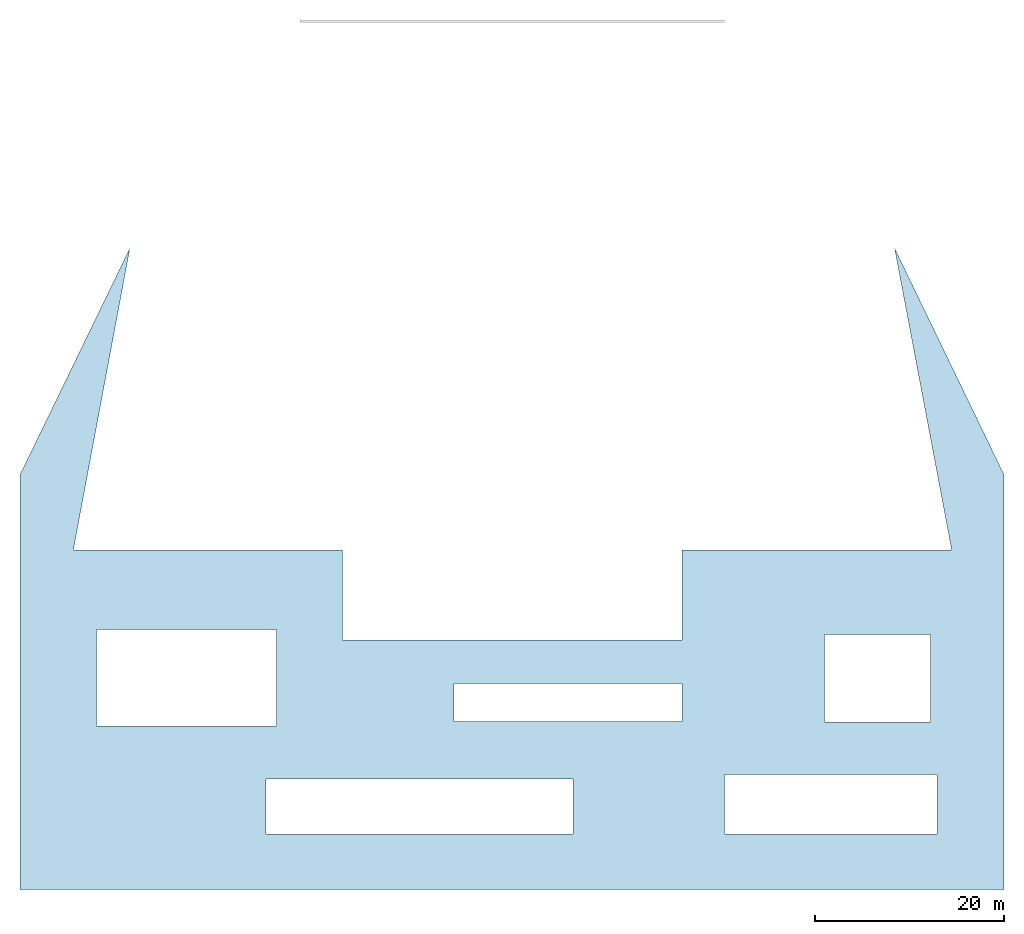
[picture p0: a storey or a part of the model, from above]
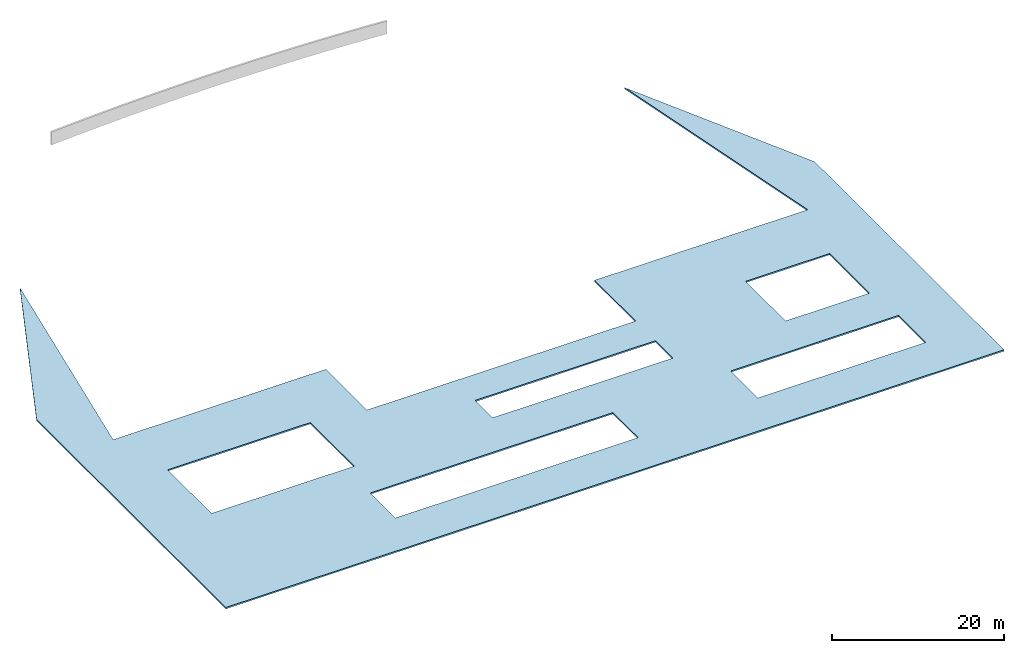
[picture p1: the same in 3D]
Properties of the parts of a building model (IFC2X3), part 1 of 4

# File
Description: ViewDefinition [CoordinationView_V2.0, QuantityTakeOffAddOnView]
File name: Project Number
Time: 2019-07-19T18:44:57
Written by: The EXPRESS Data Manager Version 5.02.0100.07 : 28 Aug 2013
Made in: 20170223_1515(x64) - Exporter 18.4.0.0 - Alternate UI 18.4.0.0
Comment: STEP Physical File produced by: The EXPRESS Data Manager Version 5.02.0100.07 : 28 Aug 2013 * Module: EDMstepFileFactory/EDMstandAlone * Creation date: Fri Jul 19 18:44:57 2019 * Host: ICIVEML714002 * Database: C:\Users\JL9E96~1.PON\AppData\Local\Temp\{DA7AC324-765A-4AAA-A41D-38224F9B8CCA}\ifc * Database version: 5507 * Database creation date: Fri Jul 19 18:44:33 2019 * Schema: IFC2X3 * Model: DataRepository.ifc * Model creation date: Fri Jul 19 18:44:33 2019 * Header model: DataRepository.ifc_HeaderModel * Header model creation date: Fri Jul 19 18:44:33 2019 * EDMuser: sdai-user * EDMgroup: sdai-group * License ID and type: 5605 : Permanent license. Expiry date: * EDMstepFileFactory options: 020000

# IfcProject, Project Number
LongName: Project Name; Phase: Project Status

# IfcSite, Default
RefLatitude: 47, 33, 34, 948799; RefLongitude: 19, 3, 17, 204399; RefElevation: 0 mm
Other - Category: Project Information; Client Name: Owner; Project Address: ## Street City, State Zip; Project Issue Date: Issue Date; Project Name: Project Name; Project Number: Project Number; Project Status: Project Status

# IfcBuilding
Pset_BuildingCommon - NumberOfStoreys: 6
Pset_ProductRequirements - Category: Project Information
Other - Category: Project Information; Client Name: Owner; Project Address: ## Street City, State Zip; Project Issue Date: Issue Date; Project Name: Project Name; Project Number: Project Number; Project Status: Project Status

# IfcBuildingStorey: Level:8mm Head (6)
Other(Type) - Category: Levels; Family Name: Level
Identity Data(Type) - Type Name: 8mm Head
Graphics(Type) - Color: 0; Line Pattern: Center; Line Weight: 1; Symbol: M_Level Head - Circle: M_Level Head - Circle; Symbol at End 1 Default: no; Symbol at End 2 Default: yes
Constraints(Type) - Elevation Base: Project Base Point
Pset_ProductRequirements - Category: Levels
Dimensions - Computation Height: 0 mm
Identity Data - Building Story: yes; Structural: no
Other - Category: Levels; Family: Level: 8mm Head; Family and Type: Level: 8mm Head; Type: Level: 8mm Head; Type Id: Level: 8mm Head
Name | LongName = Pset_AirSideSystemInformation, Name = Pset_ProductRequirements, Name = Identity Data, Name | Elevation (mm) = Constraints, Elevation (mm)
-4. Story | -4. Story | -5500
-2. Story | -2. Story | -3000
-1. Story | -1. Story | -1000
Ground Floor | Ground Floor | 0
1. Story | 1. Story | 3600
2. Story | 2. Story | 6600

# IfcBuildingElementProxy: BMR - 026, BMR - 026:BMR - 026:220502
In: 2. Story
Type - Classification: B1020245 Beams - Wood (Laminated) (Uniformat); Material: Paint - Yellow Ochre
Type - Identity Data - Assembly Code: B1020245; Assembly Description: Beams - Wood (Laminated); Type Name: BMR - 026
Type - Other - Category: Structural Framing; Family Name: BMR - 026
Type - Structural - Section Shape: 0
Type - Pset_BuildingElementProxyCommon - Reference: 07_Glued_laminated_timber 250 x 1810
Type - Pset_ProductRequirements - Category: Structural Framing
Type - Pset_QuantityTakeOff - Reference: 07_Glued_laminated_timber 250 x 1810
Pset_BuildingElementProxyCommon - sets with these values: 2
Constraints - Moves With Nearby Elements: no
Dimensions - Area: 95.7812 m2; Volume: 20.9311 m3
Materials and Finishes - Structural Material: Plywood, Sheathing
Other - Family: BMR - 026: BMR - 026; Family and Type: BMR - 026: BMR - 026; Type: BMR - 026: BMR - 026; Type Id: BMR - 026: BMR - 026
Phasing - Phase Created: New Construction
Structural - Rebar Cover: Rebar Cover Settings: Rebar Cover 1

# IfcBuildingElementProxy: BMR - 027, BMR - 027:BMR - 027:220488
In: 1. Story
Type - Classification: B1020245 Beams - Wood (Laminated) (Uniformat); Material: Paint - Yellow Ochre
Type - Identity Data - Assembly Code: B1020245; Assembly Description: Beams - Wood (Laminated); Type Name: BMR - 027
Type - Other - Category: Structural Framing; Family Name: BMR - 027
Type - Structural - Section Shape: 0
Type - Pset_BuildingElementProxyCommon - Reference: 07_Glued_laminated_timber 250 x 1810
Type - Pset_ProductRequirements - Category: Structural Framing
Type - Pset_QuantityTakeOff - Reference: 07_Glued_laminated_timber 250 x 1810
Pset_BuildingElementProxyCommon - sets with these values: 2
Constraints - Moves With Nearby Elements: no
Dimensions - Area: 95.1594 m2; Volume: 20.7967 m3
Materials and Finishes - Structural Material: Plywood, Sheathing
Other - Family: BMR - 027: BMR - 027; Family and Type: BMR - 027: BMR - 027; Type: BMR - 027: BMR - 027; Type Id: BMR - 027: BMR - 027
Phasing - Phase Created: New Construction
Structural - Rebar Cover: Rebar Cover Settings: Rebar Cover 1

# IfcBuildingElementProxy: BMR - 028, BMR - 028:BMR - 028:220460
In: 1. Story
Type - Classification: B1020245 Beams - Wood (Laminated) (Uniformat); Material: Paint - Yellow Ochre
Type - Identity Data - Assembly Code: B1020245; Assembly Description: Beams - Wood (Laminated); Type Name: BMR - 028
Type - Other - Category: Structural Framing; Family Name: BMR - 028
Type - Structural - Section Shape: 0
Type - Pset_BuildingElementProxyCommon - Reference: 07_Glued_laminated_timber 250 x 1810
Type - Pset_ProductRequirements - Category: Structural Framing
Type - Pset_QuantityTakeOff - Reference: 07_Glued_laminated_timber 250 x 1810
Pset_BuildingElementProxyCommon - sets with these values: 2
Constraints - Moves With Nearby Elements: no
Dimensions - Area: 94.1748 m2; Volume: 20.5838 m3
Materials and Finishes - Structural Material: Plywood, Sheathing
Other - Family: BMR - 028: BMR - 028; Family and Type: BMR - 028: BMR - 028; Type: BMR - 028: BMR - 028; Type Id: BMR - 028: BMR - 028
Phasing - Phase Created: New Construction
Structural - Rebar Cover: Rebar Cover Settings: Rebar Cover 1

# IfcBuildingElementProxy: BMR - 028, BMR - 028 2187528:BMR - 028 2187528:220481
In: 1. Story
Type - Classification: B1020245 Beams - Wood (Laminated) (Uniformat); Material: Paint - Yellow Ochre
Type - Identity Data - Assembly Code: B1020245; Assembly Description: Beams - Wood (Laminated); Type Name: BMR - 028 2187528
Type - Other - Category: Structural Framing; Family Name: BMR - 028 2187528
Type - Structural - Section Shape: 0
Type - Pset_BuildingElementProxyCommon - Reference: 07_Glued_laminated_timber 250 x 1810
Type - Pset_ProductRequirements - Category: Structural Framing
Type - Pset_QuantityTakeOff - Reference: 07_Glued_laminated_timber 250 x 1810
Pset_BuildingElementProxyCommon - sets with these values: 2
Constraints - Moves With Nearby Elements: no
Dimensions - Area: 94.6252 m2; Volume: 20.6812 m3
Materials and Finishes - Structural Material: Plywood, Sheathing
Other - Family: BMR - 028 2187528: BMR - 028 2187528; Family and Type: BMR - 028 2187528: BMR - 028 2187528; Type: BMR - 028 2187528: BMR - 028 2187528; Type Id: BMR - 028 2187528: BMR - 028 2187528
Phasing - Phase Created: New Construction
Structural - Rebar Cover: Rebar Cover Settings: Rebar Cover 1

# IfcBuildingElementProxy: BMR - 029, BMR - 029:BMR - 029:220467
In: Ground Floor
Type - Classification: B1020245 Beams - Wood (Laminated) (Uniformat); Material: Paint - Yellow Ochre
Type - Identity Data - Assembly Code: B1020245; Assembly Description: Beams - Wood (Laminated); Type Name: BMR - 029
Type - Other - Category: Structural Framing; Family Name: BMR - 029
Type - Structural - Section Shape: 0
Type - Pset_BuildingElementProxyCommon - Reference: 07_Glued_laminated_timber 250 x 1810
Type - Pset_ProductRequirements - Category: Structural Framing
Type - Pset_QuantityTakeOff - Reference: 07_Glued_laminated_timber 250 x 1810
Pset_BuildingElementProxyCommon - sets with these values: 2
Constraints - Moves With Nearby Elements: no
Dimensions - Area: 93.8023 m2; Volume: 20.5032 m3
Materials and Finishes - Structural Material: Plywood, Sheathing
Other - Family: BMR - 029: BMR - 029; Family and Type: BMR - 029: BMR - 029; Type: BMR - 029: BMR - 029; Type Id: BMR - 029: BMR - 029
Phasing - Phase Created: New Construction
Structural - Rebar Cover: Rebar Cover Settings: Rebar Cover 1

# IfcBuildingElementProxy: BMR - 030, BMR - 030:BMR - 030:220416
In: Ground Floor
Type - Classification: B1020245 Beams - Wood (Laminated) (Uniformat); Material: Paint - Yellow Ochre
Type - Identity Data - Assembly Code: B1020245; Assembly Description: Beams - Wood (Laminated); Type Name: BMR - 030
Type - Other - Category: Structural Framing; Family Name: BMR - 030
Type - Structural - Section Shape: 0
Type - Pset_BuildingElementProxyCommon - Reference: 07_Glued_laminated_timber 250 x 1810
Type - Pset_ProductRequirements - Category: Structural Framing
Type - Pset_QuantityTakeOff - Reference: 07_Glued_laminated_timber 250 x 1810
Pset_BuildingElementProxyCommon - sets with these values: 2
Constraints - Moves With Nearby Elements: no
Dimensions - Area: 93.522 m2; Volume: 20.4425 m3
Materials and Finishes - Structural Material: Plywood, Sheathing
Other - Family: BMR - 030: BMR - 030; Family and Type: BMR - 030: BMR - 030; Type: BMR - 030: BMR - 030; Type Id: BMR - 030: BMR - 030
Phasing - Phase Created: New Construction
Structural - Rebar Cover: Rebar Cover Settings: Rebar Cover 1

# IfcBuildingElementProxy: BMR - 031, BMR - 031:BMR - 031:217719
In: Ground Floor
Type - Classification: B1020245 Beams - Wood (Laminated) (Uniformat); Material: Paint - Yellow Ochre
Type - Identity Data - Assembly Code: B1020245; Assembly Description: Beams - Wood (Laminated); Type Name: BMR - 031
Type - Other - Category: Structural Framing; Family Name: BMR - 031
Type - Structural - Section Shape: 0
Type - Pset_BuildingElementProxyCommon - Reference: 07_Glued_laminated_timber 250 x 1810
Type - Pset_ProductRequirements - Category: Structural Framing
Type - Pset_QuantityTakeOff - Reference: 07_Glued_laminated_timber 250 x 1810
Pset_BuildingElementProxyCommon - sets with these values: 2
Constraints - Moves With Nearby Elements: no
Dimensions - Area: 93.3194 m2; Volume: 20.3987 m3
Materials and Finishes - Structural Material: Plywood, Sheathing
Other - Family: BMR - 031: BMR - 031; Family and Type: BMR - 031: BMR - 031; Type: BMR - 031: BMR - 031; Type Id: BMR - 031: BMR - 031
Phasing - Phase Created: New Construction
Structural - Rebar Cover: Rebar Cover Settings: Rebar Cover 1

# IfcBuildingElementProxy: BMR - 032, BMR - 032:BMR - 032:217654
In: -1. Story
Type - Classification: B1020245 Beams - Wood (Laminated) (Uniformat); Material: Plywood, Sheathing
Type - Identity Data - Assembly Code: B1020245; Assembly Description: Beams - Wood (Laminated); Type Name: BMR - 032
Type - Other - Category: Structural Framing; Family Name: BMR - 032
Type - Structural - Section Shape: 0
Type - Pset_BuildingElementProxyCommon - Reference: 07_Glued_laminated_timber 250 x 1810
Type - Pset_ProductRequirements - Category: Structural Framing
Type - Pset_QuantityTakeOff - Reference: 07_Glued_laminated_timber 250 x 1810
Pset_BuildingElementProxyCommon - sets with these values: 2
Constraints - Moves With Nearby Elements: no
Materials and Finishes - Structural Material: Plywood, Sheathing
Other - Family: BMR - 032: BMR - 032; Family and Type: BMR - 032: BMR - 032; Type: BMR - 032: BMR - 032; Type Id: BMR - 032: BMR - 032
Phasing - Phase Created: New Construction
Structural - Rebar Cover: Rebar Cover Settings: Rebar Cover 1

# IfcBuildingElementProxy: FU - 004, FU - 004:FU - 004:213398
In: Ground Floor
Type - Classification: G2010500 Painted Lines & Markings (Uniformat); Material: Paint - Titanium White
Type - Identity Data - Assembly Code: G2010500; Assembly Description: Painted Lines & Markings; Type Name: FU - 004
Type - Other - Category: Generic Models; Family Name: FU - 004
Type - Pset_BuildingElementProxyCommon - Reference: FU - 004
Type - Pset_ProductRequirements - Category: Generic Models
Type - Pset_QuantityTakeOff - Reference: FU - 004
Pset_BuildingElementProxyCommon - sets with these values: 2
Constraints - Moves With Nearby Elements: no
Dimensions - Area: 57.5186 m2; Volume: 1.4172 m3
Other - Family: FU - 004: FU - 004; Family and Type: FU - 004: FU - 004; Type: FU - 004: FU - 004; Type Id: FU - 004: FU - 004
Phasing - Phase Created: New Construction

# IfcBuildingElementProxy: FU - 004, FU - 004 1750820:FU - 004 1750820:214772
In: Ground Floor
Type - Classification: G2010500 Painted Lines & Markings (Uniformat); Material: Paint - Titanium White, Metal - Stainless Steel
Type - Identity Data - Assembly Code: G2010500; Assembly Description: Painted Lines & Markings; Type Name: FU - 004 1750820
Type - Other - Category: Generic Models; Family Name: FU - 004 1750820
Type - Pset_BuildingElementProxyCommon - Reference: FU - 004 1750820
Type - Pset_ProductRequirements - Category: Generic Models
Type - Pset_QuantityTakeOff - Reference: FU - 004 1750820
Pset_BuildingElementProxyCommon - sets with these values: 2
Constraints - Moves With Nearby Elements: no
Dimensions - Area: 12.684 m2; Volume: 0.286123 m3
Other - Family: FU - 004 1750820: FU - 004 1750820; Family and Type: FU - 004 1750820: FU - 004 1750820; Type: FU - 004 1750820: FU - 004 1750820; Type Id: FU - 004 1750820: FU - 004 1750820
Phasing - Phase Created: New Construction

# IfcBuildingElementProxy: FU - 004, FU - 004 1769644:FU - 004 1769644:215817
In: Ground Floor
Type - Classification: G2010500 Painted Lines & Markings (Uniformat); Material: Paint - Titanium White, Metal - Stainless Steel
Type - Identity Data - Assembly Code: G2010500; Assembly Description: Painted Lines & Markings; Type Name: FU - 004 1769644
Type - Other - Category: Generic Models; Family Name: FU - 004 1769644
Type - Pset_BuildingElementProxyCommon - Reference: FU - 004 1769644
Type - Pset_ProductRequirements - Category: Generic Models
Type - Pset_QuantityTakeOff - Reference: FU - 004 1769644
Pset_BuildingElementProxyCommon - sets with these values: 2
Constraints - Moves With Nearby Elements: no
Dimensions - Area: 12.684 m2; Volume: 0.286123 m3
Other - Family: FU - 004 1769644: FU - 004 1769644; Family and Type: FU - 004 1769644: FU - 004 1769644; Type: FU - 004 1769644: FU - 004 1769644; Type Id: FU - 004 1769644: FU - 004 1769644
Phasing - Phase Created: New Construction

# IfcBuildingElementProxy: FU - 004, FU - 004 1777966:FU - 004 1777966:216424
In: Ground Floor
Type - Classification: G2010500 Painted Lines & Markings (Uniformat); Material: Paint - Titanium White, Metal - Stainless Steel
Type - Identity Data - Assembly Code: G2010500; Assembly Description: Painted Lines & Markings; Type Name: FU - 004 1777966
Type - Other - Category: Generic Models; Family Name: FU - 004 1777966
Type - Pset_BuildingElementProxyCommon - Reference: FU - 004 1777966
Type - Pset_ProductRequirements - Category: Generic Models
Type - Pset_QuantityTakeOff - Reference: FU - 004 1777966
Pset_BuildingElementProxyCommon - sets with these values: 2
Constraints - Moves With Nearby Elements: no
Dimensions - Area: 12.684 m2; Volume: 0.286123 m3
Other - Family: FU - 004 1777966: FU - 004 1777966; Family and Type: FU - 004 1777966: FU - 004 1777966; Type: FU - 004 1777966: FU - 004 1777966; Type Id: FU - 004 1777966: FU - 004 1777966
Phasing - Phase Created: New Construction

# IfcBuildingElementProxy: FU - 004, FU - 004 2050029:FU - 004 2050029:217726
In: Ground Floor
Type - Classification: G2010500 Painted Lines & Markings (Uniformat); Material: Paint - Titanium White, Metal - Stainless Steel
Type - Identity Data - Assembly Code: G2010500; Assembly Description: Painted Lines & Markings; Type Name: FU - 004 2050029
Type - Other - Category: Generic Models; Family Name: FU - 004 2050029
Type - Pset_BuildingElementProxyCommon - Reference: FU - 004 2050029
Type - Pset_ProductRequirements - Category: Generic Models
Type - Pset_QuantityTakeOff - Reference: FU - 004 2050029
Pset_BuildingElementProxyCommon - sets with these values: 2
Constraints - Moves With Nearby Elements: no
Dimensions - Area: 12.684 m2; Volume: 0.286123 m3
Other - Family: FU - 004 2050029: FU - 004 2050029; Family and Type: FU - 004 2050029: FU - 004 2050029; Type: FU - 004 2050029: FU - 004 2050029; Type Id: FU - 004 2050029: FU - 004 2050029
Phasing - Phase Created: New Construction

# IfcBuildingElementProxy: FU - 007, FU - 007:FU - 007:201155
In: -4. Story
Type - Classification: F1040100 Aquatic Facilities (Uniformat); Material: Paint - Gray, Water - Pond, Paint - Titanium White, Metal - Stainless Steel, Paint - Royal Blue, Paint - Vermilion
Type - Identity Data - Assembly Code: F1040100; Assembly Description: Aquatic Facilities; Type Name: FU - 007
Type - Other - Category: Generic Models; Family Name: FU - 007
Type - Pset_BuildingElementProxyCommon - Reference: FU - 007
Type - Pset_ProductRequirements - Category: Generic Models
Type - Pset_QuantityTakeOff - Reference: FU - 007
Pset_BuildingElementProxyCommon - sets with these values: 2
Constraints - Moves With Nearby Elements: no
Dimensions - Area: 2268.79 m2; Volume: 1597.47 m3
Other - Family: FU - 007: FU - 007; Family and Type: FU - 007: FU - 007; Type: FU - 007: FU - 007; Type Id: FU - 007: FU - 007
Phasing - Phase Created: New Construction

# IfcBuildingElementProxy: FU - 007, FU - 007 1380037:FU - 007 1380037:201343
In: -4. Story
Type - Classification: F1040100 Aquatic Facilities (Uniformat); Material: Paint - Gray, Water - Pond, Paint - Titanium White, Metal - Stainless Steel, Paint - Royal Blue, Paint - Vermilion
Type - Identity Data - Assembly Code: F1040100; Assembly Description: Aquatic Facilities; Type Name: FU - 007 1380037
Type - Other - Category: Generic Models; Family Name: FU - 007 1380037
Type - Pset_BuildingElementProxyCommon - Reference: FU - 007 1380037
Type - Pset_ProductRequirements - Category: Generic Models
Type - Pset_QuantityTakeOff - Reference: FU - 007 1380037
Pset_BuildingElementProxyCommon - sets with these values: 2
Constraints - Moves With Nearby Elements: no
Dimensions - Area: 1217.01 m2; Volume: 806.765 m3
Other - Family: FU - 007 1380037: FU - 007 1380037; Family and Type: FU - 007 1380037: FU - 007 1380037; Type: FU - 007 1380037: FU - 007 1380037; Type Id: FU - 007 1380037: FU - 007 1380037
Phasing - Phase Created: New Construction

# IfcBuildingElementProxy: FU - 008, FU - 008 1515161:FU - 008 1515161:205280
In: -2. Story
Type - Classification: E2020200 Furniture & Accessories (Uniformat); Material: Glass - Mirror, Metal - Stainless Steel
Type - Identity Data - Assembly Code: E2020200; Assembly Description: Furniture & Accessories; Type Name: FU - 008 1515161
Type - Other - Category: Generic Models; Family Name: FU - 008 1515161
Type - Pset_BuildingElementProxyCommon - Reference: FU - 008 1515161
Type - Pset_ProductRequirements - Category: Generic Models
Type - Pset_QuantityTakeOff - Reference: FU - 008 1515161
Pset_BuildingElementProxyCommon - sets with these values: 2
Constraints - Moves With Nearby Elements: no
Dimensions - Area: 1.91536 m2; Volume: 0.0251271 m3
Other - Family: FU - 008 1515161: FU - 008 1515161; Family and Type: FU - 008 1515161: FU - 008 1515161; Type: FU - 008 1515161: FU - 008 1515161; Type Id: FU - 008 1515161: FU - 008 1515161
Phasing - Phase Created: New Construction

# IfcBuildingElementProxy: FU - 008, FU - 008 1515332:FU - 008 1515332:205342
In: -2. Story
Type - Classification: E2020200 Furniture & Accessories (Uniformat); Material: Glass - Mirror, Metal - Stainless Steel
Type - Identity Data - Assembly Code: E2020200; Assembly Description: Furniture & Accessories; Type Name: FU - 008 1515332
Type - Other - Category: Generic Models; Family Name: FU - 008 1515332
Type - Pset_BuildingElementProxyCommon - Reference: FU - 008 1515332
Type - Pset_ProductRequirements - Category: Generic Models
Type - Pset_QuantityTakeOff - Reference: FU - 008 1515332
Pset_BuildingElementProxyCommon - sets with these values: 2
Constraints - Moves With Nearby Elements: no
Dimensions - Area: 1.91536 m2; Volume: 0.0251271 m3
Other - Family: FU - 008 1515332: FU - 008 1515332; Family and Type: FU - 008 1515332: FU - 008 1515332; Type: FU - 008 1515332: FU - 008 1515332; Type Id: FU - 008 1515332: FU - 008 1515332
Phasing - Phase Created: New Construction

# IfcBuildingElementProxy: FU - 008, FU - 008 1568106:FU - 008 1568106:208407
In: -2. Story
Type - Classification: E2020200 Furniture & Accessories (Uniformat); Material: Glass - Mirror, Metal - Stainless Steel
Type - Identity Data - Assembly Code: E2020200; Assembly Description: Furniture & Accessories; Type Name: FU - 008 1568106
Type - Other - Category: Generic Models; Family Name: FU - 008 1568106
Type - Pset_BuildingElementProxyCommon - Reference: FU - 008 1568106
Type - Pset_ProductRequirements - Category: Generic Models
Type - Pset_QuantityTakeOff - Reference: FU - 008 1568106
Pset_BuildingElementProxyCommon - sets with these values: 2
Constraints - Moves With Nearby Elements: no
Dimensions - Area: 2.07269 m2; Volume: 0.0271752 m3
Other - Family: FU - 008 1568106: FU - 008 1568106; Family and Type: FU - 008 1568106: FU - 008 1568106; Type: FU - 008 1568106: FU - 008 1568106; Type Id: FU - 008 1568106: FU - 008 1568106
Phasing - Phase Created: New Construction

# IfcBuildingElementProxy: FU - 008, FU - 008 1568273:FU - 008 1568273:208449
In: -2. Story
Type - Classification: E2020200 Furniture & Accessories (Uniformat); Material: Glass - Mirror, Metal - Stainless Steel
Type - Identity Data - Assembly Code: E2020200; Assembly Description: Furniture & Accessories; Type Name: FU - 008 1568273
Type - Other - Category: Generic Models; Family Name: FU - 008 1568273
Type - Pset_BuildingElementProxyCommon - Reference: FU - 008 1568273
Type - Pset_ProductRequirements - Category: Generic Models
Type - Pset_QuantityTakeOff - Reference: FU - 008 1568273
Pset_BuildingElementProxyCommon - sets with these values: 2
Constraints - Moves With Nearby Elements: no
Dimensions - Area: 1.91536 m2; Volume: 0.0251271 m3
Other - Family: FU - 008 1568273: FU - 008 1568273; Family and Type: FU - 008 1568273: FU - 008 1568273; Type: FU - 008 1568273: FU - 008 1568273; Type Id: FU - 008 1568273: FU - 008 1568273
Phasing - Phase Created: New Construction

# IfcBuildingElementProxy: FU - 008, FU - 008 1568431:FU - 008 1568431:208491
In: -2. Story
Type - Classification: E2020200 Furniture & Accessories (Uniformat); Material: Glass - Mirror, Metal - Stainless Steel
Type - Identity Data - Assembly Code: E2020200; Assembly Description: Furniture & Accessories; Type Name: FU - 008 1568431
Type - Other - Category: Generic Models; Family Name: FU - 008 1568431
Type - Pset_BuildingElementProxyCommon - Reference: FU - 008 1568431
Type - Pset_ProductRequirements - Category: Generic Models
Type - Pset_QuantityTakeOff - Reference: FU - 008 1568431
Pset_BuildingElementProxyCommon - sets with these values: 2
Constraints - Moves With Nearby Elements: no
Dimensions - Area: 1.91536 m2; Volume: 0.0251271 m3
Other - Family: FU - 008 1568431: FU - 008 1568431; Family and Type: FU - 008 1568431: FU - 008 1568431; Type: FU - 008 1568431: FU - 008 1568431; Type Id: FU - 008 1568431: FU - 008 1568431
Phasing - Phase Created: New Construction

# IfcBuildingElementProxy: FU - 008, FU - 008 1590037:FU - 008 1590037:209053
In: -2. Story
Type - Classification: E2020200 Furniture & Accessories (Uniformat); Material: Glass - Mirror, Metal - Stainless Steel
Type - Identity Data - Assembly Code: E2020200; Assembly Description: Furniture & Accessories; Type Name: FU - 008 1590037
Type - Other - Category: Generic Models; Family Name: FU - 008 1590037
Type - Pset_BuildingElementProxyCommon - Reference: FU - 008 1590037
Type - Pset_ProductRequirements - Category: Generic Models
Type - Pset_QuantityTakeOff - Reference: FU - 008 1590037
Pset_BuildingElementProxyCommon - sets with these values: 2
Constraints - Moves With Nearby Elements: no
Dimensions - Area: 1.91536 m2; Volume: 0.0251271 m3
Other - Family: FU - 008 1590037: FU - 008 1590037; Family and Type: FU - 008 1590037: FU - 008 1590037; Type: FU - 008 1590037: FU - 008 1590037; Type Id: FU - 008 1590037: FU - 008 1590037
Phasing - Phase Created: New Construction

# IfcBuildingElementProxy: FU - 008, FU - 008 1590204:FU - 008 1590204:209095
In: -2. Story
Type - Classification: E2020200 Furniture & Accessories (Uniformat); Material: Glass - Mirror, Metal - Stainless Steel
Type - Identity Data - Assembly Code: E2020200; Assembly Description: Furniture & Accessories; Type Name: FU - 008 1590204
Type - Other - Category: Generic Models; Family Name: FU - 008 1590204
Type - Pset_BuildingElementProxyCommon - Reference: FU - 008 1590204
Type - Pset_ProductRequirements - Category: Generic Models
Type - Pset_QuantityTakeOff - Reference: FU - 008 1590204
Pset_BuildingElementProxyCommon - sets with these values: 2
Constraints - Moves With Nearby Elements: no
Dimensions - Area: 1.91536 m2; Volume: 0.0251271 m3
Other - Family: FU - 008 1590204: FU - 008 1590204; Family and Type: FU - 008 1590204: FU - 008 1590204; Type: FU - 008 1590204: FU - 008 1590204; Type Id: FU - 008 1590204: FU - 008 1590204
Phasing - Phase Created: New Construction

# IfcBuildingElementProxy: FU - 008, FU - 008 1618691:FU - 008 1618691:212044
In: -2. Story
Type - Classification: E2020200 Furniture & Accessories (Uniformat); Material: Glass - Mirror, Metal - Stainless Steel
Type - Identity Data - Assembly Code: E2020200; Assembly Description: Furniture & Accessories; Type Name: FU - 008 1618691
Type - Other - Category: Generic Models; Family Name: FU - 008 1618691
Type - Pset_BuildingElementProxyCommon - Reference: FU - 008 1618691
Type - Pset_ProductRequirements - Category: Generic Models
Type - Pset_QuantityTakeOff - Reference: FU - 008 1618691
Pset_BuildingElementProxyCommon - sets with these values: 2
Constraints - Moves With Nearby Elements: no
Dimensions - Area: 2.07269 m2; Volume: 0.0271752 m3
Other - Family: FU - 008 1618691: FU - 008 1618691; Family and Type: FU - 008 1618691: FU - 008 1618691; Type: FU - 008 1618691: FU - 008 1618691; Type Id: FU - 008 1618691: FU - 008 1618691
Phasing - Phase Created: New Construction

# IfcBuildingElementProxy: FU - 008, FU - 008 1618858:FU - 008 1618858:212086
In: -2. Story
Type - Classification: E2020200 Furniture & Accessories (Uniformat); Material: Glass - Mirror, Metal - Stainless Steel
Type - Identity Data - Assembly Code: E2020200; Assembly Description: Furniture & Accessories; Type Name: FU - 008 1618858
Type - Other - Category: Generic Models; Family Name: FU - 008 1618858
Type - Pset_BuildingElementProxyCommon - Reference: FU - 008 1618858
Type - Pset_ProductRequirements - Category: Generic Models
Type - Pset_QuantityTakeOff - Reference: FU - 008 1618858
Pset_BuildingElementProxyCommon - sets with these values: 2
Constraints - Moves With Nearby Elements: no
Dimensions - Area: 1.91536 m2; Volume: 0.0251271 m3
Other - Family: FU - 008 1618858: FU - 008 1618858; Family and Type: FU - 008 1618858: FU - 008 1618858; Type: FU - 008 1618858: FU - 008 1618858; Type Id: FU - 008 1618858: FU - 008 1618858
Phasing - Phase Created: New Construction

# IfcBuildingElementProxy: FU - 008, FU - 008 1619016:FU - 008 1619016:212128
In: -2. Story
Type - Classification: E2020200 Furniture & Accessories (Uniformat); Material: Glass - Mirror, Metal - Stainless Steel
Type - Identity Data - Assembly Code: E2020200; Assembly Description: Furniture & Accessories; Type Name: FU - 008 1619016
Type - Other - Category: Generic Models; Family Name: FU - 008 1619016
Type - Pset_BuildingElementProxyCommon - Reference: FU - 008 1619016
Type - Pset_ProductRequirements - Category: Generic Models
Type - Pset_QuantityTakeOff - Reference: FU - 008 1619016
Pset_BuildingElementProxyCommon - sets with these values: 2
Constraints - Moves With Nearby Elements: no
Dimensions - Area: 1.91536 m2; Volume: 0.0251271 m3
Other - Family: FU - 008 1619016: FU - 008 1619016; Family and Type: FU - 008 1619016: FU - 008 1619016; Type: FU - 008 1619016: FU - 008 1619016; Type Id: FU - 008 1619016: FU - 008 1619016
Phasing - Phase Created: New Construction

# IfcBuildingElementProxy: FU - 008, FU - 008:FU - 008:202605
In: -4. Story
Type - Classification: F1040100 Aquatic Facilities (Uniformat); Material: Paint - Gray, Water - Pond, Paint - Titanium White, Metal - Stainless Steel
Type - Identity Data - Assembly Code: F1040100; Assembly Description: Aquatic Facilities; Type Name: FU - 008
Type - Other - Category: Generic Models; Family Name: FU - 008
Type - Pset_BuildingElementProxyCommon - Reference: FU - 008
Type - Pset_ProductRequirements - Category: Generic Models
Type - Pset_QuantityTakeOff - Reference: FU - 008
Pset_BuildingElementProxyCommon - sets with these values: 2
Constraints - Moves With Nearby Elements: no
Dimensions - Area: 376.904 m2; Volume: 195.702 m3
Other - Family: FU - 008: FU - 008; Family and Type: FU - 008: FU - 008; Type: FU - 008: FU - 008; Type Id: FU - 008: FU - 008
Phasing - Phase Created: New Construction

# IfcBuildingElementProxy: FU - 012, FU - 012:FU - 012:208655
In: -2. Story
Type - Classification: E2020200 Furniture & Accessories (Uniformat); Material: Paint - Glossy White, Paint - Light Gray
Type - Identity Data - Assembly Code: E2020200; Assembly Description: Furniture & Accessories; Type Name: FU - 012
Type - Other - Category: Generic Models; Family Name: FU - 012
Type - Pset_BuildingElementProxyCommon - Reference: FU - 012
Type - Pset_ProductRequirements - Category: Generic Models
Type - Pset_QuantityTakeOff - Reference: FU - 012
Pset_BuildingElementProxyCommon - sets with these values: 2
Constraints - Moves With Nearby Elements: no
Dimensions - Area: 0.770176 m2; Volume: 0.0289079 m3
Other - Family: FU - 012: FU - 012; Family and Type: FU - 012: FU - 012; Type: FU - 012: FU - 012; Type Id: FU - 012: FU - 012
Phasing - Phase Created: New Construction

# IfcBuildingElementProxy: FU - 012, FU - 012 1574144:FU - 012 1574144:208670
In: -2. Story
Type - Classification: E2020200 Furniture & Accessories (Uniformat); Material: Paint - Glossy White, Paint - Light Gray
Type - Identity Data - Assembly Code: E2020200; Assembly Description: Furniture & Accessories; Type Name: FU - 012 1574144
Type - Other - Category: Generic Models; Family Name: FU - 012 1574144
Type - Pset_BuildingElementProxyCommon - Reference: FU - 012 1574144
Type - Pset_ProductRequirements - Category: Generic Models
Type - Pset_QuantityTakeOff - Reference: FU - 012 1574144
Pset_BuildingElementProxyCommon - sets with these values: 2
Constraints - Moves With Nearby Elements: no
Dimensions - Area: 0.770176 m2; Volume: 0.0289079 m3
Other - Family: FU - 012 1574144: FU - 012 1574144; Family and Type: FU - 012 1574144: FU - 012 1574144; Type: FU - 012 1574144: FU - 012 1574144; Type Id: FU - 012 1574144: FU - 012 1574144
Phasing - Phase Created: New Construction

# IfcBuildingElementProxy: FU - 012, FU - 012 1574295:FU - 012 1574295:208677
In: -2. Story
Type - Classification: E2020200 Furniture & Accessories (Uniformat); Material: Paint - Glossy White, Paint - Light Gray
Type - Identity Data - Assembly Code: E2020200; Assembly Description: Furniture & Accessories; Type Name: FU - 012 1574295
Type - Other - Category: Generic Models; Family Name: FU - 012 1574295
Type - Pset_BuildingElementProxyCommon - Reference: FU - 012 1574295
Type - Pset_ProductRequirements - Category: Generic Models
Type - Pset_QuantityTakeOff - Reference: FU - 012 1574295
Pset_BuildingElementProxyCommon - sets with these values: 2
Constraints - Moves With Nearby Elements: no
Dimensions - Area: 0.770176 m2; Volume: 0.0289079 m3
Other - Family: FU - 012 1574295: FU - 012 1574295; Family and Type: FU - 012 1574295: FU - 012 1574295; Type: FU - 012 1574295: FU - 012 1574295; Type Id: FU - 012 1574295: FU - 012 1574295
Phasing - Phase Created: New Construction

# IfcBuildingElementProxy: FU - 012, FU - 012 1585229:FU - 012 1585229:208816
In: -2. Story
Type - Classification: E2020200 Furniture & Accessories (Uniformat); Material: Paint - Glossy White, Paint - Light Gray
Type - Identity Data - Assembly Code: E2020200; Assembly Description: Furniture & Accessories; Type Name: FU - 012 1585229
Type - Other - Category: Generic Models; Family Name: FU - 012 1585229
Type - Pset_BuildingElementProxyCommon - Reference: FU - 012 1585229
Type - Pset_ProductRequirements - Category: Generic Models
Type - Pset_QuantityTakeOff - Reference: FU - 012 1585229
Pset_BuildingElementProxyCommon - sets with these values: 2
Constraints - Moves With Nearby Elements: no
Dimensions - Area: 0.770176 m2; Volume: 0.0289079 m3
Other - Family: FU - 012 1585229: FU - 012 1585229; Family and Type: FU - 012 1585229: FU - 012 1585229; Type: FU - 012 1585229: FU - 012 1585229; Type Id: FU - 012 1585229: FU - 012 1585229
Phasing - Phase Created: New Construction

# IfcBuildingElementProxy: FU - 012, FU - 012 1585389:FU - 012 1585389:208823
In: -2. Story
Type - Classification: E2020200 Furniture & Accessories (Uniformat); Material: Paint - Glossy White, Paint - Light Gray
Type - Identity Data - Assembly Code: E2020200; Assembly Description: Furniture & Accessories; Type Name: FU - 012 1585389
Type - Other - Category: Generic Models; Family Name: FU - 012 1585389
Type - Pset_BuildingElementProxyCommon - Reference: FU - 012 1585389
Type - Pset_ProductRequirements - Category: Generic Models
Type - Pset_QuantityTakeOff - Reference: FU - 012 1585389
Pset_BuildingElementProxyCommon - sets with these values: 2
Constraints - Moves With Nearby Elements: no
Dimensions - Area: 0.770176 m2; Volume: 0.0289079 m3
Other - Family: FU - 012 1585389: FU - 012 1585389; Family and Type: FU - 012 1585389: FU - 012 1585389; Type: FU - 012 1585389: FU - 012 1585389; Type Id: FU - 012 1585389: FU - 012 1585389
Phasing - Phase Created: New Construction

# IfcBuildingElementProxy: FU - 012, FU - 012 1585540:FU - 012 1585540:208830
In: -2. Story
Type - Classification: E2020200 Furniture & Accessories (Uniformat); Material: Paint - Glossy White, Paint - Light Gray
Type - Identity Data - Assembly Code: E2020200; Assembly Description: Furniture & Accessories; Type Name: FU - 012 1585540
Type - Other - Category: Generic Models; Family Name: FU - 012 1585540
Type - Pset_BuildingElementProxyCommon - Reference: FU - 012 1585540
Type - Pset_ProductRequirements - Category: Generic Models
Type - Pset_QuantityTakeOff - Reference: FU - 012 1585540
Pset_BuildingElementProxyCommon - sets with these values: 2
Constraints - Moves With Nearby Elements: no
Dimensions - Area: 0.770176 m2; Volume: 0.0289079 m3
Other - Family: FU - 012 1585540: FU - 012 1585540; Family and Type: FU - 012 1585540: FU - 012 1585540; Type: FU - 012 1585540: FU - 012 1585540; Type Id: FU - 012 1585540: FU - 012 1585540
Phasing - Phase Created: New Construction

# IfcBuildingElementProxy: FU - 013, FU - 013 1635584:FU - 013 1635584:212352
In: -2. Story
Type - Classification: E2020200 Furniture & Accessories (Uniformat); Material: Ceramic - Porcelain, Metal - Stainless Steel, builtInMatSemitransBlackPlastic
Type - Identity Data - Assembly Code: E2020200; Assembly Description: Furniture & Accessories; Type Name: FU - 013 1635584
Type - Other - Category: Generic Models; Family Name: FU - 013 1635584
Type - Pset_BuildingElementProxyCommon - Reference: FU - 013 1635584
Type - Pset_ProductRequirements - Category: Generic Models
Type - Pset_QuantityTakeOff - Reference: FU - 013 1635584
Pset_BuildingElementProxyCommon - sets with these values: 2
Constraints - Moves With Nearby Elements: no
Dimensions - Area: 0.429487 m2; Volume: 0.0165126 m3
Other - Family: FU - 013 1635584: FU - 013 1635584; Family and Type: FU - 013 1635584: FU - 013 1635584; Type: FU - 013 1635584: FU - 013 1635584; Type Id: FU - 013 1635584: FU - 013 1635584
Phasing - Phase Created: New Construction

# IfcBuildingElementProxy: FU - 013, FU - 013:FU - 013:212262
In: -2. Story
Type - Classification: E2020200 Furniture & Accessories (Uniformat); Material: Metal - Stainless Steel, builtInMatSemitransBlackPlastic
Type - Identity Data - Assembly Code: E2020200; Assembly Description: Furniture & Accessories; Type Name: FU - 013
Type - Other - Category: Generic Models; Family Name: FU - 013
Type - Pset_BuildingElementProxyCommon - Reference: FU - 013
Type - Pset_ProductRequirements - Category: Generic Models
Type - Pset_QuantityTakeOff - Reference: FU - 013
Pset_BuildingElementProxyCommon - sets with these values: 2
Constraints - Moves With Nearby Elements: no
Dimensions - Area: 1.49111 m2; Volume: 0.0333652 m3
Other - Family: FU - 013: FU - 013; Family and Type: FU - 013: FU - 013; Type: FU - 013: FU - 013; Type Id: FU - 013: FU - 013
Phasing - Phase Created: New Construction

# IfcBuildingElementProxy: FU - 013, FU - 013 1628369:FU - 013 1628369:212324
In: -2. Story
Type - Classification: E2020200 Furniture & Accessories (Uniformat); Material: Metal - Stainless Steel, builtInMatSemitransBlackPlastic
Type - Identity Data - Assembly Code: E2020200; Assembly Description: Furniture & Accessories; Type Name: FU - 013 1628369
Type - Other - Category: Generic Models; Family Name: FU - 013 1628369
Type - Pset_BuildingElementProxyCommon - Reference: FU - 013 1628369
Type - Pset_ProductRequirements - Category: Generic Models
Type - Pset_QuantityTakeOff - Reference: FU - 013 1628369
Pset_BuildingElementProxyCommon - sets with these values: 2
Constraints - Moves With Nearby Elements: no
Dimensions - Area: 1.49111 m2; Volume: 0.0333652 m3
Other - Family: FU - 013 1628369: FU - 013 1628369; Family and Type: FU - 013 1628369: FU - 013 1628369; Type: FU - 013 1628369: FU - 013 1628369; Type Id: FU - 013 1628369: FU - 013 1628369
Phasing - Phase Created: New Construction

# IfcBuildingElementProxy: FU - 013, FU - 013 1628608:FU - 013 1628608:212331
In: -2. Story
Type - Classification: E2020200 Furniture & Accessories (Uniformat); Material: Metal - Stainless Steel, builtInMatSemitransBlackPlastic
Type - Identity Data - Assembly Code: E2020200; Assembly Description: Furniture & Accessories; Type Name: FU - 013 1628608
Type - Other - Category: Generic Models; Family Name: FU - 013 1628608
Type - Pset_BuildingElementProxyCommon - Reference: FU - 013 1628608
Type - Pset_ProductRequirements - Category: Generic Models
Type - Pset_QuantityTakeOff - Reference: FU - 013 1628608
Pset_BuildingElementProxyCommon - sets with these values: 2
Constraints - Moves With Nearby Elements: no
Dimensions - Area: 1.49111 m2; Volume: 0.0333652 m3
Other - Family: FU - 013 1628608: FU - 013 1628608; Family and Type: FU - 013 1628608: FU - 013 1628608; Type: FU - 013 1628608: FU - 013 1628608; Type Id: FU - 013 1628608: FU - 013 1628608
Phasing - Phase Created: New Construction

# IfcBuildingElementProxy: FU - 013, FU - 013 1628847:FU - 013 1628847:212338
In: -2. Story
Type - Classification: E2020200 Furniture & Accessories (Uniformat); Material: Metal - Stainless Steel, builtInMatSemitransBlackPlastic
Type - Identity Data - Assembly Code: E2020200; Assembly Description: Furniture & Accessories; Type Name: FU - 013 1628847
Type - Other - Category: Generic Models; Family Name: FU - 013 1628847
Type - Pset_BuildingElementProxyCommon - Reference: FU - 013 1628847
Type - Pset_ProductRequirements - Category: Generic Models
Type - Pset_QuantityTakeOff - Reference: FU - 013 1628847
Pset_BuildingElementProxyCommon - sets with these values: 2
Constraints - Moves With Nearby Elements: no
Dimensions - Area: 1.49111 m2; Volume: 0.0333652 m3
Other - Family: FU - 013 1628847: FU - 013 1628847; Family and Type: FU - 013 1628847: FU - 013 1628847; Type: FU - 013 1628847: FU - 013 1628847; Type Id: FU - 013 1628847: FU - 013 1628847
Phasing - Phase Created: New Construction

# IfcBuildingElementProxy: FU - 013, FU - 013 1629086:FU - 013 1629086:212345
In: -2. Story
Type - Classification: E2020200 Furniture & Accessories (Uniformat); Material: Metal - Stainless Steel, builtInMatSemitransBlackPlastic
Type - Identity Data - Assembly Code: E2020200; Assembly Description: Furniture & Accessories; Type Name: FU - 013 1629086
Type - Other - Category: Generic Models; Family Name: FU - 013 1629086
Type - Pset_BuildingElementProxyCommon - Reference: FU - 013 1629086
Type - Pset_ProductRequirements - Category: Generic Models
Type - Pset_QuantityTakeOff - Reference: FU - 013 1629086
Pset_BuildingElementProxyCommon - sets with these values: 2
Constraints - Moves With Nearby Elements: no
Dimensions - Area: 1.49111 m2; Volume: 0.0333652 m3
Other - Family: FU - 013 1629086: FU - 013 1629086; Family and Type: FU - 013 1629086: FU - 013 1629086; Type: FU - 013 1629086: FU - 013 1629086; Type Id: FU - 013 1629086: FU - 013 1629086
Phasing - Phase Created: New Construction

# IfcBuildingElementProxy: WE - 001, WE - 001:WE - 001:204753
In: -2. Story
Type - Classification: C1010110 Partitions - Brick, Solid (Uniformat); Material: Stucco - White Fine
Type - Identity Data - Assembly Code: C1010110; Assembly Description: Partitions - Brick, Solid; Type Name: WE - 001
Type - Other - Category: Generic Models; Family Name: WE - 001
Type - Pset_BuildingElementProxyCommon - Reference: WE - 001
Type - Pset_ProductRequirements - Category: Generic Models
Type - Pset_QuantityTakeOff - Reference: WE - 001
Pset_BuildingElementProxyCommon - sets with these values: 2
Constraints - Moves With Nearby Elements: no
Dimensions - Area: 0.02 m2; Volume: 0.056 m3
Other - Family: WE - 001: WE - 001; Family and Type: WE - 001: WE - 001; Type: WE - 001: WE - 001; Type Id: WE - 001: WE - 001
Phasing - Phase Created: New Construction

# IfcBuildingElementProxy: WE - 001, WE - 001 1508935:WE - 001 1508935:204895
In: -2. Story
Type - Classification: C1010110 Partitions - Brick, Solid (Uniformat); Material: Stucco - White Fine
Type - Identity Data - Assembly Code: C1010110; Assembly Description: Partitions - Brick, Solid; Type Name: WE - 001 1508935
Type - Other - Category: Generic Models; Family Name: WE - 001 1508935
Type - Pset_BuildingElementProxyCommon - Reference: WE - 001 1508935
Type - Pset_ProductRequirements - Category: Generic Models
Type - Pset_QuantityTakeOff - Reference: WE - 001 1508935
Pset_BuildingElementProxyCommon - sets with these values: 2
Constraints - Moves With Nearby Elements: no
Dimensions - Area: 0.02 m2; Volume: 0.0542 m3
Other - Family: WE - 001 1508935: WE - 001 1508935; Family and Type: WE - 001 1508935: WE - 001 1508935; Type: WE - 001 1508935: WE - 001 1508935; Type Id: WE - 001 1508935: WE - 001 1508935
Phasing - Phase Created: New Construction

# IfcBuildingElementProxy: WE - 001, WE - 001 1586341:WE - 001 1586341:208853
In: -2. Story
Type - Classification: C1010110 Partitions - Brick, Solid (Uniformat); Material: Stucco - White Fine
Type - Identity Data - Assembly Code: C1010110; Assembly Description: Partitions - Brick, Solid; Type Name: WE - 001 1586341
Type - Other - Category: Generic Models; Family Name: WE - 001 1586341
Type - Pset_BuildingElementProxyCommon - Reference: WE - 001 1586341
Type - Pset_ProductRequirements - Category: Generic Models
Type - Pset_QuantityTakeOff - Reference: WE - 001 1586341
Pset_BuildingElementProxyCommon - sets with these values: 2
Constraints - Moves With Nearby Elements: no
Dimensions - Area: 0.02 m2; Volume: 0.056 m3
Other - Family: WE - 001 1586341: WE - 001 1586341; Family and Type: WE - 001 1586341: WE - 001 1586341; Type: WE - 001 1586341: WE - 001 1586341; Type Id: WE - 001 1586341: WE - 001 1586341
Phasing - Phase Created: New Construction

# IfcBuildingElementProxy: WE - 001, WE - 001 1588468:WE - 001 1588468:208997
In: -2. Story
Type - Classification: C1010110 Partitions - Brick, Solid (Uniformat); Material: Stucco - White Fine
Type - Identity Data - Assembly Code: C1010110; Assembly Description: Partitions - Brick, Solid; Type Name: WE - 001 1588468
Type - Other - Category: Generic Models; Family Name: WE - 001 1588468
Type - Pset_BuildingElementProxyCommon - Reference: WE - 001 1588468
Type - Pset_ProductRequirements - Category: Generic Models
Type - Pset_QuantityTakeOff - Reference: WE - 001 1588468
Pset_BuildingElementProxyCommon - sets with these values: 2
Constraints - Moves With Nearby Elements: no
Dimensions - Area: 0.02 m2; Volume: 0.0542 m3
Other - Family: WE - 001 1588468: WE - 001 1588468; Family and Type: WE - 001 1588468: WE - 001 1588468; Type: WE - 001 1588468: WE - 001 1588468; Type Id: WE - 001 1588468: WE - 001 1588468
Phasing - Phase Created: New Construction

# IfcDoor: DOO - 002, DOO - 002 1459265 1459265:DOO - 002 1459265 1459265:236032
In: -2. Story
Type - OperationType: DOUBLE_DOOR_SINGLE_SWING; ParameterTakesPrecedence: no; Sizeable: no; Classification: C1020110 Interior Doors - Metal (Uniformat); Material: Paint - Titanium White, Glass - Clear Fast
Type - DOO - 002 1459265 1459265:DOO - 002 1459265 1459265:236032 - PanelOperation: SWINGING
Type - Analytical Properties - Analytic Construction: <None>
Type - Identity Data - Assembly Code: C1020110; Assembly Description: Interior Doors - Metal; Type Mark: 25; Type Name: DOO - 002 1459265 1459265
Type - Other - Category: Doors; Family Name: DOO - 002 1459265 1459265
OverallHeight: 0 mm; OverallWidth: 1800 mm
Pset_DoorCommon - IsExternal: no; ThermalTransmittance: 0 kg/K/s3; Reference: DOO - 002 1459265 1459265; GlazingAreaFraction: 2.38157
Pset_ProductRequirements - Category: Doors
Pset_QuantityTakeOff - Reference: DOO - 002 1459265 1459265
BaseQuantities - Area: 5.00753 m2
Constraints - Moves With Nearby Elements: no; Level: Level: -2. Story
Dimensions - Area: 5.00753 m2; Volume: 0.0832236 m3
Identity Data - Mark: 6
Other - Family: DOO - 002 1459265 1459265: DOO - 002 1459265 1459265; Family and Type: DOO - 002 1459265 1459265: DOO - 002 1459265 1459265; Type: DOO - 002 1459265 1459265: DOO - 002 1459265 1459265; Type Id: DOO - 002 1459265 1459265: DOO - 002 1459265 1459265
Phasing - Phase Created: New Construction

# IfcDoor: DOO - 002, DOO - 002 1459265 2:DOO - 002 1459265 2:236065
In: -2. Story
Type - OperationType: DOUBLE_DOOR_SINGLE_SWING; ParameterTakesPrecedence: no; Sizeable: no; Classification: C1020110 Interior Doors - Metal (Uniformat); Material: Paint - Titanium White, Glass - Clear Fast
Type - DOO - 002 1459265 2:DOO - 002 1459265 2:236065 - PanelOperation: SWINGING
Type - Analytical Properties - Analytic Construction: <None>
Type - Identity Data - Assembly Code: C1020110; Assembly Description: Interior Doors - Metal; Type Mark: 26; Type Name: DOO - 002 1459265 2
Type - Other - Category: Doors; Family Name: DOO - 002 1459265 2
OverallHeight: 0 mm; OverallWidth: 1800 mm
Pset_DoorCommon - IsExternal: no; ThermalTransmittance: 0 kg/K/s3; Reference: DOO - 002 1459265 2; GlazingAreaFraction: 2.38157
Pset_ProductRequirements - Category: Doors
Pset_QuantityTakeOff - Reference: DOO - 002 1459265 2
BaseQuantities - Area: 5.00753 m2
Constraints - Moves With Nearby Elements: no; Level: Level: -2. Story
Dimensions - Area: 5.00753 m2; Volume: 0.0832236 m3
Identity Data - Mark: 7
Other - Family: DOO - 002 1459265 2: DOO - 002 1459265 2; Family and Type: DOO - 002 1459265 2: DOO - 002 1459265 2; Type: DOO - 002 1459265 2: DOO - 002 1459265 2; Type Id: DOO - 002 1459265 2: DOO - 002 1459265 2
Phasing - Phase Created: New Construction

# IfcDoor: DOO - 002, DOO - 002 1459265 3:DOO - 002 1459265 3:236083
In: -2. Story
Type - OperationType: DOUBLE_DOOR_SINGLE_SWING; ParameterTakesPrecedence: no; Sizeable: no; Classification: C1020110 Interior Doors - Metal (Uniformat); Material: Paint - Titanium White, Glass - Clear Fast
Type - DOO - 002 1459265 3:DOO - 002 1459265 3:236083 - PanelOperation: SWINGING
Type - Analytical Properties - Analytic Construction: <None>
Type - Identity Data - Assembly Code: C1020110; Assembly Description: Interior Doors - Metal; Type Mark: 27; Type Name: DOO - 002 1459265 3
Type - Other - Category: Doors; Family Name: DOO - 002 1459265 3
OverallHeight: 0 mm; OverallWidth: 1800 mm
Pset_DoorCommon - IsExternal: no; ThermalTransmittance: 0 kg/K/s3; Reference: DOO - 002 1459265 3; GlazingAreaFraction: 2.38157
Pset_ProductRequirements - Category: Doors
Pset_QuantityTakeOff - Reference: DOO - 002 1459265 3
BaseQuantities - Area: 5.00753 m2
Constraints - Moves With Nearby Elements: no; Level: Level: -2. Story
Dimensions - Area: 5.00753 m2; Volume: 0.0832236 m3
Identity Data - Mark: 8
Other - Family: DOO - 002 1459265 3: DOO - 002 1459265 3; Family and Type: DOO - 002 1459265 3: DOO - 002 1459265 3; Type: DOO - 002 1459265 3: DOO - 002 1459265 3; Type Id: DOO - 002 1459265 3: DOO - 002 1459265 3
Phasing - Phase Created: New Construction

# IfcDoor: DOO - 002, DOO - 002 1459265 4:DOO - 002 1459265 4:236101
In: -2. Story
Type - OperationType: DOUBLE_DOOR_SINGLE_SWING; ParameterTakesPrecedence: no; Sizeable: no; Classification: C1020110 Interior Doors - Metal (Uniformat); Material: Paint - Titanium White, Glass - Clear Fast
Type - DOO - 002 1459265 4:DOO - 002 1459265 4:236101 - PanelOperation: SWINGING
Type - Analytical Properties - Analytic Construction: <None>
Type - Identity Data - Assembly Code: C1020110; Assembly Description: Interior Doors - Metal; Type Mark: 28; Type Name: DOO - 002 1459265 4
Type - Other - Category: Doors; Family Name: DOO - 002 1459265 4
OverallHeight: 0 mm; OverallWidth: 1800 mm
Pset_DoorCommon - IsExternal: no; ThermalTransmittance: 0 kg/K/s3; Reference: DOO - 002 1459265 4; GlazingAreaFraction: 2.38157
Pset_ProductRequirements - Category: Doors
Pset_QuantityTakeOff - Reference: DOO - 002 1459265 4
BaseQuantities - Area: 5.00753 m2
Constraints - Moves With Nearby Elements: no; Level: Level: -2. Story
Dimensions - Area: 5.00753 m2; Volume: 0.0832236 m3
Identity Data - Mark: 9
Other - Family: DOO - 002 1459265 4: DOO - 002 1459265 4; Family and Type: DOO - 002 1459265 4: DOO - 002 1459265 4; Type: DOO - 002 1459265 4: DOO - 002 1459265 4; Type Id: DOO - 002 1459265 4: DOO - 002 1459265 4
Phasing - Phase Created: New Construction

# IfcDoor: DOO - 003, DOO - 003 1463877:DOO - 003 1463877:202880
In: -2. Story
Type - ParameterTakesPrecedence: no; Sizeable: no; Classification: C1020110 Interior Doors - Metal (Uniformat); Material: Metal - Stainless Steel
Type - Analytical Properties - Analytic Construction: <None>
Type - Identity Data - Assembly Code: C1020110; Assembly Description: Interior Doors - Metal; Type Mark: 22; Type Name: DOO - 003 1463877
Type - Other - Category: Doors; Family Name: DOO - 003 1463877
OverallHeight: 2137 mm; OverallWidth: 1574 mm
Pset_DoorCommon - IsExternal: no; Reference: DOO - 003 1463877; ThermalTransmittance: 0 kg/K/s3; GlazingAreaFraction: 0
Pset_ProductRequirements - Category: Doors
Pset_QuantityTakeOff - Reference: DOO - 003 1463877
BaseQuantities - Area: 4.90041 m2
Constraints - Moves With Nearby Elements: no
Dimensions - Area: 4.90041 m2; Volume: 0.153781 m3
Identity Data - Mark: 3
Other - Family: DOO - 003 1463877: DOO - 003 1463877; Family and Type: DOO - 003 1463877: DOO - 003 1463877; Type: DOO - 003 1463877: DOO - 003 1463877; Type Id: DOO - 003 1463877: DOO - 003 1463877
Phasing - Phase Created: New Construction

# IfcDoor: DOO - 003, DOO - 003 1465537:DOO - 003 1465537:204000
In: -2. Story
Type - ParameterTakesPrecedence: no; Sizeable: no; Classification: C1020110 Interior Doors - Metal (Uniformat); Material: Metal - Stainless Steel
Type - Analytical Properties - Analytic Construction: <None>
Type - Identity Data - Assembly Code: C1020110; Assembly Description: Interior Doors - Metal; Type Mark: 23; Type Name: DOO - 003 1465537
Type - Other - Category: Doors; Family Name: DOO - 003 1465537
OverallHeight: 2137 mm; OverallWidth: 1574 mm
Pset_DoorCommon - IsExternal: no; ThermalTransmittance: 0 kg/K/s3; Reference: DOO - 003 1465537; GlazingAreaFraction: 0
Pset_ProductRequirements - Category: Doors
Pset_QuantityTakeOff - Reference: DOO - 003 1465537
BaseQuantities - Area: 4.90041 m2
Constraints - Moves With Nearby Elements: no
Dimensions - Area: 4.90041 m2; Volume: 0.153781 m3
Identity Data - Mark: 5
Other - Family: DOO - 003 1465537: DOO - 003 1465537; Family and Type: DOO - 003 1465537: DOO - 003 1465537; Type: DOO - 003 1465537: DOO - 003 1465537; Type Id: DOO - 003 1465537: DOO - 003 1465537
Phasing - Phase Created: New Construction

# IfcFlowTerminal: FU - 006 1500655:FU - 006 1500655, FU - 006 1500655:FU - 006 1500655:204688
In: -2. Story
Classification: E2020200 Furniture & Accessories (Uniformat); Material: Metal - Stainless Steel, Metal - Zinc, Green1, Ceramic - Porcelain, Plastic - Laminate, Paint - Titanium White
Pset_DistributionFlowElementCommon - Reference: FU - 006 1500655; sets with these values: 2
Pset_ProductRequirements - Category: Plumbing Fixtures
Constraints - Moves With Nearby Elements: no
Dimensions - Area: 6.02424 m2; Volume: 0.242798 m3
Identity Data - Mark: 4
Other - Category: Plumbing Fixtures; Family: FU - 006 1500655: FU - 006 1500655; Family and Type: FU - 006 1500655: FU - 006 1500655; Type: FU - 006 1500655: FU - 006 1500655; Type Id: FU - 006 1500655: FU - 006 1500655
Phasing - Phase Created: New Construction
Other(Type) - Category: Plumbing Fixtures; Family Name: FU - 006 1500655
Identity Data(Type) - Assembly Code: E2020200; Assembly Description: Furniture & Accessories; Type Name: FU - 006 1500655

# IfcFlowTerminal: FU - 006 1500904:FU - 006 1500904, FU - 006 1500904:FU - 006 1500904:204695
In: -2. Story
Classification: E2020200 Furniture & Accessories (Uniformat); Material: Metal - Stainless Steel, Metal - Zinc, Green1, Ceramic - Porcelain, Plastic - Laminate, Paint - Titanium White
Pset_DistributionFlowElementCommon - Reference: FU - 006 1500904; sets with these values: 2
Pset_ProductRequirements - Category: Plumbing Fixtures
Constraints - Moves With Nearby Elements: no
Dimensions - Area: 6.02424 m2; Volume: 0.242798 m3
Identity Data - Mark: 6
Other - Category: Plumbing Fixtures; Family: FU - 006 1500904: FU - 006 1500904; Family and Type: FU - 006 1500904: FU - 006 1500904; Type: FU - 006 1500904: FU - 006 1500904; Type Id: FU - 006 1500904: FU - 006 1500904
Phasing - Phase Created: New Construction
Other(Type) - Category: Plumbing Fixtures; Family Name: FU - 006 1500904
Identity Data(Type) - Assembly Code: E2020200; Assembly Description: Furniture & Accessories; Type Name: FU - 006 1500904

# IfcFlowTerminal: FU - 006 1501144:FU - 006 1501144, FU - 006 1501144:FU - 006 1501144:204702
In: -2. Story
Classification: E2020200 Furniture & Accessories (Uniformat); Material: Metal - Stainless Steel, Metal - Zinc, Green1, Ceramic - Porcelain, Plastic - Laminate, Paint - Titanium White
Pset_DistributionFlowElementCommon - Reference: FU - 006 1501144; sets with these values: 2
Pset_ProductRequirements - Category: Plumbing Fixtures
Constraints - Moves With Nearby Elements: no
Dimensions - Area: 6.02424 m2; Volume: 0.242798 m3
Identity Data - Mark: 8
Other - Category: Plumbing Fixtures; Family: FU - 006 1501144: FU - 006 1501144; Family and Type: FU - 006 1501144: FU - 006 1501144; Type: FU - 006 1501144: FU - 006 1501144; Type Id: FU - 006 1501144: FU - 006 1501144
Phasing - Phase Created: New Construction
Other(Type) - Category: Plumbing Fixtures; Family Name: FU - 006 1501144
Identity Data(Type) - Assembly Code: E2020200; Assembly Description: Furniture & Accessories; Type Name: FU - 006 1501144

# IfcFlowTerminal: FU - 006 1507802:FU - 006 1507802, FU - 006 1507802:FU - 006 1507802:204846
In: -2. Story
Classification: E2020200 Furniture & Accessories (Uniformat); Material: Metal - Stainless Steel, Metal - Zinc, Green1, Ceramic - Porcelain, Plastic - Laminate, Paint - Titanium White
Pset_DistributionFlowElementCommon - Reference: FU - 006 1507802; sets with these values: 2
Pset_ProductRequirements - Category: Plumbing Fixtures
Constraints - Moves With Nearby Elements: no
Dimensions - Area: 5.04237 m2; Volume: 0.228026 m3
Identity Data - Mark: 10
Other - Category: Plumbing Fixtures; Family: FU - 006 1507802: FU - 006 1507802; Family and Type: FU - 006 1507802: FU - 006 1507802; Type: FU - 006 1507802: FU - 006 1507802; Type Id: FU - 006 1507802: FU - 006 1507802
Phasing - Phase Created: New Construction
Other(Type) - Category: Plumbing Fixtures; Family Name: FU - 006 1507802
Identity Data(Type) - Assembly Code: E2020200; Assembly Description: Furniture & Accessories; Type Name: FU - 006 1507802

# IfcFlowTerminal: FU - 006 1520115:FU - 006 1520115, FU - 006 1520115:FU - 006 1520115:205850
In: -2. Story
Classification: E2020200 Furniture & Accessories (Uniformat); Material: Metal - Stainless Steel, Metal - Zinc, Green1
Pset_DistributionFlowElementCommon - Reference: FU - 006 1520115; sets with these values: 2
Pset_ProductRequirements - Category: Plumbing Fixtures
Constraints - Moves With Nearby Elements: no
Dimensions - Area: 5.66176 m2; Volume: 0.139003 m3
Identity Data - Mark: 16
Other - Category: Plumbing Fixtures; Family: FU - 006 1520115: FU - 006 1520115; Family and Type: FU - 006 1520115: FU - 006 1520115; Type: FU - 006 1520115: FU - 006 1520115; Type Id: FU - 006 1520115: FU - 006 1520115
Phasing - Phase Created: New Construction
Other(Type) - Category: Plumbing Fixtures; Family Name: FU - 006 1520115
Identity Data(Type) - Assembly Code: E2020200; Assembly Description: Furniture & Accessories; Type Name: FU - 006 1520115

# IfcFlowTerminal: FU - 006 1522037:FU - 006 1522037, FU - 006 1522037:FU - 006 1522037:206112
In: -2. Story
Classification: E2020200 Furniture & Accessories (Uniformat); Material: Metal - Stainless Steel, Metal - Zinc, Green1
Pset_DistributionFlowElementCommon - Reference: FU - 006 1522037; sets with these values: 2
Pset_ProductRequirements - Category: Plumbing Fixtures
Constraints - Moves With Nearby Elements: no
Dimensions - Area: 5.66176 m2; Volume: 0.139003 m3
Identity Data - Mark: 18
Other - Category: Plumbing Fixtures; Family: FU - 006 1522037: FU - 006 1522037; Family and Type: FU - 006 1522037: FU - 006 1522037; Type: FU - 006 1522037: FU - 006 1522037; Type Id: FU - 006 1522037: FU - 006 1522037
Phasing - Phase Created: New Construction
Other(Type) - Category: Plumbing Fixtures; Family Name: FU - 006 1522037
Identity Data(Type) - Assembly Code: E2020200; Assembly Description: Furniture & Accessories; Type Name: FU - 006 1522037

# IfcFlowTerminal: FU - 006 1523931:FU - 006 1523931, FU - 006 1523931:FU - 006 1523931:206119
In: -2. Story
Classification: E2020200 Furniture & Accessories (Uniformat); Material: Metal - Stainless Steel, Metal - Zinc, Green1
Pset_DistributionFlowElementCommon - Reference: FU - 006 1523931; sets with these values: 2
Pset_ProductRequirements - Category: Plumbing Fixtures
Constraints - Moves With Nearby Elements: no
Dimensions - Area: 8.44144 m2; Volume: 0.206402 m3
Identity Data - Mark: 20
Other - Category: Plumbing Fixtures; Family: FU - 006 1523931: FU - 006 1523931; Family and Type: FU - 006 1523931: FU - 006 1523931; Type: FU - 006 1523931: FU - 006 1523931; Type Id: FU - 006 1523931: FU - 006 1523931
Phasing - Phase Created: New Construction
Other(Type) - Category: Plumbing Fixtures; Family Name: FU - 006 1523931
Identity Data(Type) - Assembly Code: E2020200; Assembly Description: Furniture & Accessories; Type Name: FU - 006 1523931

# IfcFlowTerminal: FU - 006 1532721:FU - 006 1532721, FU - 006 1532721:FU - 006 1532721:207036
In: -2. Story
Classification: E2020200 Furniture & Accessories (Uniformat); Material: Metal - Stainless Steel, Metal - Zinc, Green1, Ceramic - Porcelain, Plastic - Laminate, Paint - Titanium White
Pset_DistributionFlowElementCommon - Reference: FU - 006 1532721; sets with these values: 2
Pset_ProductRequirements - Category: Plumbing Fixtures
Constraints - Moves With Nearby Elements: no
Dimensions - Area: 6.02424 m2; Volume: 0.239022 m3
Identity Data - Mark: 22
Other - Category: Plumbing Fixtures; Family: FU - 006 1532721: FU - 006 1532721; Family and Type: FU - 006 1532721: FU - 006 1532721; Type: FU - 006 1532721: FU - 006 1532721; Type Id: FU - 006 1532721: FU - 006 1532721
Phasing - Phase Created: New Construction
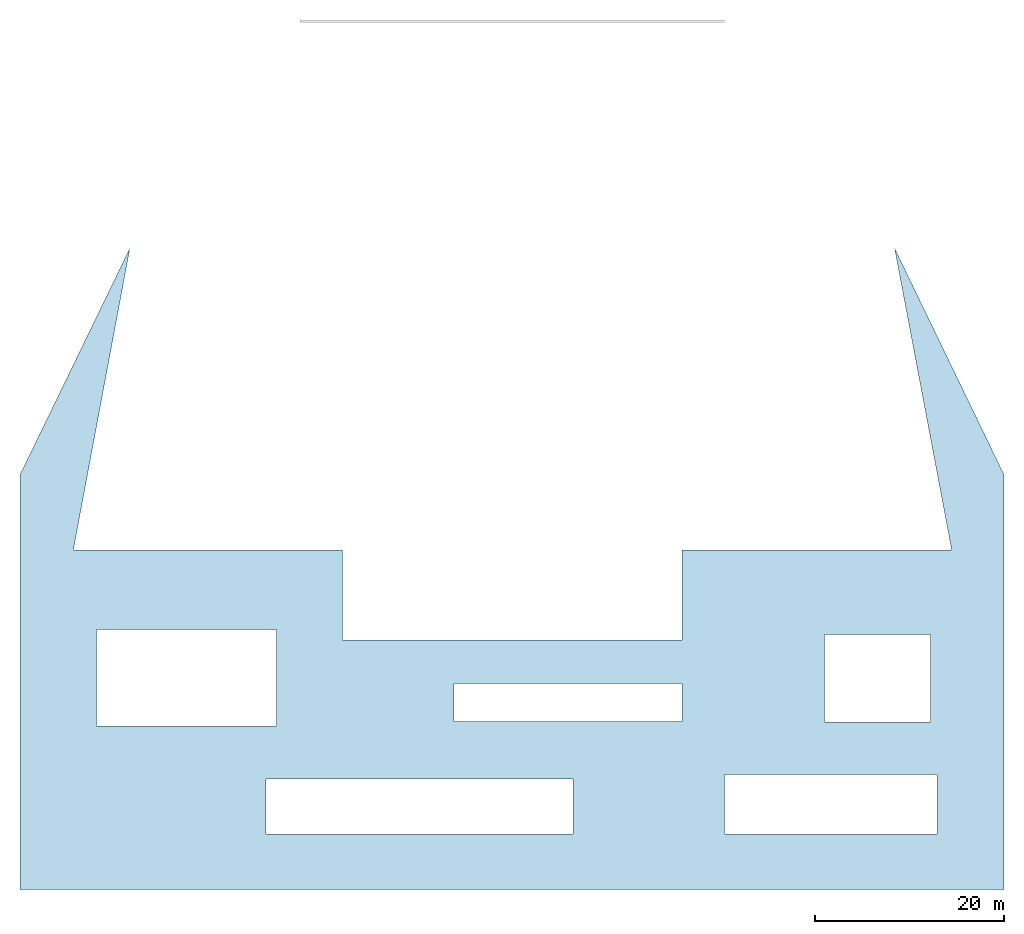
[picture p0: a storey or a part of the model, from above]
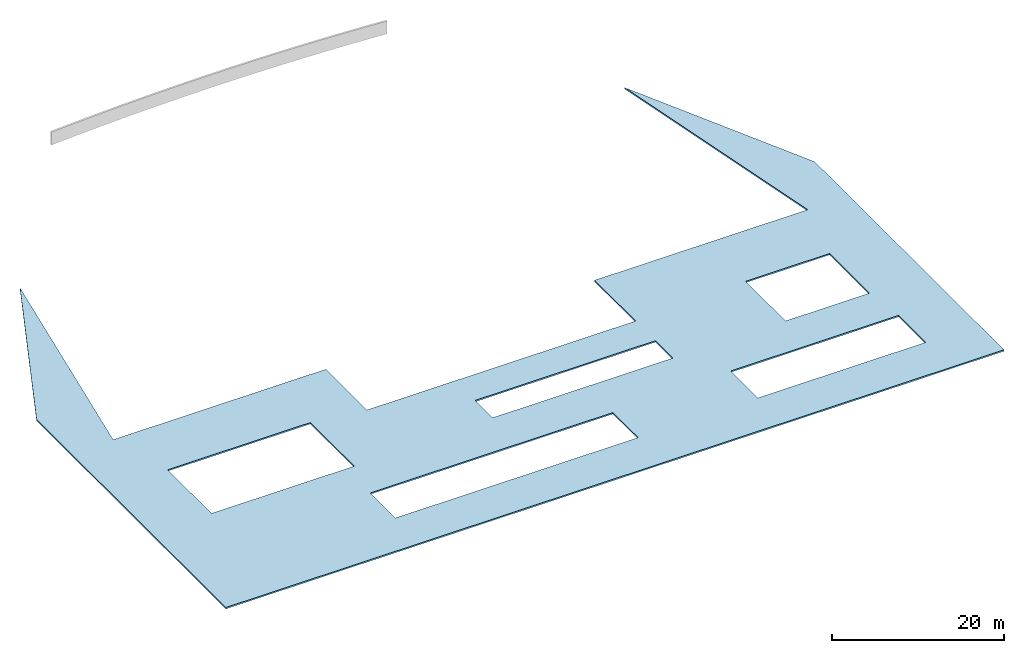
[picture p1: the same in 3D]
Properties of the parts of a building model (IFC2X3), part 2 of 4

# IfcFlowTerminal: FU - 006 1532721:FU - 006 1532721, FU - 006 1532721:FU - 006 1532721:207036
Other(Type) - Category: Plumbing Fixtures; Family Name: FU - 006 1532721
Identity Data(Type) - Assembly Code: E2020200; Assembly Description: Furniture & Accessories; Type Name: FU - 006 1532721

# IfcFlowTerminal: FU - 006 1532970:FU - 006 1532970, FU - 006 1532970:FU - 006 1532970:207043
In: -2. Story
Classification: E2020200 Furniture & Accessories (Uniformat); Material: Metal - Stainless Steel, Metal - Zinc, Green1, Ceramic - Porcelain, Plastic - Laminate, Paint - Titanium White
Pset_DistributionFlowElementCommon - Reference: FU - 006 1532970; sets with these values: 2
Pset_ProductRequirements - Category: Plumbing Fixtures
Constraints - Moves With Nearby Elements: no
Dimensions - Area: 6.02424 m2; Volume: 0.239022 m3
Identity Data - Mark: 24
Other - Category: Plumbing Fixtures; Family: FU - 006 1532970: FU - 006 1532970; Family and Type: FU - 006 1532970: FU - 006 1532970; Type: FU - 006 1532970: FU - 006 1532970; Type Id: FU - 006 1532970: FU - 006 1532970
Phasing - Phase Created: New Construction
Other(Type) - Category: Plumbing Fixtures; Family Name: FU - 006 1532970
Identity Data(Type) - Assembly Code: E2020200; Assembly Description: Furniture & Accessories; Type Name: FU - 006 1532970

# IfcFlowTerminal: FU - 006 1533210:FU - 006 1533210, FU - 006 1533210:FU - 006 1533210:207050
In: -2. Story
Classification: E2020200 Furniture & Accessories (Uniformat); Material: Metal - Stainless Steel, Metal - Zinc, Green1, Ceramic - Porcelain, Plastic - Laminate, Paint - Titanium White
Pset_DistributionFlowElementCommon - Reference: FU - 006 1533210; sets with these values: 2
Pset_ProductRequirements - Category: Plumbing Fixtures
Constraints - Moves With Nearby Elements: no
Dimensions - Area: 6.02424 m2; Volume: 0.239022 m3
Identity Data - Mark: 26
Other - Category: Plumbing Fixtures; Family: FU - 006 1533210: FU - 006 1533210; Family and Type: FU - 006 1533210: FU - 006 1533210; Type: FU - 006 1533210: FU - 006 1533210; Type Id: FU - 006 1533210: FU - 006 1533210
Phasing - Phase Created: New Construction
Other(Type) - Category: Plumbing Fixtures; Family Name: FU - 006 1533210
Identity Data(Type) - Assembly Code: E2020200; Assembly Description: Furniture & Accessories; Type Name: FU - 006 1533210

# IfcFlowTerminal: FU - 006 1533450:FU - 006 1533450, FU - 006 1533450:FU - 006 1533450:207057
In: -2. Story
Classification: E2020200 Furniture & Accessories (Uniformat); Material: Metal - Stainless Steel, Metal - Zinc, Green1, Ceramic - Porcelain, Plastic - Laminate, Paint - Titanium White
Pset_DistributionFlowElementCommon - Reference: FU - 006 1533450; sets with these values: 2
Pset_ProductRequirements - Category: Plumbing Fixtures
Constraints - Moves With Nearby Elements: no
Dimensions - Area: 6.02424 m2; Volume: 0.239022 m3
Identity Data - Mark: 28
Other - Category: Plumbing Fixtures; Family: FU - 006 1533450: FU - 006 1533450; Family and Type: FU - 006 1533450: FU - 006 1533450; Type: FU - 006 1533450: FU - 006 1533450; Type Id: FU - 006 1533450: FU - 006 1533450
Phasing - Phase Created: New Construction
Other(Type) - Category: Plumbing Fixtures; Family Name: FU - 006 1533450
Identity Data(Type) - Assembly Code: E2020200; Assembly Description: Furniture & Accessories; Type Name: FU - 006 1533450

# IfcFlowTerminal: FU - 006 1538923:FU - 006 1538923, FU - 006 1538923:FU - 006 1538923:207064
In: -2. Story
Classification: E2020200 Furniture & Accessories (Uniformat); Material: Metal - Stainless Steel, Metal - Zinc, Green1, Ceramic - Porcelain, Plastic - Laminate, Paint - Titanium White
Pset_DistributionFlowElementCommon - Reference: FU - 006 1538923; sets with these values: 2
Pset_ProductRequirements - Category: Plumbing Fixtures
Constraints - Moves With Nearby Elements: no
Dimensions - Area: 3.59487 m2; Volume: 0.180272 m3
Identity Data - Mark: 30
Other - Category: Plumbing Fixtures; Family: FU - 006 1538923: FU - 006 1538923; Family and Type: FU - 006 1538923: FU - 006 1538923; Type: FU - 006 1538923: FU - 006 1538923; Type Id: FU - 006 1538923: FU - 006 1538923
Phasing - Phase Created: New Construction
Other(Type) - Category: Plumbing Fixtures; Family Name: FU - 006 1538923
Identity Data(Type) - Assembly Code: E2020200; Assembly Description: Furniture & Accessories; Type Name: FU - 006 1538923

# IfcFlowTerminal: FU - 006 1549778:FU - 006 1549778, FU - 006 1549778:FU - 006 1549778:207417
In: -2. Story
Classification: E2020200 Furniture & Accessories (Uniformat); Material: Metal - Stainless Steel, Metal - Zinc, Green1
Pset_DistributionFlowElementCommon - Reference: FU - 006 1549778; sets with these values: 2
Pset_ProductRequirements - Category: Plumbing Fixtures
Constraints - Moves With Nearby Elements: no
Dimensions - Area: 5.66176 m2; Volume: 0.138329 m3
Identity Data - Mark: 36
Other - Category: Plumbing Fixtures; Family: FU - 006 1549778: FU - 006 1549778; Family and Type: FU - 006 1549778: FU - 006 1549778; Type: FU - 006 1549778: FU - 006 1549778; Type Id: FU - 006 1549778: FU - 006 1549778
Phasing - Phase Created: New Construction
Other(Type) - Category: Plumbing Fixtures; Family Name: FU - 006 1549778
Identity Data(Type) - Assembly Code: E2020200; Assembly Description: Furniture & Accessories; Type Name: FU - 006 1549778

# IfcFlowTerminal: FU - 006 1552313:FU - 006 1552313, FU - 006 1552313:FU - 006 1552313:207679
In: -2. Story
Classification: E2020200 Furniture & Accessories (Uniformat); Material: Metal - Stainless Steel, Metal - Zinc, Green1
Pset_DistributionFlowElementCommon - Reference: FU - 006 1552313; sets with these values: 2
Pset_ProductRequirements - Category: Plumbing Fixtures
Constraints - Moves With Nearby Elements: no
Dimensions - Area: 5.66176 m2; Volume: 0.138329 m3
Identity Data - Mark: 38
Other - Category: Plumbing Fixtures; Family: FU - 006 1552313: FU - 006 1552313; Family and Type: FU - 006 1552313: FU - 006 1552313; Type: FU - 006 1552313: FU - 006 1552313; Type Id: FU - 006 1552313: FU - 006 1552313
Phasing - Phase Created: New Construction
Other(Type) - Category: Plumbing Fixtures; Family Name: FU - 006 1552313
Identity Data(Type) - Assembly Code: E2020200; Assembly Description: Furniture & Accessories; Type Name: FU - 006 1552313

# IfcFlowTerminal: FU - 006 1554356:FU - 006 1554356, FU - 006 1554356:FU - 006 1554356:207771
In: -2. Story
Classification: E2020200 Furniture & Accessories (Uniformat); Material: Metal - Stainless Steel, Metal - Zinc, Green1
Pset_DistributionFlowElementCommon - Reference: FU - 006 1554356; sets with these values: 2
Pset_ProductRequirements - Category: Plumbing Fixtures
Constraints - Moves With Nearby Elements: no
Dimensions - Area: 8.44144 m2; Volume: 0.205729 m3
Identity Data - Mark: 40
Other - Category: Plumbing Fixtures; Family: FU - 006 1554356: FU - 006 1554356; Family and Type: FU - 006 1554356: FU - 006 1554356; Type: FU - 006 1554356: FU - 006 1554356; Type Id: FU - 006 1554356: FU - 006 1554356
Phasing - Phase Created: New Construction
Other(Type) - Category: Plumbing Fixtures; Family Name: FU - 006 1554356
Identity Data(Type) - Assembly Code: E2020200; Assembly Description: Furniture & Accessories; Type Name: FU - 006 1554356

# IfcFlowTerminal: FU - 006 1562444:FU - 006 1562444, FU - 006 1562444:FU - 006 1562444:208393
In: -2. Story
Classification: E2020200 Furniture & Accessories (Uniformat); Material: Metal - Stainless Steel, Metal - Zinc, Green1, Ceramic - Porcelain, Plastic - Laminate, Paint - Titanium White
Pset_DistributionFlowElementCommon - Reference: FU - 006 1562444; sets with these values: 2
Pset_ProductRequirements - Category: Plumbing Fixtures
Constraints - Moves With Nearby Elements: no
Dimensions - Area: 6.45674 m2; Volume: 0.25144 m3
Identity Data - Mark: 42
Other - Category: Plumbing Fixtures; Family: FU - 006 1562444: FU - 006 1562444; Family and Type: FU - 006 1562444: FU - 006 1562444; Type: FU - 006 1562444: FU - 006 1562444; Type Id: FU - 006 1562444: FU - 006 1562444
Phasing - Phase Created: New Construction
Other(Type) - Category: Plumbing Fixtures; Family Name: FU - 006 1562444
Identity Data(Type) - Assembly Code: E2020200; Assembly Description: Furniture & Accessories; Type Name: FU - 006 1562444

# IfcFlowTerminal: FU - 006 1570129:FU - 006 1570129, FU - 006 1570129:FU - 006 1570129:208533
In: -2. Story
Classification: E2020200 Furniture & Accessories (Uniformat); Material: Metal - Stainless Steel, Metal - Zinc, Green1
Other(Type) - Category: Plumbing Fixtures; Family Name: FU - 006 1570129
Identity Data(Type) - Assembly Code: E2020200; Assembly Description: Furniture & Accessories; Type Name: FU - 006 1570129
Pset_DistributionFlowElementCommon - Reference: FU - 006 1570129; sets with these values: 2
Pset_ProductRequirements - Category: Plumbing Fixtures
Constraints - Moves With Nearby Elements: no
Dimensions - Area: 2.53132 m2; Volume: 0.0610977 m3
Identity Data - Mark: 46
Other - Category: Plumbing Fixtures; Family: FU - 006 1570129: FU - 006 1570129; Family and Type: FU - 006 1570129: FU - 006 1570129; Type: FU - 006 1570129: FU - 006 1570129; Type Id: FU - 006 1570129: FU - 006 1570129
Phasing - Phase Created: New Construction

# IfcFlowTerminal: FU - 006 1582642:FU - 006 1582642, FU - 006 1582642:FU - 006 1582642:208809
In: -2. Story
Classification: E2020200 Furniture & Accessories (Uniformat); Material: Metal - Stainless Steel, Metal - Zinc, Green1, Ceramic - Porcelain, Plastic - Laminate, Paint - Titanium White
Other(Type) - Category: Plumbing Fixtures; Family Name: FU - 006 1582642
Identity Data(Type) - Assembly Code: E2020200; Assembly Description: Furniture & Accessories; Type Name: FU - 006 1582642
Pset_DistributionFlowElementCommon - Reference: FU - 006 1582642; sets with these values: 2
Pset_ProductRequirements - Category: Plumbing Fixtures
Constraints - Moves With Nearby Elements: no
Dimensions - Area: 8.45362 m2; Volume: 0.297772 m3
Identity Data - Mark: 48
Other - Category: Plumbing Fixtures; Family: FU - 006 1582642: FU - 006 1582642; Family and Type: FU - 006 1582642: FU - 006 1582642; Type: FU - 006 1582642: FU - 006 1582642; Type Id: FU - 006 1582642: FU - 006 1582642
Phasing - Phase Created: New Construction

# IfcFlowTerminal: FU - 006 1590549:FU - 006 1590549, FU - 006 1590549:FU - 006 1590549:209402
In: -2. Story
Classification: E2020200 Furniture & Accessories (Uniformat); Material: Metal - Stainless Steel, Metal - Zinc, Green1
Other(Type) - Category: Plumbing Fixtures; Family Name: FU - 006 1590549
Identity Data(Type) - Assembly Code: E2020200; Assembly Description: Furniture & Accessories; Type Name: FU - 006 1590549
Pset_DistributionFlowElementCommon - Reference: FU - 006 1590549; sets with these values: 2
Pset_ProductRequirements - Category: Plumbing Fixtures
Constraints - Moves With Nearby Elements: no
Dimensions - Area: 5.66176 m2; Volume: 0.138329 m3
Identity Data - Mark: 54
Other - Category: Plumbing Fixtures; Family: FU - 006 1590549: FU - 006 1590549; Family and Type: FU - 006 1590549: FU - 006 1590549; Type: FU - 006 1590549: FU - 006 1590549; Type Id: FU - 006 1590549: FU - 006 1590549
Phasing - Phase Created: New Construction

# IfcFlowTerminal: FU - 006 1591236:FU - 006 1591236, FU - 006 1591236:FU - 006 1591236:209664
In: -2. Story
Classification: E2020200 Furniture & Accessories (Uniformat); Material: Metal - Stainless Steel, Metal - Zinc, Green1
Other(Type) - Category: Plumbing Fixtures; Family Name: FU - 006 1591236
Identity Data(Type) - Assembly Code: E2020200; Assembly Description: Furniture & Accessories; Type Name: FU - 006 1591236
Pset_DistributionFlowElementCommon - Reference: FU - 006 1591236; sets with these values: 2
Pset_ProductRequirements - Category: Plumbing Fixtures
Constraints - Moves With Nearby Elements: no
Dimensions - Area: 5.66176 m2; Volume: 0.138329 m3
Identity Data - Mark: 56
Other - Category: Plumbing Fixtures; Family: FU - 006 1591236: FU - 006 1591236; Family and Type: FU - 006 1591236: FU - 006 1591236; Type: FU - 006 1591236: FU - 006 1591236; Type Id: FU - 006 1591236: FU - 006 1591236
Phasing - Phase Created: New Construction

# IfcFlowTerminal: FU - 006 1591625:FU - 006 1591625, FU - 006 1591625:FU - 006 1591625:209756
In: -2. Story
Classification: E2020200 Furniture & Accessories (Uniformat); Material: Metal - Stainless Steel, Metal - Zinc, Green1
Other(Type) - Category: Plumbing Fixtures; Family Name: FU - 006 1591625
Identity Data(Type) - Assembly Code: E2020200; Assembly Description: Furniture & Accessories; Type Name: FU - 006 1591625
Pset_DistributionFlowElementCommon - Reference: FU - 006 1591625; sets with these values: 2
Pset_ProductRequirements - Category: Plumbing Fixtures
Constraints - Moves With Nearby Elements: no
Dimensions - Area: 8.44144 m2; Volume: 0.205729 m3
Identity Data - Mark: 58
Other - Category: Plumbing Fixtures; Family: FU - 006 1591625: FU - 006 1591625; Family and Type: FU - 006 1591625: FU - 006 1591625; Type: FU - 006 1591625: FU - 006 1591625; Type Id: FU - 006 1591625: FU - 006 1591625
Phasing - Phase Created: New Construction

# IfcFlowTerminal: FU - 006 1595111:FU - 006 1595111, FU - 006 1595111:FU - 006 1595111:210673
In: -2. Story
Classification: E2020200 Furniture & Accessories (Uniformat); Material: Metal - Stainless Steel, Metal - Zinc, Green1, Ceramic - Porcelain, Plastic - Laminate, Paint - Titanium White
Other(Type) - Category: Plumbing Fixtures; Family Name: FU - 006 1595111
Identity Data(Type) - Assembly Code: E2020200; Assembly Description: Furniture & Accessories; Type Name: FU - 006 1595111
Pset_DistributionFlowElementCommon - Reference: FU - 006 1595111; sets with these values: 2
Pset_ProductRequirements - Category: Plumbing Fixtures
Constraints - Moves With Nearby Elements: no
Dimensions - Area: 6.02424 m2; Volume: 0.242798 m3
Identity Data - Mark: 60
Other - Category: Plumbing Fixtures; Family: FU - 006 1595111: FU - 006 1595111; Family and Type: FU - 006 1595111: FU - 006 1595111; Type: FU - 006 1595111: FU - 006 1595111; Type Id: FU - 006 1595111: FU - 006 1595111
Phasing - Phase Created: New Construction

# IfcFlowTerminal: FU - 006 1595351:FU - 006 1595351, FU - 006 1595351:FU - 006 1595351:210680
In: -2. Story
Classification: E2020200 Furniture & Accessories (Uniformat); Material: Metal - Stainless Steel, Metal - Zinc, Green1, Ceramic - Porcelain, Plastic - Laminate, Paint - Titanium White
Other(Type) - Category: Plumbing Fixtures; Family Name: FU - 006 1595351
Identity Data(Type) - Assembly Code: E2020200; Assembly Description: Furniture & Accessories; Type Name: FU - 006 1595351
Pset_DistributionFlowElementCommon - Reference: FU - 006 1595351; sets with these values: 2
Pset_ProductRequirements - Category: Plumbing Fixtures
Constraints - Moves With Nearby Elements: no
Dimensions - Area: 6.02424 m2; Volume: 0.242798 m3
Identity Data - Mark: 62
Other - Category: Plumbing Fixtures; Family: FU - 006 1595351: FU - 006 1595351; Family and Type: FU - 006 1595351: FU - 006 1595351; Type: FU - 006 1595351: FU - 006 1595351; Type Id: FU - 006 1595351: FU - 006 1595351
Phasing - Phase Created: New Construction

# IfcFlowTerminal: FU - 006 1595591:FU - 006 1595591, FU - 006 1595591:FU - 006 1595591:210687
In: -2. Story
Classification: E2020200 Furniture & Accessories (Uniformat); Material: Metal - Stainless Steel, Metal - Zinc, Green1, Ceramic - Porcelain, Plastic - Laminate, Paint - Titanium White
Other(Type) - Category: Plumbing Fixtures; Family Name: FU - 006 1595591
Identity Data(Type) - Assembly Code: E2020200; Assembly Description: Furniture & Accessories; Type Name: FU - 006 1595591
Pset_DistributionFlowElementCommon - Reference: FU - 006 1595591; sets with these values: 2
Pset_ProductRequirements - Category: Plumbing Fixtures
Constraints - Moves With Nearby Elements: no
Dimensions - Area: 6.02424 m2; Volume: 0.242798 m3
Identity Data - Mark: 64
Other - Category: Plumbing Fixtures; Family: FU - 006 1595591: FU - 006 1595591; Family and Type: FU - 006 1595591: FU - 006 1595591; Type: FU - 006 1595591: FU - 006 1595591; Type Id: FU - 006 1595591: FU - 006 1595591
Phasing - Phase Created: New Construction

# IfcFlowTerminal: FU - 006 1595831:FU - 006 1595831, FU - 006 1595831:FU - 006 1595831:210694
In: -2. Story
Classification: E2020200 Furniture & Accessories (Uniformat); Material: Metal - Stainless Steel, Metal - Zinc, Green1, Ceramic - Porcelain, Plastic - Laminate, Paint - Titanium White
Other(Type) - Category: Plumbing Fixtures; Family Name: FU - 006 1595831
Identity Data(Type) - Assembly Code: E2020200; Assembly Description: Furniture & Accessories; Type Name: FU - 006 1595831
Pset_DistributionFlowElementCommon - Reference: FU - 006 1595831; sets with these values: 2
Pset_ProductRequirements - Category: Plumbing Fixtures
Constraints - Moves With Nearby Elements: no
Dimensions - Area: 6.02424 m2; Volume: 0.242798 m3
Identity Data - Mark: 66
Other - Category: Plumbing Fixtures; Family: FU - 006 1595831: FU - 006 1595831; Family and Type: FU - 006 1595831: FU - 006 1595831; Type: FU - 006 1595831: FU - 006 1595831; Type Id: FU - 006 1595831: FU - 006 1595831
Phasing - Phase Created: New Construction

# IfcFlowTerminal: FU - 006 1601304:FU - 006 1601304, FU - 006 1601304:FU - 006 1601304:210701
In: -2. Story
Classification: E2020200 Furniture & Accessories (Uniformat); Material: Metal - Stainless Steel, Metal - Zinc, Green1, Ceramic - Porcelain, Plastic - Laminate, Paint - Titanium White
Other(Type) - Category: Plumbing Fixtures; Family Name: FU - 006 1601304
Identity Data(Type) - Assembly Code: E2020200; Assembly Description: Furniture & Accessories; Type Name: FU - 006 1601304
Pset_DistributionFlowElementCommon - Reference: FU - 006 1601304; sets with these values: 2
Pset_ProductRequirements - Category: Plumbing Fixtures
Constraints - Moves With Nearby Elements: no
Dimensions - Area: 3.59487 m2; Volume: 0.184048 m3
Identity Data - Mark: 68
Other - Category: Plumbing Fixtures; Family: FU - 006 1601304: FU - 006 1601304; Family and Type: FU - 006 1601304: FU - 006 1601304; Type: FU - 006 1601304: FU - 006 1601304; Type Id: FU - 006 1601304: FU - 006 1601304
Phasing - Phase Created: New Construction

# IfcFlowTerminal: FU - 006 1603874:FU - 006 1603874, FU - 006 1603874:FU - 006 1603874:211054
In: -2. Story
Classification: E2020200 Furniture & Accessories (Uniformat); Material: Metal - Stainless Steel, Metal - Zinc, Green1
Other(Type) - Category: Plumbing Fixtures; Family Name: FU - 006 1603874
Identity Data(Type) - Assembly Code: E2020200; Assembly Description: Furniture & Accessories; Type Name: FU - 006 1603874
Pset_DistributionFlowElementCommon - Reference: FU - 006 1603874; sets with these values: 2
Pset_ProductRequirements - Category: Plumbing Fixtures
Constraints - Moves With Nearby Elements: no
Dimensions - Area: 5.66176 m2; Volume: 0.139003 m3
Identity Data - Mark: 74
Other - Category: Plumbing Fixtures; Family: FU - 006 1603874: FU - 006 1603874; Family and Type: FU - 006 1603874: FU - 006 1603874; Type: FU - 006 1603874: FU - 006 1603874; Type Id: FU - 006 1603874: FU - 006 1603874
Phasing - Phase Created: New Construction

# IfcFlowTerminal: FU - 006 1604561:FU - 006 1604561, FU - 006 1604561:FU - 006 1604561:211316
In: -2. Story
Classification: E2020200 Furniture & Accessories (Uniformat); Material: Metal - Stainless Steel, Metal - Zinc, Green1
Other(Type) - Category: Plumbing Fixtures; Family Name: FU - 006 1604561
Identity Data(Type) - Assembly Code: E2020200; Assembly Description: Furniture & Accessories; Type Name: FU - 006 1604561
Pset_DistributionFlowElementCommon - Reference: FU - 006 1604561; sets with these values: 2
Pset_ProductRequirements - Category: Plumbing Fixtures
Constraints - Moves With Nearby Elements: no
Dimensions - Area: 5.66176 m2; Volume: 0.139003 m3
Identity Data - Mark: 76
Other - Category: Plumbing Fixtures; Family: FU - 006 1604561: FU - 006 1604561; Family and Type: FU - 006 1604561: FU - 006 1604561; Type: FU - 006 1604561: FU - 006 1604561; Type Id: FU - 006 1604561: FU - 006 1604561
Phasing - Phase Created: New Construction

# IfcFlowTerminal: FU - 006 1604950:FU - 006 1604950, FU - 006 1604950:FU - 006 1604950:211408
In: -2. Story
Classification: E2020200 Furniture & Accessories (Uniformat); Material: Metal - Stainless Steel, Metal - Zinc, Green1
Other(Type) - Category: Plumbing Fixtures; Family Name: FU - 006 1604950
Identity Data(Type) - Assembly Code: E2020200; Assembly Description: Furniture & Accessories; Type Name: FU - 006 1604950
Pset_DistributionFlowElementCommon - Reference: FU - 006 1604950; sets with these values: 2
Pset_ProductRequirements - Category: Plumbing Fixtures
Constraints - Moves With Nearby Elements: no
Dimensions - Area: 8.44144 m2; Volume: 0.206402 m3
Identity Data - Mark: 78
Other - Category: Plumbing Fixtures; Family: FU - 006 1604950: FU - 006 1604950; Family and Type: FU - 006 1604950: FU - 006 1604950; Type: FU - 006 1604950: FU - 006 1604950; Type Id: FU - 006 1604950: FU - 006 1604950
Phasing - Phase Created: New Construction

# IfcFlowTerminal: FU - 006 1613029:FU - 006 1613029, FU - 006 1613029:FU - 006 1613029:212030
In: -2. Story
Classification: E2020200 Furniture & Accessories (Uniformat); Material: Metal - Stainless Steel, Metal - Zinc, Green1, Ceramic - Porcelain, Plastic - Laminate, Paint - Titanium White
Other(Type) - Category: Plumbing Fixtures; Family Name: FU - 006 1613029
Identity Data(Type) - Assembly Code: E2020200; Assembly Description: Furniture & Accessories; Type Name: FU - 006 1613029
Pset_DistributionFlowElementCommon - Reference: FU - 006 1613029; sets with these values: 2
Pset_ProductRequirements - Category: Plumbing Fixtures
Constraints - Moves With Nearby Elements: no
Dimensions - Area: 6.45674 m2; Volume: 0.255938 m3
Identity Data - Mark: 80
Other - Category: Plumbing Fixtures; Family: FU - 006 1613029: FU - 006 1613029; Family and Type: FU - 006 1613029: FU - 006 1613029; Type: FU - 006 1613029: FU - 006 1613029; Type Id: FU - 006 1613029: FU - 006 1613029
Phasing - Phase Created: New Construction

# IfcFlowTerminal: FU - 006 1620714:FU - 006 1620714, FU - 006 1620714:FU - 006 1620714:212170
In: -2. Story
Classification: E2020200 Furniture & Accessories (Uniformat); Material: Metal - Stainless Steel, Metal - Zinc, Green1
Other(Type) - Category: Plumbing Fixtures; Family Name: FU - 006 1620714
Identity Data(Type) - Assembly Code: E2020200; Assembly Description: Furniture & Accessories; Type Name: FU - 006 1620714
Pset_DistributionFlowElementCommon - Reference: FU - 006 1620714; sets with these values: 2
Pset_ProductRequirements - Category: Plumbing Fixtures
Constraints - Moves With Nearby Elements: no
Dimensions - Area: 2.53132 m2; Volume: 0.0617472 m3
Identity Data - Mark: 84
Other - Category: Plumbing Fixtures; Family: FU - 006 1620714: FU - 006 1620714; Family and Type: FU - 006 1620714: FU - 006 1620714; Type: FU - 006 1620714: FU - 006 1620714; Type Id: FU - 006 1620714: FU - 006 1620714
Phasing - Phase Created: New Construction

# IfcFlowTerminal: FU - 006:FU - 006, FU - 006:FU - 006:204512
In: -2. Story
Classification: E2020200 Furniture & Accessories (Uniformat); Material: Metal - Stainless Steel, Metal - Zinc, Green1, Ceramic - Porcelain, Plastic - Laminate, Paint - Titanium White
Pset_DistributionFlowElementCommon - Reference: FU - 006; sets with these values: 2
Pset_ProductRequirements - Category: Plumbing Fixtures
Constraints - Moves With Nearby Elements: no
Dimensions - Area: 8.45362 m2; Volume: 0.301548 m3
Identity Data - Mark: 2
Other - Category: Plumbing Fixtures; Family: FU - 006: FU - 006; Family and Type: FU - 006: FU - 006; Type: FU - 006: FU - 006; Type Id: FU - 006: FU - 006
Phasing - Phase Created: New Construction
Other(Type) - Category: Plumbing Fixtures; Family Name: FU - 006
Identity Data(Type) - Assembly Code: E2020200; Assembly Description: Furniture & Accessories; Type Name: FU - 006

# IfcFlowTerminal: FU - 007 1513821:FU - 007 1513821, FU - 007 1513821:FU - 007 1513821:204937
In: -2. Story
Classification: E2020200 Furniture & Accessories (Uniformat); Material: Stone - Marble Carrara White, Ceramic - Porcelain, Metal - Stainless Steel
Pset_DistributionFlowElementCommon - Reference: FU - 007 1513821; sets with these values: 2
Pset_ProductRequirements - Category: Plumbing Fixtures
Constraints - Moves With Nearby Elements: no
Dimensions - Area: 2.03682 m2; Volume: 0.00570302 m3
Identity Data - Mark: 12
Other - Category: Plumbing Fixtures; Family: FU - 007 1513821: FU - 007 1513821; Family and Type: FU - 007 1513821: FU - 007 1513821; Type: FU - 007 1513821: FU - 007 1513821; Type Id: FU - 007 1513821: FU - 007 1513821
Phasing - Phase Created: New Construction
Other(Type) - Category: Plumbing Fixtures; Family Name: FU - 007 1513821
Identity Data(Type) - Assembly Code: E2020200; Assembly Description: Furniture & Accessories; Type Name: FU - 007 1513821

# IfcFlowTerminal: FU - 007 1514360:FU - 007 1514360, FU - 007 1514360:FU - 007 1514360:205273
In: -2. Story
Classification: E2020200 Furniture & Accessories (Uniformat); Material: Stone - Marble Carrara White, Ceramic - Porcelain, Metal - Stainless Steel
Pset_DistributionFlowElementCommon - Reference: FU - 007 1514360; sets with these values: 2
Pset_ProductRequirements - Category: Plumbing Fixtures
Constraints - Moves With Nearby Elements: no
Dimensions - Area: 2.03682 m2; Volume: 0.00570302 m3
Identity Data - Mark: 14
Other - Category: Plumbing Fixtures; Family: FU - 007 1514360: FU - 007 1514360; Family and Type: FU - 007 1514360: FU - 007 1514360; Type: FU - 007 1514360: FU - 007 1514360; Type Id: FU - 007 1514360: FU - 007 1514360
Phasing - Phase Created: New Construction
Other(Type) - Category: Plumbing Fixtures; Family Name: FU - 007 1514360
Identity Data(Type) - Assembly Code: E2020200; Assembly Description: Furniture & Accessories; Type Name: FU - 007 1514360

# IfcFlowTerminal: FU - 007 1544889:FU - 007 1544889, FU - 007 1544889:FU - 007 1544889:207138
In: -2. Story
Classification: E2020200 Furniture & Accessories (Uniformat); Material: Stone - Marble Carrara White, Ceramic - Porcelain, Metal - Stainless Steel
Pset_DistributionFlowElementCommon - Reference: FU - 007 1544889; sets with these values: 2
Pset_ProductRequirements - Category: Plumbing Fixtures
Constraints - Moves With Nearby Elements: no
Dimensions - Area: 2.03682 m2; Volume: 0.00570302 m3
Identity Data - Mark: 32
Other - Category: Plumbing Fixtures; Family: FU - 007 1544889: FU - 007 1544889; Family and Type: FU - 007 1544889: FU - 007 1544889; Type: FU - 007 1544889: FU - 007 1544889; Type Id: FU - 007 1544889: FU - 007 1544889
Phasing - Phase Created: New Construction
Other(Type) - Category: Plumbing Fixtures; Family Name: FU - 007 1544889
Identity Data(Type) - Assembly Code: E2020200; Assembly Description: Furniture & Accessories; Type Name: FU - 007 1544889

# IfcFlowTerminal: FU - 007 1545421:FU - 007 1545421, FU - 007 1545421:FU - 007 1545421:207145
In: -2. Story
Classification: E2020200 Furniture & Accessories (Uniformat); Material: Stone - Marble Carrara White, Ceramic - Porcelain, Metal - Stainless Steel
Pset_DistributionFlowElementCommon - Reference: FU - 007 1545421; sets with these values: 2
Pset_ProductRequirements - Category: Plumbing Fixtures
Constraints - Moves With Nearby Elements: no
Dimensions - Area: 2.03682 m2; Volume: 0.00570302 m3
Identity Data - Mark: 34
Other - Category: Plumbing Fixtures; Family: FU - 007 1545421: FU - 007 1545421; Family and Type: FU - 007 1545421: FU - 007 1545421; Type: FU - 007 1545421: FU - 007 1545421; Type Id: FU - 007 1545421: FU - 007 1545421
Phasing - Phase Created: New Construction
Other(Type) - Category: Plumbing Fixtures; Family Name: FU - 007 1545421
Identity Data(Type) - Assembly Code: E2020200; Assembly Description: Furniture & Accessories; Type Name: FU - 007 1545421

# IfcFlowTerminal: FU - 007 1567312:FU - 007 1567312, FU - 007 1567312:FU - 007 1567312:208400
In: -2. Story
Classification: E2020200 Furniture & Accessories (Uniformat); Material: Stone - Marble Carrara White, Ceramic - Porcelain, Metal - Stainless Steel
Other(Type) - Category: Plumbing Fixtures; Family Name: FU - 007 1567312
Identity Data(Type) - Assembly Code: E2020200; Assembly Description: Furniture & Accessories; Type Name: FU - 007 1567312
Pset_DistributionFlowElementCommon - Reference: FU - 007 1567312; sets with these values: 2
Pset_ProductRequirements - Category: Plumbing Fixtures
Constraints - Moves With Nearby Elements: no
Dimensions - Area: 2.1959 m2; Volume: 0.00924349 m3
Identity Data - Mark: 44
Other - Category: Plumbing Fixtures; Family: FU - 007 1567312: FU - 007 1567312; Family and Type: FU - 007 1567312: FU - 007 1567312; Type: FU - 007 1567312: FU - 007 1567312; Type Id: FU - 007 1567312: FU - 007 1567312
Phasing - Phase Created: New Construction

# IfcFlowTerminal: FU - 007 1588719:FU - 007 1588719, FU - 007 1588719:FU - 007 1588719:209039
In: -2. Story
Classification: E2020200 Furniture & Accessories (Uniformat); Material: Stone - Marble Carrara White, Ceramic - Porcelain, Metal - Stainless Steel
Other(Type) - Category: Plumbing Fixtures; Family Name: FU - 007 1588719
Identity Data(Type) - Assembly Code: E2020200; Assembly Description: Furniture & Accessories; Type Name: FU - 007 1588719
Pset_DistributionFlowElementCommon - Reference: FU - 007 1588719; sets with these values: 2
Pset_ProductRequirements - Category: Plumbing Fixtures
Constraints - Moves With Nearby Elements: no
Dimensions - Area: 2.03682 m2; Volume: 0.00570302 m3
Identity Data - Mark: 50
Other - Category: Plumbing Fixtures; Family: FU - 007 1588719: FU - 007 1588719; Family and Type: FU - 007 1588719: FU - 007 1588719; Type: FU - 007 1588719: FU - 007 1588719; Type Id: FU - 007 1588719: FU - 007 1588719
Phasing - Phase Created: New Construction

# IfcFlowTerminal: FU - 007 1589242:FU - 007 1589242, FU - 007 1589242:FU - 007 1589242:209046
In: -2. Story
Classification: E2020200 Furniture & Accessories (Uniformat); Material: Stone - Marble Carrara White, Ceramic - Porcelain, Metal - Stainless Steel
Other(Type) - Category: Plumbing Fixtures; Family Name: FU - 007 1589242
Identity Data(Type) - Assembly Code: E2020200; Assembly Description: Furniture & Accessories; Type Name: FU - 007 1589242
Pset_DistributionFlowElementCommon - Reference: FU - 007 1589242; sets with these values: 2
Pset_ProductRequirements - Category: Plumbing Fixtures
Constraints - Moves With Nearby Elements: no
Dimensions - Area: 2.03682 m2; Volume: 0.00570302 m3
Identity Data - Mark: 52
Other - Category: Plumbing Fixtures; Family: FU - 007 1589242: FU - 007 1589242; Family and Type: FU - 007 1589242: FU - 007 1589242; Type: FU - 007 1589242: FU - 007 1589242; Type Id: FU - 007 1589242: FU - 007 1589242
Phasing - Phase Created: New Construction

# IfcFlowTerminal: FU - 007 1602645:FU - 007 1602645, FU - 007 1602645:FU - 007 1602645:210775
In: -2. Story
Classification: E2020200 Furniture & Accessories (Uniformat); Material: Stone - Marble Carrara White, Ceramic - Porcelain, Metal - Stainless Steel
Other(Type) - Category: Plumbing Fixtures; Family Name: FU - 007 1602645
Identity Data(Type) - Assembly Code: E2020200; Assembly Description: Furniture & Accessories; Type Name: FU - 007 1602645
Pset_DistributionFlowElementCommon - Reference: FU - 007 1602645; sets with these values: 2
Pset_ProductRequirements - Category: Plumbing Fixtures
Constraints - Moves With Nearby Elements: no
Dimensions - Area: 2.03682 m2; Volume: 0.00570302 m3
Identity Data - Mark: 70
Other - Category: Plumbing Fixtures; Family: FU - 007 1602645: FU - 007 1602645; Family and Type: FU - 007 1602645: FU - 007 1602645; Type: FU - 007 1602645: FU - 007 1602645; Type Id: FU - 007 1602645: FU - 007 1602645
Phasing - Phase Created: New Construction

# IfcFlowTerminal: FU - 007 1603168:FU - 007 1603168, FU - 007 1603168:FU - 007 1603168:210782
In: -2. Story
Classification: E2020200 Furniture & Accessories (Uniformat); Material: Stone - Marble Carrara White, Ceramic - Porcelain, Metal - Stainless Steel
Other(Type) - Category: Plumbing Fixtures; Family Name: FU - 007 1603168
Identity Data(Type) - Assembly Code: E2020200; Assembly Description: Furniture & Accessories; Type Name: FU - 007 1603168
Pset_DistributionFlowElementCommon - Reference: FU - 007 1603168; sets with these values: 2
Pset_ProductRequirements - Category: Plumbing Fixtures
Constraints - Moves With Nearby Elements: no
Dimensions - Area: 2.03682 m2; Volume: 0.00570302 m3
Identity Data - Mark: 72
Other - Category: Plumbing Fixtures; Family: FU - 007 1603168: FU - 007 1603168; Family and Type: FU - 007 1603168: FU - 007 1603168; Type: FU - 007 1603168: FU - 007 1603168; Type Id: FU - 007 1603168: FU - 007 1603168
Phasing - Phase Created: New Construction

# IfcFlowTerminal: FU - 007 1617897:FU - 007 1617897, FU - 007 1617897:FU - 007 1617897:212037
In: -2. Story
Classification: E2020200 Furniture & Accessories (Uniformat); Material: Stone - Marble Carrara White, Ceramic - Porcelain, Metal - Stainless Steel
Other(Type) - Category: Plumbing Fixtures; Family Name: FU - 007 1617897
Identity Data(Type) - Assembly Code: E2020200; Assembly Description: Furniture & Accessories; Type Name: FU - 007 1617897
Pset_DistributionFlowElementCommon - Reference: FU - 007 1617897; sets with these values: 2
Pset_ProductRequirements - Category: Plumbing Fixtures
Constraints - Moves With Nearby Elements: no
Dimensions - Area: 2.1959 m2; Volume: 0.00924349 m3
Identity Data - Mark: 82
Other - Category: Plumbing Fixtures; Family: FU - 007 1617897: FU - 007 1617897; Family and Type: FU - 007 1617897: FU - 007 1617897; Type: FU - 007 1617897: FU - 007 1617897; Type Id: FU - 007 1617897: FU - 007 1617897
Phasing - Phase Created: New Construction

# IfcFlowTerminal: LI - 001, LI - 001:LI - 001:212553
In: Ground Floor
Type - Classification: D5020280 Light Poles (Uniformat); Material: Metal - Stainless Steel, Glass - Satin
Type - Identity Data - Assembly Code: D5020280; Assembly Description: Light Poles; Type Name: LI - 001
Type - Other - Category: Lighting Fixtures; Family Name: LI - 001
Pset_DistributionFlowElementCommon - Reference: LI - 001; sets with these values: 2
Pset_Draughting - Red: 1; Green: 0; Blue: 0
Pset_ProductRequirements - Category: Lighting Fixtures
Constraints - Moves With Nearby Elements: no
Dimensions - Area: 0.774258 m2; Volume: 0.049611 m3
Electrical - Lighting - Calculate Coefficient of Utilization: no
Identity Data - Mark: 2
Other - Family: LI - 001: LI - 001; Family and Type: LI - 001: LI - 001; Type: LI - 001: LI - 001; Type Id: LI - 001: LI - 001
Phasing - Phase Created: New Construction

# IfcFlowTerminal: LI - 001, LI - 001 1676287:LI - 001 1676287:213009
In: Ground Floor
Type - Classification: D5020280 Light Poles (Uniformat); Material: Metal - Stainless Steel, Glass - Satin
Type - Identity Data - Assembly Code: D5020280; Assembly Description: Light Poles; Type Name: LI - 001 1676287
Type - Other - Category: Lighting Fixtures; Family Name: LI - 001 1676287
Pset_DistributionFlowElementCommon - Reference: LI - 001 1676287; sets with these values: 2
Pset_Draughting - Red: 1; Green: 0; Blue: 0
Pset_ProductRequirements - Category: Lighting Fixtures
Constraints - Moves With Nearby Elements: no
Dimensions - Area: 0.774258 m2; Volume: 0.049611 m3
Electrical - Lighting - Calculate Coefficient of Utilization: no
Identity Data - Mark: 4
Other - Family: LI - 001 1676287: LI - 001 1676287; Family and Type: LI - 001 1676287: LI - 001 1676287; Type: LI - 001 1676287: LI - 001 1676287; Type Id: LI - 001 1676287: LI - 001 1676287
Phasing - Phase Created: New Construction

# IfcFlowTerminal: LI - 001, LI - 001 1725304:LI - 001 1725304:213988
In: Ground Floor
Type - Classification: D5020280 Light Poles (Uniformat); Material: Metal - Stainless Steel, Glass - Satin
Type - Identity Data - Assembly Code: D5020280; Assembly Description: Light Poles; Type Name: LI - 001 1725304
Type - Other - Category: Lighting Fixtures; Family Name: LI - 001 1725304
Pset_DistributionFlowElementCommon - Reference: LI - 001 1725304; sets with these values: 2
Pset_Draughting - Red: 1; Green: 0; Blue: 0
Pset_ProductRequirements - Category: Lighting Fixtures
Constraints - Moves With Nearby Elements: no
Dimensions - Area: 0.774258 m2; Volume: 0.049611 m3
Electrical - Lighting - Calculate Coefficient of Utilization: no
Identity Data - Mark: 6
Other - Family: LI - 001 1725304: LI - 001 1725304; Family and Type: LI - 001 1725304: LI - 001 1725304; Type: LI - 001 1725304: LI - 001 1725304; Type Id: LI - 001 1725304: LI - 001 1725304
Phasing - Phase Created: New Construction

# IfcFlowTerminal: LI - 001, LI - 001 1768426:LI - 001 1768426:215499
In: Ground Floor
Type - Classification: D5020280 Light Poles (Uniformat); Material: Metal - Stainless Steel, Glass - Satin
Type - Identity Data - Assembly Code: D5020280; Assembly Description: Light Poles; Type Name: LI - 001 1768426
Type - Other - Category: Lighting Fixtures; Family Name: LI - 001 1768426
Pset_DistributionFlowElementCommon - Reference: LI - 001 1768426; sets with these values: 2
Pset_Draughting - Red: 1; Green: 0; Blue: 0
Pset_ProductRequirements - Category: Lighting Fixtures
Constraints - Moves With Nearby Elements: no
Dimensions - Area: 0.774258 m2; Volume: 0.049611 m3
Electrical - Lighting - Calculate Coefficient of Utilization: no
Identity Data - Mark: 8
Other - Family: LI - 001 1768426: LI - 001 1768426; Family and Type: LI - 001 1768426: LI - 001 1768426; Type: LI - 001 1768426: LI - 001 1768426; Type Id: LI - 001 1768426: LI - 001 1768426
Phasing - Phase Created: New Construction

# IfcFlowTerminal: LI - 001, LI - 001 1769851:LI - 001 1769851:215824
In: Ground Floor
Type - Classification: D5020280 Light Poles (Uniformat); Material: Metal - Stainless Steel, Glass - Satin
Type - Identity Data - Assembly Code: D5020280; Assembly Description: Light Poles; Type Name: LI - 001 1769851
Type - Other - Category: Lighting Fixtures; Family Name: LI - 001 1769851
Pset_DistributionFlowElementCommon - Reference: LI - 001 1769851; sets with these values: 2
Pset_Draughting - Red: 1; Green: 0; Blue: 0
Pset_ProductRequirements - Category: Lighting Fixtures
Constraints - Moves With Nearby Elements: no
Dimensions - Area: 0.774258 m2; Volume: 0.049611 m3
Electrical - Lighting - Calculate Coefficient of Utilization: no
Identity Data - Mark: 10
Other - Family: LI - 001 1769851: LI - 001 1769851; Family and Type: LI - 001 1769851: LI - 001 1769851; Type: LI - 001 1769851: LI - 001 1769851; Type Id: LI - 001 1769851: LI - 001 1769851
Phasing - Phase Created: New Construction

# IfcFlowTerminal: LI - 001, LI - 001 1770043:LI - 001 1770043:216124
In: Ground Floor
Type - Classification: D5020280 Light Poles (Uniformat); Material: Metal - Stainless Steel, Glass - Satin
Type - Identity Data - Assembly Code: D5020280; Assembly Description: Light Poles; Type Name: LI - 001 1770043
Type - Other - Category: Lighting Fixtures; Family Name: LI - 001 1770043
Pset_DistributionFlowElementCommon - Reference: LI - 001 1770043; sets with these values: 2
Pset_Draughting - Red: 1; Green: 0; Blue: 0
Pset_ProductRequirements - Category: Lighting Fixtures
Constraints - Moves With Nearby Elements: no
Dimensions - Area: 0.774258 m2; Volume: 0.049611 m3
Electrical - Lighting - Calculate Coefficient of Utilization: no
Identity Data - Mark: 12
Other - Family: LI - 001 1770043: LI - 001 1770043; Family and Type: LI - 001 1770043: LI - 001 1770043; Type: LI - 001 1770043: LI - 001 1770043; Type Id: LI - 001 1770043: LI - 001 1770043
Phasing - Phase Created: New Construction

# IfcFlowTerminal: LI - 001, LI - 001 1796179:LI - 001 1796179:216633
In: Ground Floor
Type - Classification: D5020280 Light Poles (Uniformat); Material: Metal - Stainless Steel, Glass - Satin
Type - Identity Data - Assembly Code: D5020280; Assembly Description: Light Poles; Type Name: LI - 001 1796179
Type - Other - Category: Lighting Fixtures; Family Name: LI - 001 1796179
Pset_DistributionFlowElementCommon - Reference: LI - 001 1796179; sets with these values: 2
Pset_Draughting - Red: 1; Green: 0; Blue: 0
Pset_ProductRequirements - Category: Lighting Fixtures
Constraints - Moves With Nearby Elements: no
Dimensions - Area: 0.774258 m2; Volume: 0.049611 m3
Electrical - Lighting - Calculate Coefficient of Utilization: no
Identity Data - Mark: 14
Other - Family: LI - 001 1796179: LI - 001 1796179; Family and Type: LI - 001 1796179: LI - 001 1796179; Type: LI - 001 1796179: LI - 001 1796179; Type Id: LI - 001 1796179: LI - 001 1796179
Phasing - Phase Created: New Construction

# IfcFurnishingElement: FU - 010, FU - 010:FU - 010:205384
In: -2. Story
Type - Classification: E2020200 Furniture & Accessories (Uniformat); Material: Metal - Stainless Steel, Paint - Glossy White, Paint - Cobalt Blue
Type - Identity Data - Assembly Code: E2020200; Assembly Description: Furniture & Accessories; Type Name: FU - 010
Type - Other - Category: Furniture; Family Name: FU - 010
Pset_ProductRequirements - Category: Furniture
Pset_QuantityTakeOff - Reference: FU - 010
Constraints - Moves With Nearby Elements: no
Dimensions - Area: 3.62929 m2; Volume: 0.135828 m3
Other - Family: FU - 010: FU - 010; Family and Type: FU - 010: FU - 010; Type: FU - 010: FU - 010; Type Id: FU - 010: FU - 010
Phasing - Phase Created: New Construction

# IfcFurnishingElement: FU - 010, FU - 010 1524329:FU - 010 1524329:206211
In: -2. Story
Type - Classification: E2020200 Furniture & Accessories (Uniformat); Material: Metal - Stainless Steel, Paint - Glossy White, Paint - Cobalt Blue
Type - Identity Data - Assembly Code: E2020200; Assembly Description: Furniture & Accessories; Type Name: FU - 010 1524329
Type - Other - Category: Furniture; Family Name: FU - 010 1524329
Pset_ProductRequirements - Category: Furniture
Pset_QuantityTakeOff - Reference: FU - 010 1524329
Constraints - Moves With Nearby Elements: no
Dimensions - Area: 3.62929 m2; Volume: 0.135828 m3
Other - Family: FU - 010 1524329: FU - 010 1524329; Family and Type: FU - 010 1524329: FU - 010 1524329; Type: FU - 010 1524329: FU - 010 1524329; Type Id: FU - 010 1524329: FU - 010 1524329
Phasing - Phase Created: New Construction

# IfcFurnishingElement: FU - 010, FU - 010 1524512:FU - 010 1524512:206476
In: -2. Story
Type - Classification: E2020200 Furniture & Accessories (Uniformat); Material: Metal - Stainless Steel, Paint - Glossy White, Paint - Cobalt Blue
Type - Identity Data - Assembly Code: E2020200; Assembly Description: Furniture & Accessories; Type Name: FU - 010 1524512
Type - Other - Category: Furniture; Family Name: FU - 010 1524512
Pset_ProductRequirements - Category: Furniture
Pset_QuantityTakeOff - Reference: FU - 010 1524512
Constraints - Moves With Nearby Elements: no
Dimensions - Area: 3.62929 m2; Volume: 0.135828 m3
Other - Family: FU - 010 1524512: FU - 010 1524512; Family and Type: FU - 010 1524512: FU - 010 1524512; Type: FU - 010 1524512: FU - 010 1524512; Type Id: FU - 010 1524512: FU - 010 1524512
Phasing - Phase Created: New Construction

# IfcFurnishingElement: FU - 010, FU - 010 1526725:FU - 010 1526725:206741
In: -2. Story
Type - Classification: E2020200 Furniture & Accessories (Uniformat); Material: Metal - Stainless Steel, Paint - Glossy White, Paint - Cobalt Blue
Type - Identity Data - Assembly Code: E2020200; Assembly Description: Furniture & Accessories; Type Name: FU - 010 1526725
Type - Other - Category: Furniture; Family Name: FU - 010 1526725
Pset_ProductRequirements - Category: Furniture
Pset_QuantityTakeOff - Reference: FU - 010 1526725
Constraints - Moves With Nearby Elements: no
Dimensions - Area: 4.83245 m2; Volume: 0.160373 m3
Other - Family: FU - 010 1526725: FU - 010 1526725; Family and Type: FU - 010 1526725: FU - 010 1526725; Type: FU - 010 1526725: FU - 010 1526725; Type Id: FU - 010 1526725: FU - 010 1526725
Phasing - Phase Created: New Construction

# IfcFurnishingElement: FU - 010, FU - 010 1547984:FU - 010 1547984:207152
In: -2. Story
Type - Classification: E2020200 Furniture & Accessories (Uniformat); Material: Metal - Stainless Steel, Paint - Glossy White, Paint - Cobalt Blue
Type - Identity Data - Assembly Code: E2020200; Assembly Description: Furniture & Accessories; Type Name: FU - 010 1547984
Type - Other - Category: Furniture; Family Name: FU - 010 1547984
Pset_ProductRequirements - Category: Furniture
Pset_QuantityTakeOff - Reference: FU - 010 1547984
Constraints - Moves With Nearby Elements: no
Dimensions - Area: 3.62929 m2; Volume: 0.135828 m3
Other - Family: FU - 010 1547984: FU - 010 1547984; Family and Type: FU - 010 1547984: FU - 010 1547984; Type: FU - 010 1547984: FU - 010 1547984; Type Id: FU - 010 1547984: FU - 010 1547984
Phasing - Phase Created: New Construction

# IfcFurnishingElement: FU - 010, FU - 010 1554754:FU - 010 1554754:207863
In: -2. Story
Type - Classification: E2020200 Furniture & Accessories (Uniformat); Material: Metal - Stainless Steel, Paint - Glossy White, Paint - Cobalt Blue
Type - Identity Data - Assembly Code: E2020200; Assembly Description: Furniture & Accessories; Type Name: FU - 010 1554754
Type - Other - Category: Furniture; Family Name: FU - 010 1554754
Pset_ProductRequirements - Category: Furniture
Pset_QuantityTakeOff - Reference: FU - 010 1554754
Constraints - Moves With Nearby Elements: no
Dimensions - Area: 3.62929 m2; Volume: 0.135828 m3
Other - Family: FU - 010 1554754: FU - 010 1554754; Family and Type: FU - 010 1554754: FU - 010 1554754; Type: FU - 010 1554754: FU - 010 1554754; Type Id: FU - 010 1554754: FU - 010 1554754
Phasing - Phase Created: New Construction

# IfcFurnishingElement: FU - 010, FU - 010 1556967:FU - 010 1556967:208128
In: -2. Story
Type - Classification: E2020200 Furniture & Accessories (Uniformat); Material: Metal - Stainless Steel, Paint - Glossy White, Paint - Cobalt Blue
Type - Identity Data - Assembly Code: E2020200; Assembly Description: Furniture & Accessories; Type Name: FU - 010 1556967
Type - Other - Category: Furniture; Family Name: FU - 010 1556967
Pset_ProductRequirements - Category: Furniture
Pset_QuantityTakeOff - Reference: FU - 010 1556967
Constraints - Moves With Nearby Elements: no
Dimensions - Area: 6.34638 m2; Volume: 0.191257 m3
Other - Family: FU - 010 1556967: FU - 010 1556967; Family and Type: FU - 010 1556967: FU - 010 1556967; Type: FU - 010 1556967: FU - 010 1556967; Type Id: FU - 010 1556967: FU - 010 1556967
Phasing - Phase Created: New Construction

# IfcFurnishingElement: FU - 010, FU - 010 1590366:FU - 010 1590366:209137
In: -2. Story
Type - Classification: E2020200 Furniture & Accessories (Uniformat); Material: Metal - Stainless Steel, Paint - Glossy White, Paint - Cobalt Blue
Type - Identity Data - Assembly Code: E2020200; Assembly Description: Furniture & Accessories; Type Name: FU - 010 1590366
Type - Other - Category: Furniture; Family Name: FU - 010 1590366
Pset_ProductRequirements - Category: Furniture
Pset_QuantityTakeOff - Reference: FU - 010 1590366
Constraints - Moves With Nearby Elements: no
Dimensions - Area: 3.62929 m2; Volume: 0.135828 m3
Other - Family: FU - 010 1590366: FU - 010 1590366; Family and Type: FU - 010 1590366: FU - 010 1590366; Type: FU - 010 1590366: FU - 010 1590366; Type Id: FU - 010 1590366: FU - 010 1590366
Phasing - Phase Created: New Construction

# IfcFurnishingElement: FU - 010, FU - 010 1592014:FU - 010 1592014:209848
In: -2. Story
Type - Classification: E2020200 Furniture & Accessories (Uniformat); Material: Metal - Stainless Steel, Paint - Glossy White, Paint - Cobalt Blue
Type - Identity Data - Assembly Code: E2020200; Assembly Description: Furniture & Accessories; Type Name: FU - 010 1592014
Type - Other - Category: Furniture; Family Name: FU - 010 1592014
Pset_ProductRequirements - Category: Furniture
Pset_QuantityTakeOff - Reference: FU - 010 1592014
Constraints - Moves With Nearby Elements: no
Dimensions - Area: 3.62929 m2; Volume: 0.135828 m3
Other - Family: FU - 010 1592014: FU - 010 1592014; Family and Type: FU - 010 1592014: FU - 010 1592014; Type: FU - 010 1592014: FU - 010 1592014; Type Id: FU - 010 1592014: FU - 010 1592014
Phasing - Phase Created: New Construction

# IfcFurnishingElement: FU - 010, FU - 010 1592197:FU - 010 1592197:210113
In: -2. Story
Type - Classification: E2020200 Furniture & Accessories (Uniformat); Material: Metal - Stainless Steel, Paint - Glossy White, Paint - Cobalt Blue
Type - Identity Data - Assembly Code: E2020200; Assembly Description: Furniture & Accessories; Type Name: FU - 010 1592197
Type - Other - Category: Furniture; Family Name: FU - 010 1592197
Pset_ProductRequirements - Category: Furniture
Pset_QuantityTakeOff - Reference: FU - 010 1592197
Constraints - Moves With Nearby Elements: no
Dimensions - Area: 3.62929 m2; Volume: 0.135828 m3
Other - Family: FU - 010 1592197: FU - 010 1592197; Family and Type: FU - 010 1592197: FU - 010 1592197; Type: FU - 010 1592197: FU - 010 1592197; Type Id: FU - 010 1592197: FU - 010 1592197
Phasing - Phase Created: New Construction

# IfcFurnishingElement: FU - 010, FU - 010 1594410:FU - 010 1594410:210378
In: -2. Story
Type - Classification: E2020200 Furniture & Accessories (Uniformat); Material: Metal - Stainless Steel, Paint - Glossy White, Paint - Cobalt Blue
Type - Identity Data - Assembly Code: E2020200; Assembly Description: Furniture & Accessories; Type Name: FU - 010 1594410
Type - Other - Category: Furniture; Family Name: FU - 010 1594410
Pset_ProductRequirements - Category: Furniture
Pset_QuantityTakeOff - Reference: FU - 010 1594410
Constraints - Moves With Nearby Elements: no
Dimensions - Area: 4.83245 m2; Volume: 0.160373 m3
Other - Family: FU - 010 1594410: FU - 010 1594410; Family and Type: FU - 010 1594410: FU - 010 1594410; Type: FU - 010 1594410: FU - 010 1594410; Type Id: FU - 010 1594410: FU - 010 1594410
Phasing - Phase Created: New Construction

# IfcFurnishingElement: FU - 010, FU - 010 1603691:FU - 010 1603691:210789
In: -2. Story
Type - Classification: E2020200 Furniture & Accessories (Uniformat); Material: Metal - Stainless Steel, Paint - Glossy White, Paint - Cobalt Blue
Type - Identity Data - Assembly Code: E2020200; Assembly Description: Furniture & Accessories; Type Name: FU - 010 1603691
Type - Other - Category: Furniture; Family Name: FU - 010 1603691
Pset_ProductRequirements - Category: Furniture
Pset_QuantityTakeOff - Reference: FU - 010 1603691
Constraints - Moves With Nearby Elements: no
Dimensions - Area: 3.62929 m2; Volume: 0.135828 m3
Other - Family: FU - 010 1603691: FU - 010 1603691; Family and Type: FU - 010 1603691: FU - 010 1603691; Type: FU - 010 1603691: FU - 010 1603691; Type Id: FU - 010 1603691: FU - 010 1603691
Phasing - Phase Created: New Construction

# IfcFurnishingElement: FU - 010, FU - 010 1605339:FU - 010 1605339:211500
In: -2. Story
Type - Classification: E2020200 Furniture & Accessories (Uniformat); Material: Metal - Stainless Steel, Paint - Glossy White, Paint - Cobalt Blue
Type - Identity Data - Assembly Code: E2020200; Assembly Description: Furniture & Accessories; Type Name: FU - 010 1605339
Type - Other - Category: Furniture; Family Name: FU - 010 1605339
Pset_ProductRequirements - Category: Furniture
Pset_QuantityTakeOff - Reference: FU - 010 1605339
Constraints - Moves With Nearby Elements: no
Dimensions - Area: 3.62929 m2; Volume: 0.135828 m3
Other - Family: FU - 010 1605339: FU - 010 1605339; Family and Type: FU - 010 1605339: FU - 010 1605339; Type: FU - 010 1605339: FU - 010 1605339; Type Id: FU - 010 1605339: FU - 010 1605339
Phasing - Phase Created: New Construction

# IfcFurnishingElement: FU - 010, FU - 010 1607552:FU - 010 1607552:211765
In: -2. Story
Type - Classification: E2020200 Furniture & Accessories (Uniformat); Material: Metal - Stainless Steel, Paint - Glossy White, Paint - Cobalt Blue
Type - Identity Data - Assembly Code: E2020200; Assembly Description: Furniture & Accessories; Type Name: FU - 010 1607552
Type - Other - Category: Furniture; Family Name: FU - 010 1607552
Pset_ProductRequirements - Category: Furniture
Pset_QuantityTakeOff - Reference: FU - 010 1607552
Constraints - Moves With Nearby Elements: no
Dimensions - Area: 6.34638 m2; Volume: 0.191257 m3
Other - Family: FU - 010 1607552: FU - 010 1607552; Family and Type: FU - 010 1607552: FU - 010 1607552; Type: FU - 010 1607552: FU - 010 1607552; Type Id: FU - 010 1607552: FU - 010 1607552
Phasing - Phase Created: New Construction

# IfcFurnishingElement: FU - 011, FU - 011:FU - 011:205756
In: -2. Story
Type - Classification: E2020200 Furniture & Accessories (Uniformat); Material: Wood - Pine Grained Horizontal, Paint - Titanium White
Type - Identity Data - Assembly Code: E2020200; Assembly Description: Furniture & Accessories; Type Name: FU - 011
Type - Other - Category: Furniture; Family Name: FU - 011
Pset_ProductRequirements - Category: Furniture
Pset_QuantityTakeOff - Reference: FU - 011
Constraints - Moves With Nearby Elements: no
Dimensions - Area: 0.646198 m2; Volume: 0.0666749 m3
Other - Family: FU - 011: FU - 011; Family and Type: FU - 011: FU - 011; Type: FU - 011: FU - 011; Type Id: FU - 011: FU - 011
Phasing - Phase Created: New Construction

# IfcFurnishingElement: FU - 011, FU - 011 1520968:FU - 011 1520968:205857
In: -2. Story
Type - Classification: E2020200 Furniture & Accessories (Uniformat); Material: Wood - Pine Grained Horizontal, Paint - Titanium White
Type - Identity Data - Assembly Code: E2020200; Assembly Description: Furniture & Accessories; Type Name: FU - 011 1520968
Type - Other - Category: Furniture; Family Name: FU - 011 1520968
Pset_ProductRequirements - Category: Furniture
Pset_QuantityTakeOff - Reference: FU - 011 1520968
Constraints - Moves With Nearby Elements: no
Dimensions - Area: 0.717671 m2; Volume: 0.0695339 m3
Other - Family: FU - 011 1520968: FU - 011 1520968; Family and Type: FU - 011 1520968: FU - 011 1520968; Type: FU - 011 1520968: FU - 011 1520968; Type Id: FU - 011 1520968: FU - 011 1520968
Phasing - Phase Created: New Construction

# IfcFurnishingElement: FU - 011, FU - 011 1521730:FU - 011 1521730:205942
In: -2. Story
Type - Classification: E2020200 Furniture & Accessories (Uniformat); Material: Wood - Pine Grained Horizontal, Paint - Titanium White
Type - Identity Data - Assembly Code: E2020200; Assembly Description: Furniture & Accessories; Type Name: FU - 011 1521730
Type - Other - Category: Furniture; Family Name: FU - 011 1521730
Pset_ProductRequirements - Category: Furniture
Pset_QuantityTakeOff - Reference: FU - 011 1521730
Constraints - Moves With Nearby Elements: no
Dimensions - Area: 0.713513 m2; Volume: 0.0693676 m3
Other - Family: FU - 011 1521730: FU - 011 1521730; Family and Type: FU - 011 1521730: FU - 011 1521730; Type: FU - 011 1521730: FU - 011 1521730; Type Id: FU - 011 1521730: FU - 011 1521730
Phasing - Phase Created: New Construction

# IfcFurnishingElement: FU - 011, FU - 011 1521888:FU - 011 1521888:206027
In: -2. Story
Type - Classification: E2020200 Furniture & Accessories (Uniformat); Material: Wood - Pine Grained Horizontal, Paint - Titanium White
Type - Identity Data - Assembly Code: E2020200; Assembly Description: Furniture & Accessories; Type Name: FU - 011 1521888
Type - Other - Category: Furniture; Family Name: FU - 011 1521888
Pset_ProductRequirements - Category: Furniture
Pset_QuantityTakeOff - Reference: FU - 011 1521888
Constraints - Moves With Nearby Elements: no
Dimensions - Area: 0.646198 m2; Volume: 0.0666749 m3
Other - Family: FU - 011 1521888: FU - 011 1521888; Family and Type: FU - 011 1521888: FU - 011 1521888; Type: FU - 011 1521888: FU - 011 1521888; Type Id: FU - 011 1521888: FU - 011 1521888
Phasing - Phase Created: New Construction

# IfcFurnishingElement: FU - 011, FU - 011 1524180:FU - 011 1524180:206126
In: -2. Story
Type - Classification: E2020200 Furniture & Accessories (Uniformat); Material: Wood - Pine Grained Horizontal, Paint - Titanium White
Type - Identity Data - Assembly Code: E2020200; Assembly Description: Furniture & Accessories; Type Name: FU - 011 1524180
Type - Other - Category: Furniture; Family Name: FU - 011 1524180
Pset_ProductRequirements - Category: Furniture
Pset_QuantityTakeOff - Reference: FU - 011 1524180
Constraints - Moves With Nearby Elements: no
Dimensions - Area: 0.646198 m2; Volume: 0.0666749 m3
Other - Family: FU - 011 1524180: FU - 011 1524180; Family and Type: FU - 011 1524180: FU - 011 1524180; Type: FU - 011 1524180: FU - 011 1524180; Type Id: FU - 011 1524180: FU - 011 1524180
Phasing - Phase Created: New Construction

# IfcFurnishingElement: FU - 011, FU - 011 1550631:FU - 011 1550631:207424
In: -2. Story
Type - Classification: E2020200 Furniture & Accessories (Uniformat); Material: Wood - Pine Grained Horizontal, Paint - Titanium White
Type - Identity Data - Assembly Code: E2020200; Assembly Description: Furniture & Accessories; Type Name: FU - 011 1550631
Type - Other - Category: Furniture; Family Name: FU - 011 1550631
Pset_ProductRequirements - Category: Furniture
Pset_QuantityTakeOff - Reference: FU - 011 1550631
Constraints - Moves With Nearby Elements: no
Dimensions - Area: 0.646198 m2; Volume: 0.0666749 m3
Other - Family: FU - 011 1550631: FU - 011 1550631; Family and Type: FU - 011 1550631: FU - 011 1550631; Type: FU - 011 1550631: FU - 011 1550631; Type Id: FU - 011 1550631: FU - 011 1550631
Phasing - Phase Created: New Construction

# IfcFurnishingElement: FU - 011, FU - 011 1551393:FU - 011 1551393:207509
In: -2. Story
Type - Classification: E2020200 Furniture & Accessories (Uniformat); Material: Wood - Pine Grained Horizontal, Paint - Titanium White
Type - Identity Data - Assembly Code: E2020200; Assembly Description: Furniture & Accessories; Type Name: FU - 011 1551393
Type - Other - Category: Furniture; Family Name: FU - 011 1551393
Pset_ProductRequirements - Category: Furniture
Pset_QuantityTakeOff - Reference: FU - 011 1551393
Constraints - Moves With Nearby Elements: no
Dimensions - Area: 0.717671 m2; Volume: 0.0695339 m3
Other - Family: FU - 011 1551393: FU - 011 1551393; Family and Type: FU - 011 1551393: FU - 011 1551393; Type: FU - 011 1551393: FU - 011 1551393; Type Id: FU - 011 1551393: FU - 011 1551393
Phasing - Phase Created: New Construction

# IfcFurnishingElement: FU - 011, FU - 011 1552155:FU - 011 1552155:207594
In: -2. Story
Type - Classification: E2020200 Furniture & Accessories (Uniformat); Material: Wood - Pine Grained Horizontal, Paint - Titanium White
Type - Identity Data - Assembly Code: E2020200; Assembly Description: Furniture & Accessories; Type Name: FU - 011 1552155
Type - Other - Category: Furniture; Family Name: FU - 011 1552155
Pset_ProductRequirements - Category: Furniture
Pset_QuantityTakeOff - Reference: FU - 011 1552155
Constraints - Moves With Nearby Elements: no
Dimensions - Area: 0.713513 m2; Volume: 0.0693676 m3
Other - Family: FU - 011 1552155: FU - 011 1552155; Family and Type: FU - 011 1552155: FU - 011 1552155; Type: FU - 011 1552155: FU - 011 1552155; Type Id: FU - 011 1552155: FU - 011 1552155
Phasing - Phase Created: New Construction

# IfcFurnishingElement: FU - 011, FU - 011 1552553:FU - 011 1552553:207686
In: -2. Story
Type - Classification: E2020200 Furniture & Accessories (Uniformat); Material: Wood - Pine Grained Horizontal, Paint - Titanium White
Type - Identity Data - Assembly Code: E2020200; Assembly Description: Furniture & Accessories; Type Name: FU - 011 1552553
Type - Other - Category: Furniture; Family Name: FU - 011 1552553
Pset_ProductRequirements - Category: Furniture
Pset_QuantityTakeOff - Reference: FU - 011 1552553
Constraints - Moves With Nearby Elements: no
Dimensions - Area: 0.646198 m2; Volume: 0.0666749 m3
Other - Family: FU - 011 1552553: FU - 011 1552553; Family and Type: FU - 011 1552553: FU - 011 1552553; Type: FU - 011 1552553: FU - 011 1552553; Type Id: FU - 011 1552553: FU - 011 1552553
Phasing - Phase Created: New Construction

# IfcFurnishingElement: FU - 011, FU - 011 1554605:FU - 011 1554605:207778
In: -2. Story
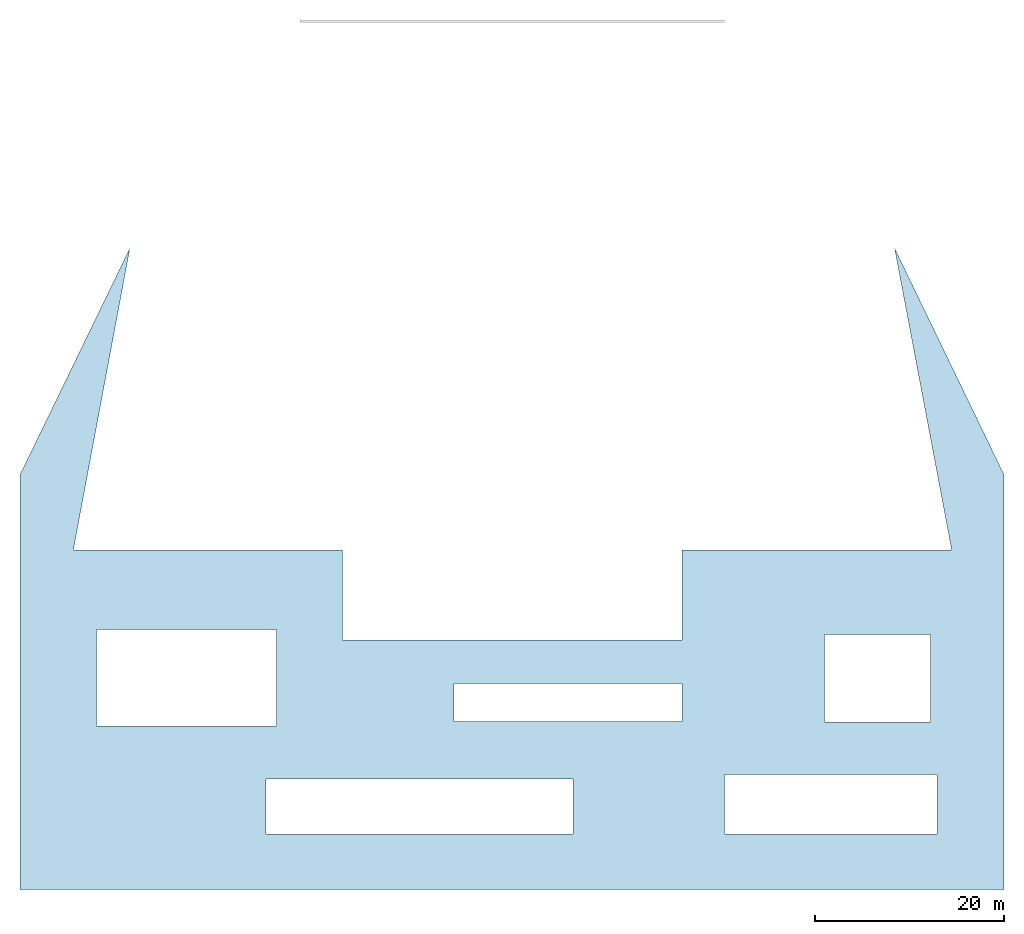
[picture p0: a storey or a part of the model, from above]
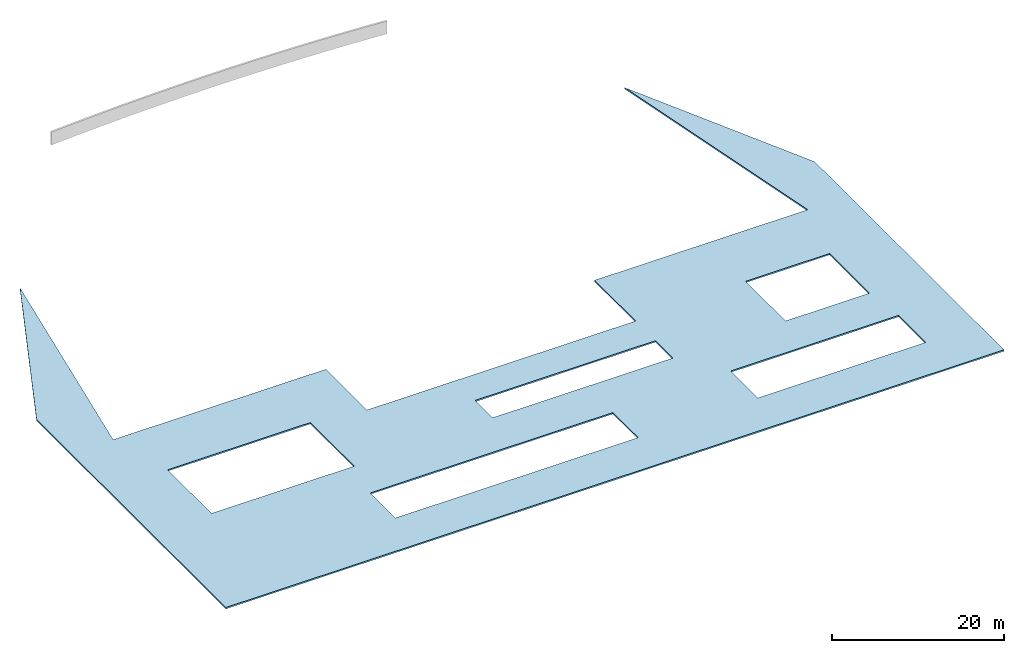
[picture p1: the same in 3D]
Properties of the parts of a building model (IFC2X3), part 3 of 4

# IfcFurnishingElement: FU - 011, FU - 011 1554605:FU - 011 1554605:207778
Type - Classification: E2020200 Furniture & Accessories (Uniformat); Material: Wood - Pine Grained Horizontal, Paint - Titanium White
Type - Identity Data - Assembly Code: E2020200; Assembly Description: Furniture & Accessories; Type Name: FU - 011 1554605
Type - Other - Category: Furniture; Family Name: FU - 011 1554605
Pset_ProductRequirements - Category: Furniture
Pset_QuantityTakeOff - Reference: FU - 011 1554605
Constraints - Moves With Nearby Elements: no
Dimensions - Area: 0.646198 m2; Volume: 0.0666749 m3
Other - Family: FU - 011 1554605: FU - 011 1554605; Family and Type: FU - 011 1554605: FU - 011 1554605; Type: FU - 011 1554605: FU - 011 1554605; Type Id: FU - 011 1554605: FU - 011 1554605
Phasing - Phase Created: New Construction

# IfcFurnishingElement: FU - 011, FU - 011 1570972:FU - 011 1570972:208540
In: -2. Story
Type - Classification: E2020200 Furniture & Accessories (Uniformat); Material: Wood - Pine Grained Horizontal, Paint - Titanium White
Type - Identity Data - Assembly Code: E2020200; Assembly Description: Furniture & Accessories; Type Name: FU - 011 1570972
Type - Other - Category: Furniture; Family Name: FU - 011 1570972
Pset_ProductRequirements - Category: Furniture
Pset_QuantityTakeOff - Reference: FU - 011 1570972
Constraints - Moves With Nearby Elements: no
Dimensions - Area: 0.614356 m2; Volume: 0.0654013 m3
Other - Family: FU - 011 1570972: FU - 011 1570972; Family and Type: FU - 011 1570972: FU - 011 1570972; Type: FU - 011 1570972: FU - 011 1570972; Type Id: FU - 011 1570972: FU - 011 1570972
Phasing - Phase Created: New Construction

# IfcFurnishingElement: FU - 011, FU - 011 1590789:FU - 011 1590789:209409
In: -2. Story
Type - Classification: E2020200 Furniture & Accessories (Uniformat); Material: Wood - Pine Grained Horizontal, Paint - Titanium White
Type - Identity Data - Assembly Code: E2020200; Assembly Description: Furniture & Accessories; Type Name: FU - 011 1590789
Type - Other - Category: Furniture; Family Name: FU - 011 1590789
Pset_ProductRequirements - Category: Furniture
Pset_QuantityTakeOff - Reference: FU - 011 1590789
Constraints - Moves With Nearby Elements: no
Dimensions - Area: 0.646198 m2; Volume: 0.0666749 m3
Other - Family: FU - 011 1590789: FU - 011 1590789; Family and Type: FU - 011 1590789: FU - 011 1590789; Type: FU - 011 1590789: FU - 011 1590789; Type Id: FU - 011 1590789: FU - 011 1590789
Phasing - Phase Created: New Construction

# IfcFurnishingElement: FU - 011, FU - 011 1590938:FU - 011 1590938:209494
In: -2. Story
Type - Classification: E2020200 Furniture & Accessories (Uniformat); Material: Wood - Pine Grained Horizontal, Paint - Titanium White
Type - Identity Data - Assembly Code: E2020200; Assembly Description: Furniture & Accessories; Type Name: FU - 011 1590938
Type - Other - Category: Furniture; Family Name: FU - 011 1590938
Pset_ProductRequirements - Category: Furniture
Pset_QuantityTakeOff - Reference: FU - 011 1590938
Constraints - Moves With Nearby Elements: no
Dimensions - Area: 0.717671 m2; Volume: 0.0695339 m3
Other - Family: FU - 011 1590938: FU - 011 1590938; Family and Type: FU - 011 1590938: FU - 011 1590938; Type: FU - 011 1590938: FU - 011 1590938; Type Id: FU - 011 1590938: FU - 011 1590938
Phasing - Phase Created: New Construction

# IfcFurnishingElement: FU - 011, FU - 011 1591087:FU - 011 1591087:209579
In: -2. Story
Type - Classification: E2020200 Furniture & Accessories (Uniformat); Material: Wood - Pine Grained Horizontal, Paint - Titanium White
Type - Identity Data - Assembly Code: E2020200; Assembly Description: Furniture & Accessories; Type Name: FU - 011 1591087
Type - Other - Category: Furniture; Family Name: FU - 011 1591087
Pset_ProductRequirements - Category: Furniture
Pset_QuantityTakeOff - Reference: FU - 011 1591087
Constraints - Moves With Nearby Elements: no
Dimensions - Area: 0.713513 m2; Volume: 0.0693676 m3
Other - Family: FU - 011 1591087: FU - 011 1591087; Family and Type: FU - 011 1591087: FU - 011 1591087; Type: FU - 011 1591087: FU - 011 1591087; Type Id: FU - 011 1591087: FU - 011 1591087
Phasing - Phase Created: New Construction

# IfcFurnishingElement: FU - 011, FU - 011 1591476:FU - 011 1591476:209671
In: -2. Story
Type - Classification: E2020200 Furniture & Accessories (Uniformat); Material: Wood - Pine Grained Horizontal, Paint - Titanium White
Type - Identity Data - Assembly Code: E2020200; Assembly Description: Furniture & Accessories; Type Name: FU - 011 1591476
Type - Other - Category: Furniture; Family Name: FU - 011 1591476
Pset_ProductRequirements - Category: Furniture
Pset_QuantityTakeOff - Reference: FU - 011 1591476
Constraints - Moves With Nearby Elements: no
Dimensions - Area: 0.646198 m2; Volume: 0.0666749 m3
Other - Family: FU - 011 1591476: FU - 011 1591476; Family and Type: FU - 011 1591476: FU - 011 1591476; Type: FU - 011 1591476: FU - 011 1591476; Type Id: FU - 011 1591476: FU - 011 1591476
Phasing - Phase Created: New Construction

# IfcFurnishingElement: FU - 011, FU - 011 1591865:FU - 011 1591865:209763
In: -2. Story
Type - Classification: E2020200 Furniture & Accessories (Uniformat); Material: Wood - Pine Grained Horizontal, Paint - Titanium White
Type - Identity Data - Assembly Code: E2020200; Assembly Description: Furniture & Accessories; Type Name: FU - 011 1591865
Type - Other - Category: Furniture; Family Name: FU - 011 1591865
Pset_ProductRequirements - Category: Furniture
Pset_QuantityTakeOff - Reference: FU - 011 1591865
Constraints - Moves With Nearby Elements: no
Dimensions - Area: 0.646198 m2; Volume: 0.0666749 m3
Other - Family: FU - 011 1591865: FU - 011 1591865; Family and Type: FU - 011 1591865: FU - 011 1591865; Type: FU - 011 1591865: FU - 011 1591865; Type Id: FU - 011 1591865: FU - 011 1591865
Phasing - Phase Created: New Construction

# IfcFurnishingElement: FU - 011, FU - 011 1604114:FU - 011 1604114:211061
In: -2. Story
Type - Classification: E2020200 Furniture & Accessories (Uniformat); Material: Wood - Pine Grained Horizontal, Paint - Titanium White
Type - Identity Data - Assembly Code: E2020200; Assembly Description: Furniture & Accessories; Type Name: FU - 011 1604114
Type - Other - Category: Furniture; Family Name: FU - 011 1604114
Pset_ProductRequirements - Category: Furniture
Pset_QuantityTakeOff - Reference: FU - 011 1604114
Constraints - Moves With Nearby Elements: no
Dimensions - Area: 0.646198 m2; Volume: 0.0666749 m3
Other - Family: FU - 011 1604114: FU - 011 1604114; Family and Type: FU - 011 1604114: FU - 011 1604114; Type: FU - 011 1604114: FU - 011 1604114; Type Id: FU - 011 1604114: FU - 011 1604114
Phasing - Phase Created: New Construction

# IfcFurnishingElement: FU - 011, FU - 011 1604263:FU - 011 1604263:211146
In: -2. Story
Type - Classification: E2020200 Furniture & Accessories (Uniformat); Material: Wood - Pine Grained Horizontal, Paint - Titanium White
Type - Identity Data - Assembly Code: E2020200; Assembly Description: Furniture & Accessories; Type Name: FU - 011 1604263
Type - Other - Category: Furniture; Family Name: FU - 011 1604263
Pset_ProductRequirements - Category: Furniture
Pset_QuantityTakeOff - Reference: FU - 011 1604263
Constraints - Moves With Nearby Elements: no
Dimensions - Area: 0.717671 m2; Volume: 0.0695339 m3
Other - Family: FU - 011 1604263: FU - 011 1604263; Family and Type: FU - 011 1604263: FU - 011 1604263; Type: FU - 011 1604263: FU - 011 1604263; Type Id: FU - 011 1604263: FU - 011 1604263
Phasing - Phase Created: New Construction

# IfcFurnishingElement: FU - 011, FU - 011 1604412:FU - 011 1604412:211231
In: -2. Story
Type - Classification: E2020200 Furniture & Accessories (Uniformat); Material: Wood - Pine Grained Horizontal, Paint - Titanium White
Type - Identity Data - Assembly Code: E2020200; Assembly Description: Furniture & Accessories; Type Name: FU - 011 1604412
Type - Other - Category: Furniture; Family Name: FU - 011 1604412
Pset_ProductRequirements - Category: Furniture
Pset_QuantityTakeOff - Reference: FU - 011 1604412
Constraints - Moves With Nearby Elements: no
Dimensions - Area: 0.713513 m2; Volume: 0.0693676 m3
Other - Family: FU - 011 1604412: FU - 011 1604412; Family and Type: FU - 011 1604412: FU - 011 1604412; Type: FU - 011 1604412: FU - 011 1604412; Type Id: FU - 011 1604412: FU - 011 1604412
Phasing - Phase Created: New Construction

# IfcFurnishingElement: FU - 011, FU - 011 1604801:FU - 011 1604801:211323
In: -2. Story
Type - Classification: E2020200 Furniture & Accessories (Uniformat); Material: Wood - Pine Grained Horizontal, Paint - Titanium White
Type - Identity Data - Assembly Code: E2020200; Assembly Description: Furniture & Accessories; Type Name: FU - 011 1604801
Type - Other - Category: Furniture; Family Name: FU - 011 1604801
Pset_ProductRequirements - Category: Furniture
Pset_QuantityTakeOff - Reference: FU - 011 1604801
Constraints - Moves With Nearby Elements: no
Dimensions - Area: 0.646198 m2; Volume: 0.0666749 m3
Other - Family: FU - 011 1604801: FU - 011 1604801; Family and Type: FU - 011 1604801: FU - 011 1604801; Type: FU - 011 1604801: FU - 011 1604801; Type Id: FU - 011 1604801: FU - 011 1604801
Phasing - Phase Created: New Construction

# IfcFurnishingElement: FU - 011, FU - 011 1605190:FU - 011 1605190:211415
In: -2. Story
Type - Classification: E2020200 Furniture & Accessories (Uniformat); Material: Wood - Pine Grained Horizontal, Paint - Titanium White
Type - Identity Data - Assembly Code: E2020200; Assembly Description: Furniture & Accessories; Type Name: FU - 011 1605190
Type - Other - Category: Furniture; Family Name: FU - 011 1605190
Pset_ProductRequirements - Category: Furniture
Pset_QuantityTakeOff - Reference: FU - 011 1605190
Constraints - Moves With Nearby Elements: no
Dimensions - Area: 0.646198 m2; Volume: 0.0666749 m3
Other - Family: FU - 011 1605190: FU - 011 1605190; Family and Type: FU - 011 1605190: FU - 011 1605190; Type: FU - 011 1605190: FU - 011 1605190; Type Id: FU - 011 1605190: FU - 011 1605190
Phasing - Phase Created: New Construction

# IfcFurnishingElement: FU - 011, FU - 011 1621557:FU - 011 1621557:212177
In: -2. Story
Type - Classification: E2020200 Furniture & Accessories (Uniformat); Material: Wood - Pine Grained Horizontal, Paint - Titanium White
Type - Identity Data - Assembly Code: E2020200; Assembly Description: Furniture & Accessories; Type Name: FU - 011 1621557
Type - Other - Category: Furniture; Family Name: FU - 011 1621557
Pset_ProductRequirements - Category: Furniture
Pset_QuantityTakeOff - Reference: FU - 011 1621557
Constraints - Moves With Nearby Elements: no
Dimensions - Area: 0.614356 m2; Volume: 0.0654013 m3
Other - Family: FU - 011 1621557: FU - 011 1621557; Family and Type: FU - 011 1621557: FU - 011 1621557; Type: FU - 011 1621557: FU - 011 1621557; Type Id: FU - 011 1621557: FU - 011 1621557
Phasing - Phase Created: New Construction

# IfcFurnishingElement: FU - 036, FU - 036:FU - 036:213484
In: Ground Floor
Type - Classification: E2010500 Fixed Multiple Seating (Uniformat); Material: Wood - Pine Grained Horizontal, Paint - Titanium White
Type - Identity Data - Assembly Code: E2010500; Assembly Description: Fixed Multiple Seating; Type Name: FU - 036
Type - Other - Category: Furniture; Family Name: FU - 036
Pset_ProductRequirements - Category: Furniture
Pset_QuantityTakeOff - Reference: FU - 036
Constraints - Moves With Nearby Elements: no
Dimensions - Area: 1.3248 m2; Volume: 0.11298 m3
Other - Family: FU - 036: FU - 036; Family and Type: FU - 036: FU - 036; Type: FU - 036: FU - 036; Type Id: FU - 036: FU - 036
Phasing - Phase Created: New Construction

# IfcFurnishingElement: FU - 036, FU - 036 1723160:FU - 036 1723160:213583
In: Ground Floor
Type - Classification: E2010500 Fixed Multiple Seating (Uniformat); Material: Wood - Pine Grained Horizontal, Paint - Titanium White
Type - Identity Data - Assembly Code: E2010500; Assembly Description: Fixed Multiple Seating; Type Name: FU - 036 1723160
Type - Other - Category: Furniture; Family Name: FU - 036 1723160
Pset_ProductRequirements - Category: Furniture
Pset_QuantityTakeOff - Reference: FU - 036 1723160
Constraints - Moves With Nearby Elements: no
Dimensions - Area: 1.3248 m2; Volume: 0.11298 m3
Other - Family: FU - 036 1723160: FU - 036 1723160; Family and Type: FU - 036 1723160: FU - 036 1723160; Type: FU - 036 1723160: FU - 036 1723160; Type Id: FU - 036 1723160: FU - 036 1723160
Phasing - Phase Created: New Construction

# IfcFurnishingElement: FU - 036, FU - 036 1724857:FU - 036 1724857:213733
In: Ground Floor
Type - Classification: E2010500 Fixed Multiple Seating (Uniformat); Material: Wood - Pine Grained Horizontal, Paint - Titanium White
Type - Identity Data - Assembly Code: E2010500; Assembly Description: Fixed Multiple Seating; Type Name: FU - 036 1724857
Type - Other - Category: Furniture; Family Name: FU - 036 1724857
Pset_ProductRequirements - Category: Furniture
Pset_QuantityTakeOff - Reference: FU - 036 1724857
Constraints - Moves With Nearby Elements: no
Dimensions - Area: 1.3248 m2; Volume: 0.11298 m3
Other - Family: FU - 036 1724857: FU - 036 1724857; Family and Type: FU - 036 1724857: FU - 036 1724857; Type: FU - 036 1724857: FU - 036 1724857; Type Id: FU - 036 1724857: FU - 036 1724857
Phasing - Phase Created: New Construction

# IfcFurnishingElement: FU - 036, FU - 036 1725006:FU - 036 1725006:213818
In: Ground Floor
Type - Classification: E2010500 Fixed Multiple Seating (Uniformat); Material: Wood - Pine Grained Horizontal, Paint - Titanium White
Type - Identity Data - Assembly Code: E2010500; Assembly Description: Fixed Multiple Seating; Type Name: FU - 036 1725006
Type - Other - Category: Furniture; Family Name: FU - 036 1725006
Pset_ProductRequirements - Category: Furniture
Pset_QuantityTakeOff - Reference: FU - 036 1725006
Constraints - Moves With Nearby Elements: no
Dimensions - Area: 1.3248 m2; Volume: 0.11298 m3
Other - Family: FU - 036 1725006: FU - 036 1725006; Family and Type: FU - 036 1725006: FU - 036 1725006; Type: FU - 036 1725006: FU - 036 1725006; Type Id: FU - 036 1725006: FU - 036 1725006
Phasing - Phase Created: New Construction

# IfcFurnishingElement: FU - 036, FU - 036 1725155:FU - 036 1725155:213903
In: Ground Floor
Type - Classification: E2010500 Fixed Multiple Seating (Uniformat); Material: Wood - Pine Grained Horizontal, Paint - Titanium White
Type - Identity Data - Assembly Code: E2010500; Assembly Description: Fixed Multiple Seating; Type Name: FU - 036 1725155
Type - Other - Category: Furniture; Family Name: FU - 036 1725155
Pset_ProductRequirements - Category: Furniture
Pset_QuantityTakeOff - Reference: FU - 036 1725155
Constraints - Moves With Nearby Elements: no
Dimensions - Area: 1.3248 m2; Volume: 0.11298 m3
Other - Family: FU - 036 1725155: FU - 036 1725155; Family and Type: FU - 036 1725155: FU - 036 1725155; Type: FU - 036 1725155: FU - 036 1725155; Type Id: FU - 036 1725155: FU - 036 1725155
Phasing - Phase Created: New Construction

# IfcFurnishingElement: FU - 036, FU - 036 1742940:FU - 036 1742940:214687
In: Ground Floor
Type - Classification: E2010500 Fixed Multiple Seating (Uniformat); Material: Wood - Pine Grained Horizontal, Paint - Titanium White
Type - Identity Data - Assembly Code: E2010500; Assembly Description: Fixed Multiple Seating; Type Name: FU - 036 1742940
Type - Other - Category: Furniture; Family Name: FU - 036 1742940
Pset_ProductRequirements - Category: Furniture
Pset_QuantityTakeOff - Reference: FU - 036 1742940
Constraints - Moves With Nearby Elements: no
Dimensions - Area: 1.3248 m2; Volume: 0.11298 m3
Other - Family: FU - 036 1742940: FU - 036 1742940; Family and Type: FU - 036 1742940: FU - 036 1742940; Type: FU - 036 1742940: FU - 036 1742940; Type Id: FU - 036 1742940: FU - 036 1742940
Phasing - Phase Created: New Construction

# IfcFurnishingElement: FU - 036, FU - 036 1751556:FU - 036 1751556:214788
In: Ground Floor
Type - Classification: E2010500 Fixed Multiple Seating (Uniformat); Material: Wood - Pine Grained Horizontal, Paint - Titanium White
Type - Identity Data - Assembly Code: E2010500; Assembly Description: Fixed Multiple Seating; Type Name: FU - 036 1751556
Type - Other - Category: Furniture; Family Name: FU - 036 1751556
Pset_ProductRequirements - Category: Furniture
Pset_QuantityTakeOff - Reference: FU - 036 1751556
Constraints - Moves With Nearby Elements: no
Dimensions - Area: 1.3248 m2; Volume: 0.11298 m3
Other - Family: FU - 036 1751556: FU - 036 1751556; Family and Type: FU - 036 1751556: FU - 036 1751556; Type: FU - 036 1751556: FU - 036 1751556; Type Id: FU - 036 1751556: FU - 036 1751556
Phasing - Phase Created: New Construction

# IfcFurnishingElement: FU - 036, FU - 036 1753317:FU - 036 1753317:214962
In: Ground Floor
Type - Classification: E2010500 Fixed Multiple Seating (Uniformat); Material: Wood - Pine Grained Horizontal, Paint - Titanium White
Type - Identity Data - Assembly Code: E2010500; Assembly Description: Fixed Multiple Seating; Type Name: FU - 036 1753317
Type - Other - Category: Furniture; Family Name: FU - 036 1753317
Pset_ProductRequirements - Category: Furniture
Pset_QuantityTakeOff - Reference: FU - 036 1753317
Constraints - Moves With Nearby Elements: no
Dimensions - Area: 1.3248 m2; Volume: 0.11298 m3
Other - Family: FU - 036 1753317: FU - 036 1753317; Family and Type: FU - 036 1753317: FU - 036 1753317; Type: FU - 036 1753317: FU - 036 1753317; Type Id: FU - 036 1753317: FU - 036 1753317
Phasing - Phase Created: New Construction

# IfcFurnishingElement: FU - 036, FU - 036 1753466:FU - 036 1753466:215047
In: Ground Floor
Type - Classification: E2010500 Fixed Multiple Seating (Uniformat); Material: Wood - Pine Grained Horizontal, Paint - Titanium White
Type - Identity Data - Assembly Code: E2010500; Assembly Description: Fixed Multiple Seating; Type Name: FU - 036 1753466
Type - Other - Category: Furniture; Family Name: FU - 036 1753466
Pset_ProductRequirements - Category: Furniture
Pset_QuantityTakeOff - Reference: FU - 036 1753466
Constraints - Moves With Nearby Elements: no
Dimensions - Area: 1.3248 m2; Volume: 0.11298 m3
Other - Family: FU - 036 1753466: FU - 036 1753466; Family and Type: FU - 036 1753466: FU - 036 1753466; Type: FU - 036 1753466: FU - 036 1753466; Type Id: FU - 036 1753466: FU - 036 1753466
Phasing - Phase Created: New Construction

# IfcFurnishingElement: FU - 036, FU - 036 2102354:FU - 036 2102354:218644
In: Ground Floor
Type - Classification: E2010500 Fixed Multiple Seating (Uniformat); Material: Wood - Pine Grained Horizontal, Paint - Titanium White
Type - Identity Data - Assembly Code: E2010500; Assembly Description: Fixed Multiple Seating; Type Name: FU - 036 2102354
Type - Other - Category: Furniture; Family Name: FU - 036 2102354
Pset_ProductRequirements - Category: Furniture
Pset_QuantityTakeOff - Reference: FU - 036 2102354
Constraints - Moves With Nearby Elements: no
Dimensions - Area: 1.3248 m2; Volume: 0.11298 m3
Other - Family: FU - 036 2102354: FU - 036 2102354; Family and Type: FU - 036 2102354: FU - 036 2102354; Type: FU - 036 2102354: FU - 036 2102354; Type Id: FU - 036 2102354: FU - 036 2102354
Phasing - Phase Created: New Construction

# IfcFurnishingElement: FU - 036, FU - 036 2102503:FU - 036 2102503:218729
In: Ground Floor
Type - Classification: E2010500 Fixed Multiple Seating (Uniformat); Material: Wood - Pine Grained Horizontal, Paint - Titanium White
Type - Identity Data - Assembly Code: E2010500; Assembly Description: Fixed Multiple Seating; Type Name: FU - 036 2102503
Type - Other - Category: Furniture; Family Name: FU - 036 2102503
Pset_ProductRequirements - Category: Furniture
Pset_QuantityTakeOff - Reference: FU - 036 2102503
Constraints - Moves With Nearby Elements: no
Dimensions - Area: 1.3248 m2; Volume: 0.11298 m3
Other - Family: FU - 036 2102503: FU - 036 2102503; Family and Type: FU - 036 2102503: FU - 036 2102503; Type: FU - 036 2102503: FU - 036 2102503; Type Id: FU - 036 2102503: FU - 036 2102503
Phasing - Phase Created: New Construction

# IfcFurnishingElement: FU - 036, FU - 036 2102652:FU - 036 2102652:218814
In: Ground Floor
Type - Classification: E2010500 Fixed Multiple Seating (Uniformat); Material: Wood - Pine Grained Horizontal, Paint - Titanium White
Type - Identity Data - Assembly Code: E2010500; Assembly Description: Fixed Multiple Seating; Type Name: FU - 036 2102652
Type - Other - Category: Furniture; Family Name: FU - 036 2102652
Pset_ProductRequirements - Category: Furniture
Pset_QuantityTakeOff - Reference: FU - 036 2102652
Constraints - Moves With Nearby Elements: no
Dimensions - Area: 1.3248 m2; Volume: 0.11298 m3
Other - Family: FU - 036 2102652: FU - 036 2102652; Family and Type: FU - 036 2102652: FU - 036 2102652; Type: FU - 036 2102652: FU - 036 2102652; Type Id: FU - 036 2102652: FU - 036 2102652
Phasing - Phase Created: New Construction

# IfcFurnishingElement: FU - 036, FU - 036 2102801:FU - 036 2102801:218899
In: Ground Floor
Type - Classification: E2010500 Fixed Multiple Seating (Uniformat); Material: Wood - Pine Grained Horizontal, Paint - Titanium White
Type - Identity Data - Assembly Code: E2010500; Assembly Description: Fixed Multiple Seating; Type Name: FU - 036 2102801
Type - Other - Category: Furniture; Family Name: FU - 036 2102801
Pset_ProductRequirements - Category: Furniture
Pset_QuantityTakeOff - Reference: FU - 036 2102801
Constraints - Moves With Nearby Elements: no
Dimensions - Area: 1.3248 m2; Volume: 0.11298 m3
Other - Family: FU - 036 2102801: FU - 036 2102801; Family and Type: FU - 036 2102801: FU - 036 2102801; Type: FU - 036 2102801: FU - 036 2102801; Type Id: FU - 036 2102801: FU - 036 2102801
Phasing - Phase Created: New Construction

# IfcFurnishingElement: FU - 036, FU - 036 2102950:FU - 036 2102950:218984
In: Ground Floor
Type - Classification: E2010500 Fixed Multiple Seating (Uniformat); Material: Wood - Pine Grained Horizontal, Paint - Titanium White
Type - Identity Data - Assembly Code: E2010500; Assembly Description: Fixed Multiple Seating; Type Name: FU - 036 2102950
Type - Other - Category: Furniture; Family Name: FU - 036 2102950
Pset_ProductRequirements - Category: Furniture
Pset_QuantityTakeOff - Reference: FU - 036 2102950
Constraints - Moves With Nearby Elements: no
Dimensions - Area: 1.3248 m2; Volume: 0.11298 m3
Other - Family: FU - 036 2102950: FU - 036 2102950; Family and Type: FU - 036 2102950: FU - 036 2102950; Type: FU - 036 2102950: FU - 036 2102950; Type Id: FU - 036 2102950: FU - 036 2102950
Phasing - Phase Created: New Construction

# IfcFurnishingElement: FU - 036, FU - 036 2103099:FU - 036 2103099:219069
In: Ground Floor
Type - Classification: E2010500 Fixed Multiple Seating (Uniformat); Material: Wood - Pine Grained Horizontal, Paint - Titanium White
Type - Identity Data - Assembly Code: E2010500; Assembly Description: Fixed Multiple Seating; Type Name: FU - 036 2103099
Type - Other - Category: Furniture; Family Name: FU - 036 2103099
Pset_ProductRequirements - Category: Furniture
Pset_QuantityTakeOff - Reference: FU - 036 2103099
Constraints - Moves With Nearby Elements: no
Dimensions - Area: 1.3248 m2; Volume: 0.11298 m3
Other - Family: FU - 036 2103099: FU - 036 2103099; Family and Type: FU - 036 2103099: FU - 036 2103099; Type: FU - 036 2103099: FU - 036 2103099; Type Id: FU - 036 2103099: FU - 036 2103099
Phasing - Phase Created: New Construction

# IfcFurnishingElement: FU - 036, FU - 036 2103248:FU - 036 2103248:219154
In: Ground Floor
Type - Classification: E2010500 Fixed Multiple Seating (Uniformat); Material: Wood - Pine Grained Horizontal, Paint - Titanium White
Type - Identity Data - Assembly Code: E2010500; Assembly Description: Fixed Multiple Seating; Type Name: FU - 036 2103248
Type - Other - Category: Furniture; Family Name: FU - 036 2103248
Pset_ProductRequirements - Category: Furniture
Pset_QuantityTakeOff - Reference: FU - 036 2103248
Constraints - Moves With Nearby Elements: no
Dimensions - Area: 1.3248 m2; Volume: 0.11298 m3
Other - Family: FU - 036 2103248: FU - 036 2103248; Family and Type: FU - 036 2103248: FU - 036 2103248; Type: FU - 036 2103248: FU - 036 2103248; Type Id: FU - 036 2103248: FU - 036 2103248
Phasing - Phase Created: New Construction

# IfcFurnishingElement: FU - 036, FU - 036 2103397:FU - 036 2103397:219239
In: Ground Floor
Type - Classification: E2010500 Fixed Multiple Seating (Uniformat); Material: Wood - Pine Grained Horizontal, Paint - Titanium White
Type - Identity Data - Assembly Code: E2010500; Assembly Description: Fixed Multiple Seating; Type Name: FU - 036 2103397
Type - Other - Category: Furniture; Family Name: FU - 036 2103397
Pset_ProductRequirements - Category: Furniture
Pset_QuantityTakeOff - Reference: FU - 036 2103397
Constraints - Moves With Nearby Elements: no
Dimensions - Area: 1.3248 m2; Volume: 0.11298 m3
Other - Family: FU - 036 2103397: FU - 036 2103397; Family and Type: FU - 036 2103397: FU - 036 2103397; Type: FU - 036 2103397: FU - 036 2103397; Type Id: FU - 036 2103397: FU - 036 2103397
Phasing - Phase Created: New Construction

# IfcFurnishingElement: FU - 036, FU - 036 2103546:FU - 036 2103546:219324
In: Ground Floor
Type - Classification: E2010500 Fixed Multiple Seating (Uniformat); Material: Wood - Pine Grained Horizontal, Paint - Titanium White
Type - Identity Data - Assembly Code: E2010500; Assembly Description: Fixed Multiple Seating; Type Name: FU - 036 2103546
Type - Other - Category: Furniture; Family Name: FU - 036 2103546
Pset_ProductRequirements - Category: Furniture
Pset_QuantityTakeOff - Reference: FU - 036 2103546
Constraints - Moves With Nearby Elements: no
Dimensions - Area: 1.3248 m2; Volume: 0.11298 m3
Other - Family: FU - 036 2103546: FU - 036 2103546; Family and Type: FU - 036 2103546: FU - 036 2103546; Type: FU - 036 2103546: FU - 036 2103546; Type Id: FU - 036 2103546: FU - 036 2103546
Phasing - Phase Created: New Construction

# IfcFurnishingElement: FU - 036, FU - 036 2103695:FU - 036 2103695:219409
In: Ground Floor
Type - Classification: E2010500 Fixed Multiple Seating (Uniformat); Material: Wood - Pine Grained Horizontal, Paint - Titanium White
Type - Identity Data - Assembly Code: E2010500; Assembly Description: Fixed Multiple Seating; Type Name: FU - 036 2103695
Type - Other - Category: Furniture; Family Name: FU - 036 2103695
Pset_ProductRequirements - Category: Furniture
Pset_QuantityTakeOff - Reference: FU - 036 2103695
Constraints - Moves With Nearby Elements: no
Dimensions - Area: 1.3248 m2; Volume: 0.11298 m3
Other - Family: FU - 036 2103695: FU - 036 2103695; Family and Type: FU - 036 2103695: FU - 036 2103695; Type: FU - 036 2103695: FU - 036 2103695; Type Id: FU - 036 2103695: FU - 036 2103695
Phasing - Phase Created: New Construction

# IfcFurnishingElement: FU - 036, FU - 036 2104376:FU - 036 2104376:219522
In: Ground Floor
Type - Classification: E2010500 Fixed Multiple Seating (Uniformat); Material: Wood - Pine Grained Horizontal, Paint - Titanium White
Type - Identity Data - Assembly Code: E2010500; Assembly Description: Fixed Multiple Seating; Type Name: FU - 036 2104376
Type - Other - Category: Furniture; Family Name: FU - 036 2104376
Pset_ProductRequirements - Category: Furniture
Pset_QuantityTakeOff - Reference: FU - 036 2104376
Constraints - Moves With Nearby Elements: no
Dimensions - Area: 1.3248 m2; Volume: 0.11298 m3
Other - Family: FU - 036 2104376: FU - 036 2104376; Family and Type: FU - 036 2104376: FU - 036 2104376; Type: FU - 036 2104376: FU - 036 2104376; Type Id: FU - 036 2104376: FU - 036 2104376
Phasing - Phase Created: New Construction

# IfcFurnishingElement: FU - 036, FU - 036 2104525:FU - 036 2104525:219607
In: Ground Floor
Type - Classification: E2010500 Fixed Multiple Seating (Uniformat); Material: Wood - Pine Grained Horizontal, Paint - Titanium White
Type - Identity Data - Assembly Code: E2010500; Assembly Description: Fixed Multiple Seating; Type Name: FU - 036 2104525
Type - Other - Category: Furniture; Family Name: FU - 036 2104525
Pset_ProductRequirements - Category: Furniture
Pset_QuantityTakeOff - Reference: FU - 036 2104525
Constraints - Moves With Nearby Elements: no
Dimensions - Area: 1.3248 m2; Volume: 0.11298 m3
Other - Family: FU - 036 2104525: FU - 036 2104525; Family and Type: FU - 036 2104525: FU - 036 2104525; Type: FU - 036 2104525: FU - 036 2104525; Type Id: FU - 036 2104525: FU - 036 2104525
Phasing - Phase Created: New Construction

# IfcFurnishingElement: FU - 036, FU - 036 2104674:FU - 036 2104674:219692
In: Ground Floor
Type - Classification: E2010500 Fixed Multiple Seating (Uniformat); Material: Wood - Pine Grained Horizontal, Paint - Titanium White
Type - Identity Data - Assembly Code: E2010500; Assembly Description: Fixed Multiple Seating; Type Name: FU - 036 2104674
Type - Other - Category: Furniture; Family Name: FU - 036 2104674
Pset_ProductRequirements - Category: Furniture
Pset_QuantityTakeOff - Reference: FU - 036 2104674
Constraints - Moves With Nearby Elements: no
Dimensions - Area: 1.3248 m2; Volume: 0.11298 m3
Other - Family: FU - 036 2104674: FU - 036 2104674; Family and Type: FU - 036 2104674: FU - 036 2104674; Type: FU - 036 2104674: FU - 036 2104674; Type Id: FU - 036 2104674: FU - 036 2104674
Phasing - Phase Created: New Construction

# IfcFurnishingElement: FU - 036, FU - 036 2104823:FU - 036 2104823:219777
In: Ground Floor
Type - Classification: E2010500 Fixed Multiple Seating (Uniformat); Material: Wood - Pine Grained Horizontal, Paint - Titanium White
Type - Identity Data - Assembly Code: E2010500; Assembly Description: Fixed Multiple Seating; Type Name: FU - 036 2104823
Type - Other - Category: Furniture; Family Name: FU - 036 2104823
Pset_ProductRequirements - Category: Furniture
Pset_QuantityTakeOff - Reference: FU - 036 2104823
Constraints - Moves With Nearby Elements: no
Dimensions - Area: 1.3248 m2; Volume: 0.11298 m3
Other - Family: FU - 036 2104823: FU - 036 2104823; Family and Type: FU - 036 2104823: FU - 036 2104823; Type: FU - 036 2104823: FU - 036 2104823; Type Id: FU - 036 2104823: FU - 036 2104823
Phasing - Phase Created: New Construction

# IfcFurnishingElement: FU - 036, FU - 036 2104972:FU - 036 2104972:219862
In: Ground Floor
Type - Classification: E2010500 Fixed Multiple Seating (Uniformat); Material: Wood - Pine Grained Horizontal, Paint - Titanium White
Type - Identity Data - Assembly Code: E2010500; Assembly Description: Fixed Multiple Seating; Type Name: FU - 036 2104972
Type - Other - Category: Furniture; Family Name: FU - 036 2104972
Pset_ProductRequirements - Category: Furniture
Pset_QuantityTakeOff - Reference: FU - 036 2104972
Constraints - Moves With Nearby Elements: no
Dimensions - Area: 1.3248 m2; Volume: 0.11298 m3
Other - Family: FU - 036 2104972: FU - 036 2104972; Family and Type: FU - 036 2104972: FU - 036 2104972; Type: FU - 036 2104972: FU - 036 2104972; Type Id: FU - 036 2104972: FU - 036 2104972
Phasing - Phase Created: New Construction

# IfcFurnishingElement: FU - 036, FU - 036 2105121:FU - 036 2105121:219947
In: Ground Floor
Type - Classification: E2010500 Fixed Multiple Seating (Uniformat); Material: Wood - Pine Grained Horizontal, Paint - Titanium White
Type - Identity Data - Assembly Code: E2010500; Assembly Description: Fixed Multiple Seating; Type Name: FU - 036 2105121
Type - Other - Category: Furniture; Family Name: FU - 036 2105121
Pset_ProductRequirements - Category: Furniture
Pset_QuantityTakeOff - Reference: FU - 036 2105121
Constraints - Moves With Nearby Elements: no
Dimensions - Area: 1.3248 m2; Volume: 0.11298 m3
Other - Family: FU - 036 2105121: FU - 036 2105121; Family and Type: FU - 036 2105121: FU - 036 2105121; Type: FU - 036 2105121: FU - 036 2105121; Type Id: FU - 036 2105121: FU - 036 2105121
Phasing - Phase Created: New Construction

# IfcFurnishingElement: FU - 036, FU - 036 2105270:FU - 036 2105270:220032
In: Ground Floor
Type - Classification: E2010500 Fixed Multiple Seating (Uniformat); Material: Wood - Pine Grained Horizontal, Paint - Titanium White
Type - Identity Data - Assembly Code: E2010500; Assembly Description: Fixed Multiple Seating; Type Name: FU - 036 2105270
Type - Other - Category: Furniture; Family Name: FU - 036 2105270
Pset_ProductRequirements - Category: Furniture
Pset_QuantityTakeOff - Reference: FU - 036 2105270
Constraints - Moves With Nearby Elements: no
Dimensions - Area: 1.3248 m2; Volume: 0.11298 m3
Other - Family: FU - 036 2105270: FU - 036 2105270; Family and Type: FU - 036 2105270: FU - 036 2105270; Type: FU - 036 2105270: FU - 036 2105270; Type Id: FU - 036 2105270: FU - 036 2105270
Phasing - Phase Created: New Construction

# IfcFurnishingElement: FU - 036, FU - 036 2105419:FU - 036 2105419:220117
In: Ground Floor
Type - Classification: E2010500 Fixed Multiple Seating (Uniformat); Material: Wood - Pine Grained Horizontal, Paint - Titanium White
Type - Identity Data - Assembly Code: E2010500; Assembly Description: Fixed Multiple Seating; Type Name: FU - 036 2105419
Type - Other - Category: Furniture; Family Name: FU - 036 2105419
Pset_ProductRequirements - Category: Furniture
Pset_QuantityTakeOff - Reference: FU - 036 2105419
Constraints - Moves With Nearby Elements: no
Dimensions - Area: 1.3248 m2; Volume: 0.11298 m3
Other - Family: FU - 036 2105419: FU - 036 2105419; Family and Type: FU - 036 2105419: FU - 036 2105419; Type: FU - 036 2105419: FU - 036 2105419; Type Id: FU - 036 2105419: FU - 036 2105419
Phasing - Phase Created: New Construction

# IfcFurnishingElement: FU - 036, FU - 036 2105568:FU - 036 2105568:220202
In: Ground Floor
Type - Classification: E2010500 Fixed Multiple Seating (Uniformat); Material: Wood - Pine Grained Horizontal, Paint - Titanium White
Type - Identity Data - Assembly Code: E2010500; Assembly Description: Fixed Multiple Seating; Type Name: FU - 036 2105568
Type - Other - Category: Furniture; Family Name: FU - 036 2105568
Pset_ProductRequirements - Category: Furniture
Pset_QuantityTakeOff - Reference: FU - 036 2105568
Constraints - Moves With Nearby Elements: no
Dimensions - Area: 1.3248 m2; Volume: 0.11298 m3
Other - Family: FU - 036 2105568: FU - 036 2105568; Family and Type: FU - 036 2105568: FU - 036 2105568; Type: FU - 036 2105568: FU - 036 2105568; Type Id: FU - 036 2105568: FU - 036 2105568
Phasing - Phase Created: New Construction

# IfcFurnishingElement: FU - 036, FU - 036 2105717:FU - 036 2105717:220287
In: Ground Floor
Type - Classification: E2010500 Fixed Multiple Seating (Uniformat); Material: Wood - Pine Grained Horizontal, Paint - Titanium White
Type - Identity Data - Assembly Code: E2010500; Assembly Description: Fixed Multiple Seating; Type Name: FU - 036 2105717
Type - Other - Category: Furniture; Family Name: FU - 036 2105717
Pset_ProductRequirements - Category: Furniture
Pset_QuantityTakeOff - Reference: FU - 036 2105717
Constraints - Moves With Nearby Elements: no
Dimensions - Area: 1.3248 m2; Volume: 0.11298 m3
Other - Family: FU - 036 2105717: FU - 036 2105717; Family and Type: FU - 036 2105717: FU - 036 2105717; Type: FU - 036 2105717: FU - 036 2105717; Type Id: FU - 036 2105717: FU - 036 2105717
Phasing - Phase Created: New Construction

# IfcRailing: RAILING - 008, RAILING - 008:RAILING - 008:216431
In: Ground Floor
Type - Classification: C2020300 Stair Handrail & Balustrade Finishes (Uniformat); Material: Metal - Stainless Steel, Paint - Sienna Sand, Glass - Blue
Type - Identity Data - Assembly Code: C2020300; Assembly Description: Stair Handrail & Balustrade Finishes; Type Name: RAILING - 008
Type - Other - Category: Railings; Family Name: RAILING - 008
Type - Pset_ProductRequirements - Category: Railings
Type - Pset_QuantityTakeOff - Reference: RAILING - 008
Type - Pset_RailingCommon - IsExternal: no; Reference: RAILING - 008
Constraints - Moves With Nearby Elements: no
Dimensions - Area: 0.607662 m2; Volume: 0.0889927 m3
Other - Family: RAILING - 008: RAILING - 008; Family and Type: RAILING - 008: RAILING - 008; Type: RAILING - 008: RAILING - 008; Type Id: RAILING - 008: RAILING - 008
Phasing - Phase Created: New Construction

# IfcRailing: RAILING - 008 2099054, RAILING - 008 2099054:RAILING - 008 2099054:218522
In: Ground Floor
Type - Classification: C2020300 Stair Handrail & Balustrade Finishes (Uniformat); Material: Metal - Stainless Steel, Paint - Sienna Sand, Glass - Blue
Type - Identity Data - Assembly Code: C2020300; Assembly Description: Stair Handrail & Balustrade Finishes; Type Name: RAILING - 008 2099054
Type - Other - Category: Railings; Family Name: RAILING - 008 2099054
Type - Pset_ProductRequirements - Category: Railings
Type - Pset_QuantityTakeOff - Reference: RAILING - 008 2099054
Type - Pset_RailingCommon - IsExternal: no; Reference: RAILING - 008 2099054
Constraints - Moves With Nearby Elements: no
Dimensions - Area: 0.607662 m2; Volume: 0.0889927 m3
Other - Family: RAILING - 008 2099054: RAILING - 008 2099054; Family and Type: RAILING - 008 2099054: RAILING - 008 2099054; Type: RAILING - 008 2099054: RAILING - 008 2099054; Type Id: RAILING - 008 2099054: RAILING - 008 2099054
Phasing - Phase Created: New Construction

# IfcRailing: RAILING - 009, RAILING - 009:RAILING - 009:214559
In: -2. Story
Type - Classification: C2020300 Stair Handrail & Balustrade Finishes (Uniformat); Material: Metal - Stainless Steel, Paint - Sienna Sand, Glass - Blue
Type - Identity Data - Assembly Code: C2020300; Assembly Description: Stair Handrail & Balustrade Finishes; Type Name: RAILING - 009
Type - Other - Category: Railings; Family Name: RAILING - 009
Type - Pset_ProductRequirements - Category: Railings
Type - Pset_QuantityTakeOff - Reference: RAILING - 009
Type - Pset_RailingCommon - IsExternal: no; Reference: RAILING - 009
Constraints - Moves With Nearby Elements: no
Dimensions - Area: 5.87491 m2; Volume: 0.0861631 m3
Other - Family: RAILING - 009: RAILING - 009; Family and Type: RAILING - 009: RAILING - 009; Type: RAILING - 009: RAILING - 009; Type Id: RAILING - 009: RAILING - 009
Phasing - Phase Created: New Construction

# IfcRailing: RAILING - 010, RAILING - 010:RAILING - 010:213309
In: -2. Story
Type - Classification: C2020300 Stair Handrail & Balustrade Finishes (Uniformat); Material: Metal - Stainless Steel, Paint - Sienna Sand, Glass - Blue
Type - Identity Data - Assembly Code: C2020300; Assembly Description: Stair Handrail & Balustrade Finishes; Type Name: RAILING - 010
Type - Other - Category: Railings; Family Name: RAILING - 010
Type - Pset_ProductRequirements - Category: Railings
Type - Pset_QuantityTakeOff - Reference: RAILING - 010
Type - Pset_RailingCommon - IsExternal: no; Reference: RAILING - 010
Constraints - Moves With Nearby Elements: no
Dimensions - Area: 5.87491 m2; Volume: 0.0861631 m3
Other - Family: RAILING - 010: RAILING - 010; Family and Type: RAILING - 010: RAILING - 010; Type: RAILING - 010: RAILING - 010; Type Id: RAILING - 010: RAILING - 010
Phasing - Phase Created: New Construction

# IfcRailing: RAILING - 011, RAILING - 011:RAILING - 011:214873
In: -2. Story
Type - Classification: C2020300 Stair Handrail & Balustrade Finishes (Uniformat); Material: Metal - Stainless Steel, Paint - Sienna Sand, Glass - Blue
Type - Identity Data - Assembly Code: C2020300; Assembly Description: Stair Handrail & Balustrade Finishes; Type Name: RAILING - 011
Type - Other - Category: Railings; Family Name: RAILING - 011
Type - Pset_ProductRequirements - Category: Railings
Type - Pset_QuantityTakeOff - Reference: RAILING - 011
Type - Pset_RailingCommon - IsExternal: no; Reference: RAILING - 011
Constraints - Moves With Nearby Elements: no
Dimensions - Area: 5.87491 m2; Volume: 0.0861631 m3
Other - Family: RAILING - 011: RAILING - 011; Family and Type: RAILING - 011: RAILING - 011; Type: RAILING - 011: RAILING - 011; Type Id: RAILING - 011: RAILING - 011
Phasing - Phase Created: New Construction

# IfcRailing: RAILING - 012, RAILING - 012:RAILING - 012:217765
In: -2. Story
Type - Classification: C2020300 Stair Handrail & Balustrade Finishes (Uniformat); Material: Metal - Stainless Steel, Paint - Sienna Sand, Glass - Blue
Type - Identity Data - Assembly Code: C2020300; Assembly Description: Stair Handrail & Balustrade Finishes; Type Name: RAILING - 012
Type - Other - Category: Railings; Family Name: RAILING - 012
Type - Pset_ProductRequirements - Category: Railings
Type - Pset_QuantityTakeOff - Reference: RAILING - 012
Type - Pset_RailingCommon - IsExternal: no; Reference: RAILING - 012
Constraints - Moves With Nearby Elements: no
Dimensions - Area: 5.87491 m2; Volume: 0.0861631 m3
Other - Family: RAILING - 012: RAILING - 012; Family and Type: RAILING - 012: RAILING - 012; Type: RAILING - 012: RAILING - 012; Type Id: RAILING - 012: RAILING - 012
Phasing - Phase Created: New Construction

# IfcRailing: RAILING - 013, RAILING - 013:RAILING - 013:204129
In: -2. Story
Type - Classification: C2020300 Stair Handrail & Balustrade Finishes (Uniformat); Material: Metal - Stainless Steel, Paint - Sienna Sand, Glass - Blue
Type - Identity Data - Assembly Code: C2020300; Assembly Description: Stair Handrail & Balustrade Finishes; Type Name: RAILING - 013
Type - Other - Category: Railings; Family Name: RAILING - 013
Type - Pset_ProductRequirements - Category: Railings
Type - Pset_QuantityTakeOff - Reference: RAILING - 013
Type - Pset_RailingCommon - IsExternal: no; Reference: RAILING - 013
Constraints - Moves With Nearby Elements: no
Dimensions - Area: 5.87491 m2; Volume: 0.0861631 m3
Other - Family: RAILING - 013: RAILING - 013; Family and Type: RAILING - 013: RAILING - 013; Type: RAILING - 013: RAILING - 013; Type Id: RAILING - 013: RAILING - 013
Phasing - Phase Created: New Construction

# IfcRailing: RAILING - 014, RAILING - 014:RAILING - 014:201441
In: -2. Story
Type - Classification: C2020300 Stair Handrail & Balustrade Finishes (Uniformat); Material: Metal - Stainless Steel, Paint - Sienna Sand, Glass - Blue
Type - Identity Data - Assembly Code: C2020300; Assembly Description: Stair Handrail & Balustrade Finishes; Type Name: RAILING - 014
Type - Other - Category: Railings; Family Name: RAILING - 014
Type - Pset_ProductRequirements - Category: Railings
Type - Pset_QuantityTakeOff - Reference: RAILING - 014
Type - Pset_RailingCommon - IsExternal: no; Reference: RAILING - 014
Constraints - Moves With Nearby Elements: no
Dimensions - Area: 5.87491 m2; Volume: 0.0861631 m3
Other - Family: RAILING - 014: RAILING - 014; Family and Type: RAILING - 014: RAILING - 014; Type: RAILING - 014: RAILING - 014; Type Id: RAILING - 014: RAILING - 014
Phasing - Phase Created: New Construction

# IfcRailing: RAILING - 015, RAILING - 015:RAILING - 015:201350
In: -2. Story
Type - Classification: C2020300 Stair Handrail & Balustrade Finishes (Uniformat); Material: Metal - Stainless Steel, Paint - Sienna Sand, Glass - Blue
Type - Identity Data - Assembly Code: C2020300; Assembly Description: Stair Handrail & Balustrade Finishes; Type Name: RAILING - 015
Type - Other - Category: Railings; Family Name: RAILING - 015
Type - Pset_ProductRequirements - Category: Railings
Type - Pset_QuantityTakeOff - Reference: RAILING - 015
Type - Pset_RailingCommon - IsExternal: no; Reference: RAILING - 015
Constraints - Moves With Nearby Elements: no
Dimensions - Area: 5.87491 m2; Volume: 0.0861631 m3
Other - Family: RAILING - 015: RAILING - 015; Family and Type: RAILING - 015: RAILING - 015; Type: RAILING - 015: RAILING - 015; Type Id: RAILING - 015: RAILING - 015
Phasing - Phase Created: New Construction

# IfcRailing: RAILING - 016, RAILING - 016:RAILING - 016:201892
In: -2. Story
Type - Classification: C2020300 Stair Handrail & Balustrade Finishes (Uniformat); Material: Metal - Stainless Steel, Paint - Sienna Sand, Glass - Blue
Type - Identity Data - Assembly Code: C2020300; Assembly Description: Stair Handrail & Balustrade Finishes; Type Name: RAILING - 016
Type - Other - Category: Railings; Family Name: RAILING - 016
Type - Pset_ProductRequirements - Category: Railings
Type - Pset_QuantityTakeOff - Reference: RAILING - 016
Type - Pset_RailingCommon - IsExternal: no; Reference: RAILING - 016
Constraints - Moves With Nearby Elements: no
Dimensions - Area: 5.87491 m2; Volume: 0.0861631 m3
Other - Family: RAILING - 016: RAILING - 016; Family and Type: RAILING - 016: RAILING - 016; Type: RAILING - 016: RAILING - 016; Type Id: RAILING - 016: RAILING - 016
Phasing - Phase Created: New Construction

# IfcRailing: RAILING - 017, RAILING - 017:RAILING - 017:202033
In: Ground Floor
Type - Classification: C2020300 Stair Handrail & Balustrade Finishes (Uniformat); Material: Metal - Stainless Steel, Paint - Sienna Sand, Glass - Blue
Type - Identity Data - Assembly Code: C2020300; Assembly Description: Stair Handrail & Balustrade Finishes; Type Name: RAILING - 017
Type - Other - Category: Railings; Family Name: RAILING - 017
Type - Pset_ProductRequirements - Category: Railings
Type - Pset_QuantityTakeOff - Reference: RAILING - 017
Type - Pset_RailingCommon - IsExternal: no; Reference: RAILING - 017
Constraints - Moves With Nearby Elements: no
Dimensions - Area: 0.614815 m2; Volume: 0.0900318 m3
Other - Family: RAILING - 017: RAILING - 017; Family and Type: RAILING - 017: RAILING - 017; Type: RAILING - 017: RAILING - 017; Type Id: RAILING - 017: RAILING - 017
Phasing - Phase Created: New Construction

# IfcRailing: RAILING - 018, RAILING - 018:RAILING - 018:204016
In: Ground Floor
Type - Classification: C2020300 Stair Handrail & Balustrade Finishes (Uniformat); Material: Metal - Stainless Steel, Paint - Sienna Sand, Glass - Blue
Type - Identity Data - Assembly Code: C2020300; Assembly Description: Stair Handrail & Balustrade Finishes; Type Name: RAILING - 018
Type - Other - Category: Railings; Family Name: RAILING - 018
Type - Pset_ProductRequirements - Category: Railings
Type - Pset_QuantityTakeOff - Reference: RAILING - 018
Type - Pset_RailingCommon - IsExternal: no; Reference: RAILING - 018
Constraints - Moves With Nearby Elements: no
Dimensions - Area: 0.607662 m2; Volume: 0.0889927 m3
Other - Family: RAILING - 018: RAILING - 018; Family and Type: RAILING - 018: RAILING - 018; Type: RAILING - 018: RAILING - 018; Type Id: RAILING - 018: RAILING - 018
Phasing - Phase Created: New Construction

# IfcRoof: SHELL - 002 2236473:SHELL - 002 2236473, SHELL - 002 2236473:SHELL - 002 2236473:220509
In: Ground Floor
Material: Glass - Blue
Other(Type) - Category: Roofs; Family Name: SHELL - 002 2236473
Identity Data(Type) - Type Name: SHELL - 002 2236473
Pset_ProductRequirements - Category: Roofs
Pset_QuantityTakeOff - Reference: SHELL - 002 2236473
Pset_RoofCommon - IsExternal: yes; Reference: SHELL - 002 2236473; TotalArea: 2994.08 m2
Constraints - Moves With Nearby Elements: no; Room Bounding: yes; Elevation: 0 mm
Dimensions - Area: 2994.08 m2; Volume: 174.165 m3
Other - Category: Roofs; Family: SHELL - 002 2236473: SHELL - 002 2236473; Family and Type: SHELL - 002 2236473: SHELL - 002 2236473; Type: SHELL - 002 2236473: SHELL - 002 2236473; Type Id: SHELL - 002 2236473: SHELL - 002 2236473
Phasing - Phase Created: New Construction

# IfcRoof: SHELL - 002:SHELL - 002, SHELL - 002:SHELL - 002:216571
In: Ground Floor
Classification: B1020600 Dome Construction (Uniformat); Material: Paint - Dark Gray
Other(Type) - Category: Roofs; Family Name: SHELL - 002
Identity Data(Type) - Assembly Code: B1020600; Assembly Description: Dome Construction; Type Name: SHELL - 002
Pset_ProductRequirements - Category: Roofs
Pset_QuantityTakeOff - Reference: SHELL - 002
Pset_RoofCommon - Reference: SHELL - 002; IsExternal: yes; TotalArea: 4135.31 m2
Constraints - Moves With Nearby Elements: no; Room Bounding: yes
Dimensions - Area: 4135.31 m2; Volume: 745.25 m3
Other - Category: Roofs; Family: SHELL - 002: SHELL - 002; Family and Type: SHELL - 002: SHELL - 002; Type: SHELL - 002: SHELL - 002; Type Id: SHELL - 002: SHELL - 002
Phasing - Phase Created: New Construction

# IfcSlab: SLA - 012, SLA - 012:SLA - 012:215390
In: -1. Story
Type - PredefinedType: FLOOR; Material: Paint - Light Gray
Type - Identity Data - Assembly Code: G2010200; Assembly Description: Roadway Paving & Surfacing; Type Name: SLA - 012
Type - Other - Category: Floors; Family Name: SLA - 012
Type - Pset_ProductRequirements - Category: Floors
Type - Pset_QuantityTakeOff - Reference: SLA - 012
Type - Pset_ReinforcementBarPitchOfSlab - Reference: SLA - 012
Type - Pset_SlabCommon - IsExternal: no; Reference: SLA - 012
Classification: G2010200 Roadway Paving & Surfacing (Uniformat)
Pset_QuantityTakeOff - sets with these values: 2
Pset_SlabCommon - PitchAngle: 0 deg
BaseQuantities - GrossArea: 2947.76 m2; NetArea: 6038.13 m2; GrossVolume: 589553 m3; NetVolume: 589.553 m3; Perimeter: 422675 mm; Width: 200 mm
Constraints - Moves With Nearby Elements: no; Room Bounding: yes
Dimensions - Area: 2947.76 m2; Volume: 589.553 m3
Other - Family: SLA - 012: SLA - 012; Family and Type: SLA - 012: SLA - 012; Type: SLA - 012: SLA - 012; Type Id: SLA - 012: SLA - 012
Phasing - Phase Created: New Construction

# IfcStair: SF STRUCTURE - 009 1403154:SF STRUCTURE - 009 1403154 (2)
In: -2. Story
Name (SF STRUCTURE - 009 1403154:SF STRUCTURE - 009 1403154:...)
202022 | Material: Metal - Stainless Steel
202022 | Classification: C2010130 Stairs - Steel (Uniformat); Pset_ProductRequirements - Category: Stairs; Pset_QuantityTakeOff - Reference: SF STRUCTURE - 009 1403154; Pset_StairCommon - IsExternal: no; Reference: SF STRUCTURE - 009 1403154; NumberOfTreads: 0; Constraints - Moves With Nearby Elements: no; Dimensions - Area: 6.01533 m2; Volume: 0.016782 m3; Other - Category: Stairs; Family: SF STRUCTURE - 009 1403154: SF STRUCTURE - 009 1403154; Family and Type: SF STRUCTURE - 009 1403154: SF STRUCTURE - 009 1403154; Type: SF STRUCTURE - 009 1403154: SF STRUCTURE - 009 1403154; Type Id: SF STRUCTURE - 009 1403154: SF STRUCTURE - 009 1403154; Phasing - Phase Created: New Construction; Other(Type) - Category: Stairs; Family Name: SF STRUCTURE - 009 1403154; Identity Data(Type) - Assembly Code: C2010130; Assembly Description: Stairs - Steel; Type Name: SF STRUCTURE - 009 1403154

# IfcStair: SF STRUCTURE - 009 1421386:SF STRUCTURE - 009 1421386 (2)
In: -2. Story
Name (SF STRUCTURE - 009 1421386:SF STRUCTURE - 009 1421386:...)
202222 | Material: Metal - Stainless Steel
202222 | Classification: C2010130 Stairs - Steel (Uniformat); Pset_ProductRequirements - Category: Stairs; Pset_QuantityTakeOff - Reference: SF STRUCTURE - 009 1421386; Pset_StairCommon - IsExternal: no; Reference: SF STRUCTURE - 009 1421386; NumberOfTreads: 0; Constraints - Moves With Nearby Elements: no; Dimensions - Area: 1.44533 m2; Volume: 0.0382545 m3; Other - Category: Stairs; Family: SF STRUCTURE - 009 1421386: SF STRUCTURE - 009 1421386; Family and Type: SF STRUCTURE - 009 1421386: SF STRUCTURE - 009 1421386; Type: SF STRUCTURE - 009 1421386: SF STRUCTURE - 009 1421386; Type Id: SF STRUCTURE - 009 1421386: SF STRUCTURE - 009 1421386; Phasing - Phase Created: New Construction; Other(Type) - Category: Stairs; Family Name: SF STRUCTURE - 009 1421386; Identity Data(Type) - Assembly Code: C2010130; Assembly Description: Stairs - Steel; Type Name: SF STRUCTURE - 009 1421386

# IfcStair: SF STRUCTURE - 009 1443134:SF STRUCTURE - 009 1443134 (2)
In: -2. Story
Name (SF STRUCTURE - 009 1443134:SF STRUCTURE - 009 1443134:...)
202666 | Material: Metal - Stainless Steel
202666 | Classification: C2010130 Stairs - Steel (Uniformat); Pset_ProductRequirements - Category: Stairs; Pset_QuantityTakeOff - Reference: SF STRUCTURE - 009 1443134; Pset_StairCommon - IsExternal: no; Reference: SF STRUCTURE - 009 1443134; NumberOfTreads: 0; Constraints - Moves With Nearby Elements: no; Dimensions - Area: 6.01533 m2; Volume: 0.016782 m3; Other - Category: Stairs; Family: SF STRUCTURE - 009 1443134: SF STRUCTURE - 009 1443134; Family and Type: SF STRUCTURE - 009 1443134: SF STRUCTURE - 009 1443134; Type: SF STRUCTURE - 009 1443134: SF STRUCTURE - 009 1443134; Type Id: SF STRUCTURE - 009 1443134: SF STRUCTURE - 009 1443134; Phasing - Phase Created: New Construction; Other(Type) - Category: Stairs; Family Name: SF STRUCTURE - 009 1443134; Identity Data(Type) - Assembly Code: C2010130; Assembly Description: Stairs - Steel; Type Name: SF STRUCTURE - 009 1443134

# IfcStair: SF STRUCTURE - 009:SF STRUCTURE - 009 (2)
In: -2. Story
Name (SF STRUCTURE - 009:SF STRUCTURE - 009:...)
201592 | Material: Metal - Stainless Steel
201592 | Classification: C2010130 Stairs - Steel (Uniformat); Pset_ProductRequirements - Category: Stairs; Pset_QuantityTakeOff - Reference: SF STRUCTURE - 009; Pset_StairCommon - IsExternal: no; Reference: SF STRUCTURE - 009; NumberOfTreads: 0; Constraints - Moves With Nearby Elements: no; Dimensions - Area: 1.44533 m2; Volume: 0.0382545 m3; Other - Category: Stairs; Family: SF STRUCTURE - 009: SF STRUCTURE - 009; Family and Type: SF STRUCTURE - 009: SF STRUCTURE - 009; Type: SF STRUCTURE - 009: SF STRUCTURE - 009; Type Id: SF STRUCTURE - 009: SF STRUCTURE - 009; Phasing - Phase Created: New Construction; Other(Type) - Category: Stairs; Family Name: SF STRUCTURE - 009; Identity Data(Type) - Assembly Code: C2010130; Assembly Description: Stairs - Steel; Type Name: SF STRUCTURE - 009

# IfcStair: SF TREAD - 099 1406281:SF TREAD - 099 1406281 (2)
In: -2. Story
Name (SF TREAD - 099 1406281:SF TREAD - 099 1406281:...)
201981 | Material: Metal - Stainless Steel
201981 | Classification: C2010130 Stairs - Steel (Uniformat); Pset_ProductRequirements - Category: Stairs; Pset_QuantityTakeOff - Reference: SF TREAD - 099 1406281; Pset_StairCommon - IsExternal: no; Reference: SF TREAD - 099 1406281; NumberOfTreads: 0; Constraints - Moves With Nearby Elements: no; Dimensions - Area: 5.68066 m2; Volume: 0.129441 m3; Other - Category: Stairs; Family: SF TREAD - 099 1406281: SF TREAD - 099 1406281; Family and Type: SF TREAD - 099 1406281: SF TREAD - 099 1406281; Type: SF TREAD - 099 1406281: SF TREAD - 099 1406281; Type Id: SF TREAD - 099 1406281: SF TREAD - 099 1406281; Phasing - Phase Created: New Construction; Other(Type) - Category: Stairs; Family Name: SF TREAD - 099 1406281; Identity Data(Type) - Assembly Code: C2010130; Assembly Description: Stairs - Steel; Type Name: SF TREAD - 099 1406281

# IfcStair: SF TREAD - 099 1424513:SF TREAD - 099 1424513 (2)
In: -2. Story
Name (SF TREAD - 099 1424513:SF TREAD - 099 1424513:...)
202181 | Material: Metal - Stainless Steel
202181 | Classification: C2010130 Stairs - Steel (Uniformat); Pset_ProductRequirements - Category: Stairs; Pset_QuantityTakeOff - Reference: SF TREAD - 099 1424513; Pset_StairCommon - IsExternal: no; Reference: SF TREAD - 099 1424513; NumberOfTreads: 0; Constraints - Moves With Nearby Elements: no; Dimensions - Area: 5.68066 m2; Volume: 0.129441 m3; Other - Category: Stairs; Family: SF TREAD - 099 1424513: SF TREAD - 099 1424513; Family and Type: SF TREAD - 099 1424513: SF TREAD - 099 1424513; Type: SF TREAD - 099 1424513: SF TREAD - 099 1424513; Type Id: SF TREAD - 099 1424513: SF TREAD - 099 1424513; Phasing - Phase Created: New Construction; Other(Type) - Category: Stairs; Family Name: SF TREAD - 099 1424513; Identity Data(Type) - Assembly Code: C2010130; Assembly Description: Stairs - Steel; Type Name: SF TREAD - 099 1424513

# IfcStair: SF TREAD - 099 1446261:SF TREAD - 099 1446261 (2)
In: -2. Story
Name (SF TREAD - 099 1446261:SF TREAD - 099 1446261:...)
202625 | Material: Metal - Stainless Steel
202625 | Classification: C2010130 Stairs - Steel (Uniformat); Pset_ProductRequirements - Category: Stairs; Pset_QuantityTakeOff - Reference: SF TREAD - 099 1446261; Pset_StairCommon - IsExternal: no; Reference: SF TREAD - 099 1446261; NumberOfTreads: 0; Constraints - Moves With Nearby Elements: no; Dimensions - Area: 5.68066 m2; Volume: 0.129441 m3; Other - Category: Stairs; Family: SF TREAD - 099 1446261: SF TREAD - 099 1446261; Family and Type: SF TREAD - 099 1446261: SF TREAD - 099 1446261; Type: SF TREAD - 099 1446261: SF TREAD - 099 1446261; Type Id: SF TREAD - 099 1446261: SF TREAD - 099 1446261; Phasing - Phase Created: New Construction; Other(Type) - Category: Stairs; Family Name: SF TREAD - 099 1446261; Identity Data(Type) - Assembly Code: C2010130; Assembly Description: Stairs - Steel; Type Name: SF TREAD - 099 1446261

# IfcStair: SF TREAD - 099:SF TREAD - 099 (2)
In: -2. Story
Name (SF TREAD - 099:SF TREAD - 099:...)
201530 | Material: Metal - Stainless Steel
201530 | Classification: C2010130 Stairs - Steel (Uniformat); Pset_ProductRequirements - Category: Stairs; Pset_QuantityTakeOff - Reference: SF TREAD - 099; Pset_StairCommon - Reference: SF TREAD - 099; NumberOfTreads: 0; IsExternal: no; Constraints - Moves With Nearby Elements: no; Dimensions - Area: 5.68066 m2; Volume: 0.129441 m3; Other - Category: Stairs; Family: SF TREAD - 099: SF TREAD - 099; Family and Type: SF TREAD - 099: SF TREAD - 099; Type: SF TREAD - 099: SF TREAD - 099; Type Id: SF TREAD - 099: SF TREAD - 099; Phasing - Phase Created: New Construction; Other(Type) - Category: Stairs; Family Name: SF TREAD - 099; Identity Data(Type) - Assembly Code: C2010130; Assembly Description: Stairs - Steel; Type Name: SF TREAD - 099

# IfcWall: CW-002, CW-002:CW-002:214309
In: Ground Floor
Type - Material: Metal - Stainless Steel
Type - Identity Data - Assembly Code: C1010130; Assembly Description: Partitions - Glass Block; Type Name: CW-002
Type - Other - Category: Walls; Family Name: CW-002
Type - Pset_ProductRequirements - Category: Walls
Type - Pset_QuantityTakeOff - Reference: CW-002
Type - Pset_ReinforcementBarPitchOfWall - Reference: CW-002
Type - Pset_WallCommon - IsExternal: no; Reference: CW-002
Classification: C1010130 Partitions - Glass Block (Uniformat)
Constraints - Moves With Nearby Elements: no; Room Bounding: yes
Dimensions - Area: 10.0625 m2; Volume: 1.49984 m3
Other - Family: CW-002: CW-002; Family and Type: CW-002: CW-002; Type: CW-002: CW-002; Type Id: CW-002: CW-002
Phasing - Phase Created: New Construction
Pset_QuantityTakeOff - sets with these values: 2

# IfcWall: CW-002 2, CW-002 2:CW-002 2:215130
In: Ground Floor
Type - Material: Metal - Stainless Steel
Type - Identity Data - Assembly Code: C1010130; Assembly Description: Partitions - Glass Block; Type Name: CW-002 2
Type - Other - Category: Walls; Family Name: CW-002 2
Type - Pset_ProductRequirements - Category: Walls
Type - Pset_QuantityTakeOff - Reference: CW-002 2
Type - Pset_ReinforcementBarPitchOfWall - Reference: CW-002 2
Type - Pset_WallCommon - IsExternal: no; Reference: CW-002 2
Classification: C1010130 Partitions - Glass Block (Uniformat)
Constraints - Moves With Nearby Elements: no; Room Bounding: yes
Dimensions - Area: 29.1804 m2; Volume: 1.72649 m3
Other - Family: CW-002 2: CW-002 2; Family and Type: CW-002 2: CW-002 2; Type: CW-002 2: CW-002 2; Type Id: CW-002 2: CW-002 2
Phasing - Phase Created: New Construction
Pset_QuantityTakeOff - sets with these values: 2

# IfcWall: CW-002 3, CW-002 3:CW-002 3:216931
In: Ground Floor
Type - Material: Metal - Stainless Steel
Type - Identity Data - Assembly Code: B2020200; Assembly Description: Curtain Walls; Type Name: CW-002 3
Type - Other - Category: Walls; Family Name: CW-002 3
Type - Pset_ProductRequirements - Category: Walls
Type - Pset_QuantityTakeOff - Reference: CW-002 3
Type - Pset_ReinforcementBarPitchOfWall - Reference: CW-002 3
Type - Pset_WallCommon - IsExternal: no; Reference: CW-002 3
Classification: B2020200 Curtain Walls (Uniformat)
Constraints - Moves With Nearby Elements: no; Room Bounding: yes
Dimensions - Area: 98.8157 m2; Volume: 68.5804 m3
Other - Family: CW-002 3: CW-002 3; Family and Type: CW-002 3: CW-002 3; Type: CW-002 3: CW-002 3; Type Id: CW-002 3: CW-002 3
Phasing - Phase Created: New Construction
Pset_QuantityTakeOff - sets with these values: 2

# IfcWall: CW-002 4, CW-002 4:CW-002 4:217852
In: Ground Floor
Type - Material: Glass - Blue
Type - Identity Data - Assembly Code: C1010130; Assembly Description: Partitions - Glass Block; Type Name: CW-002 4
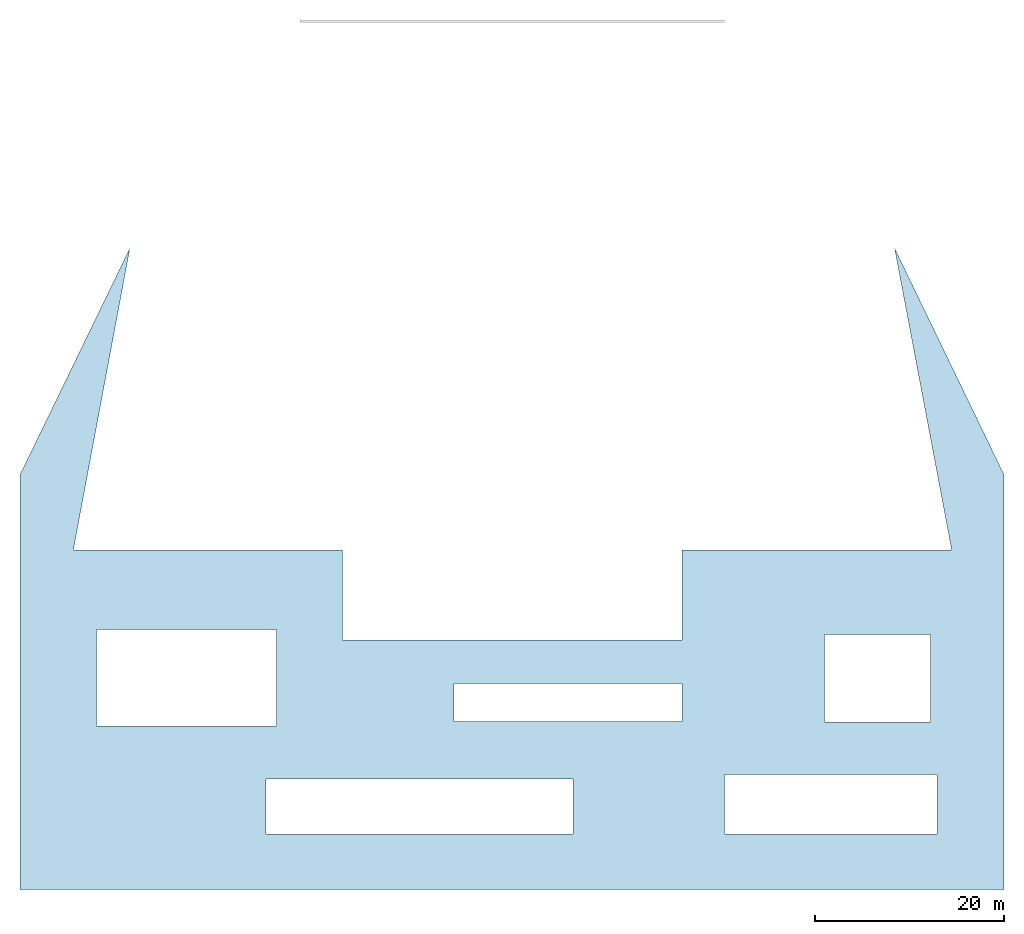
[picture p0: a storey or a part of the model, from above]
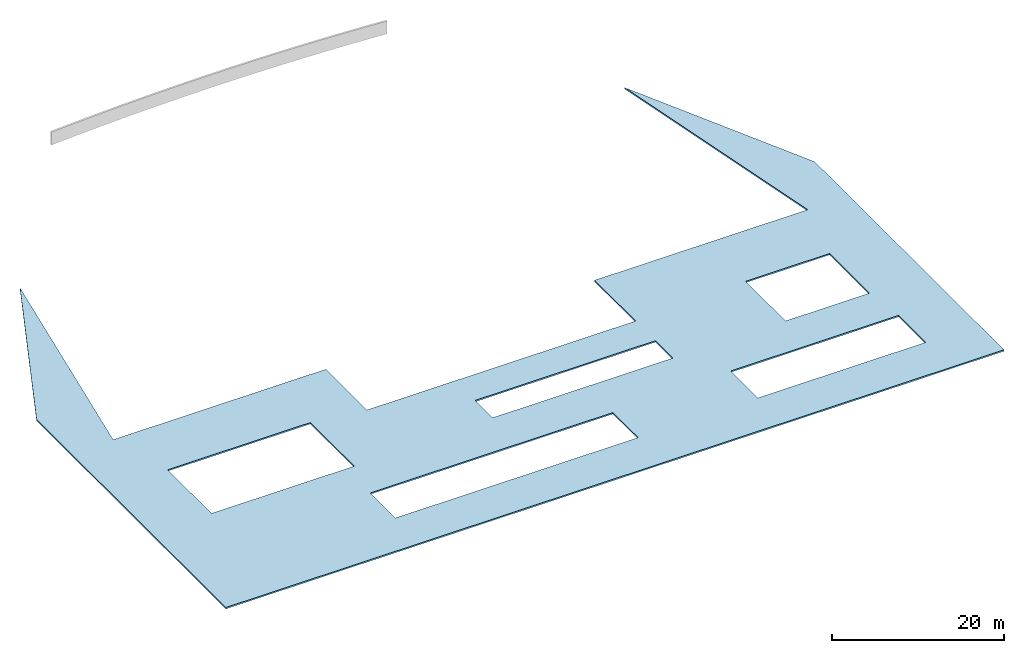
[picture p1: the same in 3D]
Properties of the parts of a building model (IFC2X3), part 4 of 4

# IfcWall: CW-002 4, CW-002 4:CW-002 4:217852
Type - Other - Category: Walls; Family Name: CW-002 4
Type - Pset_ProductRequirements - Category: Walls
Type - Pset_QuantityTakeOff - Reference: CW-002 4
Type - Pset_ReinforcementBarPitchOfWall - Reference: CW-002 4
Type - Pset_WallCommon - IsExternal: no; Reference: CW-002 4
Classification: C1010130 Partitions - Glass Block (Uniformat)
Constraints - Moves With Nearby Elements: no; Room Bounding: yes
Dimensions - Area: 40.1885 m2; Volume: 11.9557 m3
Other - Family: CW-002 4: CW-002 4; Family and Type: CW-002 4: CW-002 4; Type: CW-002 4: CW-002 4; Type Id: CW-002 4: CW-002 4
Phasing - Phase Created: New Construction
Pset_QuantityTakeOff - sets with these values: 2

# IfcWall: CW-005, CW-005:CW-005:220377
In: 1. Story
Type - Material: Glass - Blue
Type - Identity Data - Assembly Code: C1010130; Assembly Description: Partitions - Glass Block; Type Name: CW-005
Type - Other - Category: Walls; Family Name: CW-005
Type - Pset_ProductRequirements - Category: Walls
Type - Pset_QuantityTakeOff - Reference: CW-005
Type - Pset_ReinforcementBarPitchOfWall - Reference: CW-005
Type - Pset_WallCommon - IsExternal: no; Reference: CW-005
Classification: C1010130 Partitions - Glass Block (Uniformat)
Constraints - Moves With Nearby Elements: no; Room Bounding: yes
Dimensions - Area: 73.1898 m2; Volume: 4.05205 m3
Other - Family: CW-005: CW-005; Family and Type: CW-005: CW-005; Type: CW-005: CW-005; Type Id: CW-005: CW-005
Phasing - Phase Created: New Construction
Pset_QuantityTakeOff - sets with these values: 2

# IfcWall: CW-005 2, CW-005 2:CW-005 2:220421
In: 1. Story
Type - Material: Glass - Blue
Type - Identity Data - Assembly Code: C1010130; Assembly Description: Partitions - Glass Block; Type Name: CW-005 2
Type - Other - Category: Walls; Family Name: CW-005 2
Type - Pset_ProductRequirements - Category: Walls
Type - Pset_QuantityTakeOff - Reference: CW-005 2
Type - Pset_ReinforcementBarPitchOfWall - Reference: CW-005 2
Type - Pset_WallCommon - IsExternal: no; Reference: CW-005 2
Classification: C1010130 Partitions - Glass Block (Uniformat)
Constraints - Moves With Nearby Elements: no; Room Bounding: yes
Dimensions - Area: 73.1898 m2; Volume: 3.73183 m3
Other - Family: CW-005 2: CW-005 2; Family and Type: CW-005 2: CW-005 2; Type: CW-005 2: CW-005 2; Type Id: CW-005 2: CW-005 2
Phasing - Phase Created: New Construction
Pset_QuantityTakeOff - sets with these values: 2

# IfcWall: SW - 008, SW - 008:SW - 008:202677
In: -2. Story
Type - Material: Stucco - White Fine
Type - Identity Data - Assembly Code: C1010110; Assembly Description: Partitions - Brick, Solid; Type Name: SW - 008
Type - Other - Category: Walls; Family Name: SW - 008
Type - Pset_ProductRequirements - Category: Walls
Type - Pset_QuantityTakeOff - Reference: SW - 008
Type - Pset_ReinforcementBarPitchOfWall - Reference: SW - 008
Type - Pset_WallCommon - IsExternal: no; Reference: SW - 008
Classification: C1010110 Partitions - Brick, Solid (Uniformat)
Constraints - Moves With Nearby Elements: no; Room Bounding: yes
Dimensions - Area: 6.55 m2; Volume: 17.7505 m3
Other - Family: SW - 008: SW - 008; Family and Type: SW - 008: SW - 008; Type: SW - 008: SW - 008; Type Id: SW - 008: SW - 008
Phasing - Phase Created: New Construction
Pset_QuantityTakeOff - sets with these values: 2

# IfcWall: SW - 013, SW - 013:SW - 013:204396
In: -2. Story
Type - Material: Stucco - White Fine
Type - Identity Data - Assembly Code: C1010110; Assembly Description: Partitions - Brick, Solid; Type Name: SW - 013
Type - Other - Category: Walls; Family Name: SW - 013
Type - Pset_ProductRequirements - Category: Walls
Type - Pset_QuantityTakeOff - Reference: SW - 013
Type - Pset_ReinforcementBarPitchOfWall - Reference: SW - 013
Type - Pset_WallCommon - IsExternal: no; Reference: SW - 013
Classification: C1010110 Partitions - Brick, Solid (Uniformat)
Constraints - Moves With Nearby Elements: no; Room Bounding: yes
Dimensions - Area: 4.06731 m2; Volume: 11.0224 m3
Other - Family: SW - 013: SW - 013; Family and Type: SW - 013: SW - 013; Type: SW - 013: SW - 013; Type Id: SW - 013: SW - 013
Phasing - Phase Created: New Construction
Pset_QuantityTakeOff - sets with these values: 2

# IfcWall: SW - 013, SW - 013 1489415:SW - 013 1489415:204454
In: -2. Story
Type - Material: Stucco - White Fine
Type - Identity Data - Assembly Code: C1010110; Assembly Description: Partitions - Brick, Solid; Type Name: SW - 013 1489415
Type - Other - Category: Walls; Family Name: SW - 013 1489415
Type - Pset_ProductRequirements - Category: Walls
Type - Pset_QuantityTakeOff - Reference: SW - 013 1489415
Type - Pset_ReinforcementBarPitchOfWall - Reference: SW - 013 1489415
Type - Pset_WallCommon - IsExternal: no; Reference: SW - 013 1489415
Classification: C1010110 Partitions - Brick, Solid (Uniformat)
Constraints - Moves With Nearby Elements: no; Room Bounding: yes
Dimensions - Area: 1.782 m2; Volume: 4.82923 m3
Other - Family: SW - 013 1489415: SW - 013 1489415; Family and Type: SW - 013 1489415: SW - 013 1489415; Type: SW - 013 1489415: SW - 013 1489415; Type Id: SW - 013 1489415: SW - 013 1489415
Phasing - Phase Created: New Construction
Pset_QuantityTakeOff - sets with these values: 2

# IfcWall: SW - 013, SW - 013 1576260:SW - 013 1576260:208693
In: -2. Story
Type - Material: Stucco - White Fine
Type - Identity Data - Assembly Code: C1010110; Assembly Description: Partitions - Brick, Solid; Type Name: SW - 013 1576260
Type - Other - Category: Walls; Family Name: SW - 013 1576260
Type - Pset_ProductRequirements - Category: Walls
Type - Pset_QuantityTakeOff - Reference: SW - 013 1576260
Type - Pset_ReinforcementBarPitchOfWall - Reference: SW - 013 1576260
Type - Pset_WallCommon - IsExternal: no; Reference: SW - 013 1576260
Classification: C1010110 Partitions - Brick, Solid (Uniformat)
Constraints - Moves With Nearby Elements: no; Room Bounding: yes
Dimensions - Area: 4.06731 m2; Volume: 11.0224 m3
Other - Family: SW - 013 1576260: SW - 013 1576260; Family and Type: SW - 013 1576260: SW - 013 1576260; Type: SW - 013 1576260: SW - 013 1576260; Type Id: SW - 013 1576260: SW - 013 1576260
Phasing - Phase Created: New Construction
Pset_QuantityTakeOff - sets with these values: 2

# IfcWall: SW - 013, SW - 013 1576978:SW - 013 1576978:208751
In: -2. Story
Type - Material: Stucco - White Fine
Type - Identity Data - Assembly Code: C1010110; Assembly Description: Partitions - Brick, Solid; Type Name: SW - 013 1576978
Type - Other - Category: Walls; Family Name: SW - 013 1576978
Type - Pset_ProductRequirements - Category: Walls
Type - Pset_QuantityTakeOff - Reference: SW - 013 1576978
Type - Pset_ReinforcementBarPitchOfWall - Reference: SW - 013 1576978
Type - Pset_WallCommon - IsExternal: no; Reference: SW - 013 1576978
Classification: C1010110 Partitions - Brick, Solid (Uniformat)
Constraints - Moves With Nearby Elements: no; Room Bounding: yes
Dimensions - Area: 1.782 m2; Volume: 4.82923 m3
Other - Family: SW - 013 1576978: SW - 013 1576978; Family and Type: SW - 013 1576978: SW - 013 1576978; Type: SW - 013 1576978: SW - 013 1576978; Type Id: SW - 013 1576978: SW - 013 1576978
Phasing - Phase Created: New Construction
Pset_QuantityTakeOff - sets with these values: 2

# IfcWall: SW - 014, SW - 014:SW - 014:204709
In: -2. Story
Type - Material: Stucco - White Fine
Type - Identity Data - Assembly Code: C1010110; Assembly Description: Partitions - Brick, Solid; Type Name: SW - 014
Type - Other - Category: Walls; Family Name: SW - 014
Type - Pset_ProductRequirements - Category: Walls
Type - Pset_QuantityTakeOff - Reference: SW - 014
Type - Pset_ReinforcementBarPitchOfWall - Reference: SW - 014
Type - Pset_WallCommon - IsExternal: no; Reference: SW - 014
Classification: C1010110 Partitions - Brick, Solid (Uniformat)
Constraints - Moves With Nearby Elements: no; Room Bounding: yes
Dimensions - Area: 0.687472 m2; Volume: 1.74253 m3
Other - Family: SW - 014: SW - 014; Family and Type: SW - 014: SW - 014; Type: SW - 014: SW - 014; Type Id: SW - 014: SW - 014
Phasing - Phase Created: New Construction
Pset_QuantityTakeOff - sets with these values: 2

# IfcWall: SW - 014, SW - 014 1585887:SW - 014 1585887:208837
In: -2. Story
Type - Material: Stucco - White Fine
Type - Identity Data - Assembly Code: C1010110; Assembly Description: Partitions - Brick, Solid; Type Name: SW - 014 1585887
Type - Other - Category: Walls; Family Name: SW - 014 1585887
Type - Pset_ProductRequirements - Category: Walls
Type - Pset_QuantityTakeOff - Reference: SW - 014 1585887
Type - Pset_ReinforcementBarPitchOfWall - Reference: SW - 014 1585887
Type - Pset_WallCommon - IsExternal: no; Reference: SW - 014 1585887
Classification: C1010110 Partitions - Brick, Solid (Uniformat)
Constraints - Moves With Nearby Elements: no; Room Bounding: yes
Dimensions - Area: 14.0639 m2; Volume: 1.79785 m3
Other - Family: SW - 014 1585887: SW - 014 1585887; Family and Type: SW - 014 1585887: SW - 014 1585887; Type: SW - 014 1585887: SW - 014 1585887; Type Id: SW - 014 1585887: SW - 014 1585887
Phasing - Phase Created: New Construction
Pset_QuantityTakeOff - sets with these values: 2

# IfcWall: SW - 015, SW - 015:SW - 015:202523
In: -2. Story
Type - Material: Stucco - White Fine
Type - Identity Data - Assembly Code: C1010110; Assembly Description: Partitions - Brick, Solid; Type Name: SW - 015
Type - Other - Category: Walls; Family Name: SW - 015
Type - Pset_ProductRequirements - Category: Walls
Type - Pset_QuantityTakeOff - Reference: SW - 015
Type - Pset_ReinforcementBarPitchOfWall - Reference: SW - 015
Type - Pset_WallCommon - IsExternal: no; Reference: SW - 015
Classification: C1010110 Partitions - Brick, Solid (Uniformat)
Constraints - Moves With Nearby Elements: no; Room Bounding: yes
Dimensions - Area: 2.1975 m2; Volume: 5.95522 m3
Other - Family: SW - 015: SW - 015; Family and Type: SW - 015: SW - 015; Type: SW - 015: SW - 015; Type Id: SW - 015: SW - 015
Phasing - Phase Created: New Construction
Pset_QuantityTakeOff - sets with these values: 2

# IfcWall: SW - 015, SW - 015 1508229:SW - 015 1508229:204853
In: -2. Story
Type - Material: Stucco - White Fine
Type - Identity Data - Assembly Code: C1010110; Assembly Description: Partitions - Brick, Solid; Type Name: SW - 015 1508229
Type - Other - Category: Walls; Family Name: SW - 015 1508229
Type - Pset_ProductRequirements - Category: Walls
Type - Pset_QuantityTakeOff - Reference: SW - 015 1508229
Type - Pset_ReinforcementBarPitchOfWall - Reference: SW - 015 1508229
Type - Pset_WallCommon - IsExternal: no; Reference: SW - 015 1508229
Classification: C1010110 Partitions - Brick, Solid (Uniformat)
Constraints - Moves With Nearby Elements: no; Room Bounding: yes
Dimensions - Area: 1.81287 m2; Volume: 4.91289 m3
Other - Family: SW - 015 1508229: SW - 015 1508229; Family and Type: SW - 015 1508229: SW - 015 1508229; Type: SW - 015 1508229: SW - 015 1508229; Type Id: SW - 015 1508229: SW - 015 1508229
Phasing - Phase Created: New Construction
Pset_QuantityTakeOff - sets with these values: 2

# IfcWall: SW - 015, SW - 015 1539402:SW - 015 1539402:207071
In: -2. Story
Type - Material: Stucco - White Fine
Type - Identity Data - Assembly Code: C1010110; Assembly Description: Partitions - Brick, Solid; Type Name: SW - 015 1539402
Type - Other - Category: Walls; Family Name: SW - 015 1539402
Type - Pset_ProductRequirements - Category: Walls
Type - Pset_QuantityTakeOff - Reference: SW - 015 1539402
Type - Pset_ReinforcementBarPitchOfWall - Reference: SW - 015 1539402
Type - Pset_WallCommon - IsExternal: no; Reference: SW - 015 1539402
Classification: C1010110 Partitions - Brick, Solid (Uniformat)
Constraints - Moves With Nearby Elements: no; Room Bounding: yes
Dimensions - Area: 2.20434 m2; Volume: 5.97377 m3
Other - Family: SW - 015 1539402: SW - 015 1539402; Family and Type: SW - 015 1539402: SW - 015 1539402; Type: SW - 015 1539402: SW - 015 1539402; Type Id: SW - 015 1539402: SW - 015 1539402
Phasing - Phase Created: New Construction
Pset_QuantityTakeOff - sets with these values: 2

# IfcWall: SW - 015, SW - 015 1539919:SW - 015 1539919:207108
In: -2. Story
Type - Material: Stucco - White Fine
Type - Identity Data - Assembly Code: C1010110; Assembly Description: Partitions - Brick, Solid; Type Name: SW - 015 1539919
Type - Other - Category: Walls; Family Name: SW - 015 1539919
Type - Pset_ProductRequirements - Category: Walls
Type - Pset_QuantityTakeOff - Reference: SW - 015 1539919
Type - Pset_ReinforcementBarPitchOfWall - Reference: SW - 015 1539919
Type - Pset_WallCommon - IsExternal: no; Reference: SW - 015 1539919
Classification: C1010110 Partitions - Brick, Solid (Uniformat)
Constraints - Moves With Nearby Elements: no; Room Bounding: yes
Dimensions - Area: 2.14559 m2; Volume: 5.81456 m3
Other - Family: SW - 015 1539919: SW - 015 1539919; Family and Type: SW - 015 1539919: SW - 015 1539919; Type: SW - 015 1539919: SW - 015 1539919; Type Id: SW - 015 1539919: SW - 015 1539919
Phasing - Phase Created: New Construction
Pset_QuantityTakeOff - sets with these values: 2

# IfcWall: SW - 015, SW - 015 1587253:SW - 015 1587253:208925
In: -2. Story
Type - Material: Stucco - White Fine
Type - Identity Data - Assembly Code: C1010110; Assembly Description: Partitions - Brick, Solid; Type Name: SW - 015 1587253
Type - Other - Category: Walls; Family Name: SW - 015 1587253
Type - Pset_ProductRequirements - Category: Walls
Type - Pset_QuantityTakeOff - Reference: SW - 015 1587253
Type - Pset_ReinforcementBarPitchOfWall - Reference: SW - 015 1587253
Type - Pset_WallCommon - IsExternal: no; Reference: SW - 015 1587253
Classification: C1010110 Partitions - Brick, Solid (Uniformat)
Constraints - Moves With Nearby Elements: no; Room Bounding: yes
Dimensions - Area: 2.1975 m2; Volume: 5.95523 m3
Other - Family: SW - 015 1587253: SW - 015 1587253; Family and Type: SW - 015 1587253: SW - 015 1587253; Type: SW - 015 1587253: SW - 015 1587253; Type Id: SW - 015 1587253: SW - 015 1587253
Phasing - Phase Created: New Construction
Pset_QuantityTakeOff - sets with these values: 2

# IfcWall: SW - 015, SW - 015 1587762:SW - 015 1587762:208955
In: -2. Story
Type - Material: Stucco - White Fine
Type - Identity Data - Assembly Code: C1010110; Assembly Description: Partitions - Brick, Solid; Type Name: SW - 015 1587762
Type - Other - Category: Walls; Family Name: SW - 015 1587762
Type - Pset_ProductRequirements - Category: Walls
Type - Pset_QuantityTakeOff - Reference: SW - 015 1587762
Type - Pset_ReinforcementBarPitchOfWall - Reference: SW - 015 1587762
Type - Pset_WallCommon - IsExternal: no; Reference: SW - 015 1587762
Classification: C1010110 Partitions - Brick, Solid (Uniformat)
Constraints - Moves With Nearby Elements: no; Room Bounding: yes
Dimensions - Area: 1.81288 m2; Volume: 4.91289 m3
Other - Family: SW - 015 1587762: SW - 015 1587762; Family and Type: SW - 015 1587762: SW - 015 1587762; Type: SW - 015 1587762: SW - 015 1587762; Type Id: SW - 015 1587762: SW - 015 1587762
Phasing - Phase Created: New Construction
Pset_QuantityTakeOff - sets with these values: 2

# IfcWall: SW - 015, SW - 015 1601783:SW - 015 1601783:210708
In: -2. Story
Type - Material: Stucco - White Fine
Type - Identity Data - Assembly Code: C1010110; Assembly Description: Partitions - Brick, Solid; Type Name: SW - 015 1601783
Type - Other - Category: Walls; Family Name: SW - 015 1601783
Type - Pset_ProductRequirements - Category: Walls
Type - Pset_QuantityTakeOff - Reference: SW - 015 1601783
Type - Pset_ReinforcementBarPitchOfWall - Reference: SW - 015 1601783
Type - Pset_WallCommon - IsExternal: no; Reference: SW - 015 1601783
Classification: C1010110 Partitions - Brick, Solid (Uniformat)
Constraints - Moves With Nearby Elements: no; Room Bounding: yes
Dimensions - Area: 2.20434 m2; Volume: 5.97377 m3
Other - Family: SW - 015 1601783: SW - 015 1601783; Family and Type: SW - 015 1601783: SW - 015 1601783; Type: SW - 015 1601783: SW - 015 1601783; Type Id: SW - 015 1601783: SW - 015 1601783
Phasing - Phase Created: New Construction
Pset_QuantityTakeOff - sets with these values: 2

# IfcWall: SW - 015, SW - 015 1602304:SW - 015 1602304:210745
In: -2. Story
Type - Material: Stucco - White Fine
Type - Identity Data - Assembly Code: C1010110; Assembly Description: Partitions - Brick, Solid; Type Name: SW - 015 1602304
Type - Other - Category: Walls; Family Name: SW - 015 1602304
Type - Pset_ProductRequirements - Category: Walls
Type - Pset_QuantityTakeOff - Reference: SW - 015 1602304
Type - Pset_ReinforcementBarPitchOfWall - Reference: SW - 015 1602304
Type - Pset_WallCommon - IsExternal: no; Reference: SW - 015 1602304
Classification: C1010110 Partitions - Brick, Solid (Uniformat)
Constraints - Moves With Nearby Elements: no; Room Bounding: yes
Dimensions - Area: 2.14559 m2; Volume: 5.81456 m3
Other - Family: SW - 015 1602304: SW - 015 1602304; Family and Type: SW - 015 1602304: SW - 015 1602304; Type: SW - 015 1602304: SW - 015 1602304; Type Id: SW - 015 1602304: SW - 015 1602304
Phasing - Phase Created: New Construction
Pset_QuantityTakeOff - sets with these values: 2

# IfcWall: SW - 016, SW - 016:SW - 016:207006
In: -2. Story
Type - Material: Stucco - White Fine
Type - Identity Data - Assembly Code: C1010110; Assembly Description: Partitions - Brick, Solid; Type Name: SW - 016
Type - Other - Category: Walls; Family Name: SW - 016
Type - Pset_ProductRequirements - Category: Walls
Type - Pset_QuantityTakeOff - Reference: SW - 016
Type - Pset_ReinforcementBarPitchOfWall - Reference: SW - 016
Type - Pset_WallCommon - IsExternal: no; Reference: SW - 016
Classification: C1010110 Partitions - Brick, Solid (Uniformat)
Constraints - Moves With Nearby Elements: no; Room Bounding: yes
Dimensions - Area: 0.125185 m2; Volume: 0.339253 m3
Other - Family: SW - 016: SW - 016; Family and Type: SW - 016: SW - 016; Type: SW - 016: SW - 016; Type Id: SW - 016: SW - 016
Phasing - Phase Created: New Construction
Pset_QuantityTakeOff - sets with these values: 2

# IfcWall: SW - 016, SW - 016 1571308:SW - 016 1571308:208625
In: -2. Story
Type - Material: Stucco - White Fine
Type - Identity Data - Assembly Code: C1010110; Assembly Description: Partitions - Brick, Solid; Type Name: SW - 016 1571308
Type - Other - Category: Walls; Family Name: SW - 016 1571308
Type - Pset_ProductRequirements - Category: Walls
Type - Pset_QuantityTakeOff - Reference: SW - 016 1571308
Type - Pset_ReinforcementBarPitchOfWall - Reference: SW - 016 1571308
Type - Pset_WallCommon - IsExternal: no; Reference: SW - 016 1571308
Classification: C1010110 Partitions - Brick, Solid (Uniformat)
Constraints - Moves With Nearby Elements: no; Room Bounding: yes
Dimensions - Area: 0.125185 m2; Volume: 0.339253 m3
Other - Family: SW - 016 1571308: SW - 016 1571308; Family and Type: SW - 016 1571308: SW - 016 1571308; Type: SW - 016 1571308: SW - 016 1571308; Type Id: SW - 016 1571308: SW - 016 1571308
Phasing - Phase Created: New Construction
Pset_QuantityTakeOff - sets with these values: 2

# IfcWall: SW - 016, SW - 016 1586748:SW - 016 1586748:208895
In: -2. Story
Type - Material: Stucco - White Fine
Type - Identity Data - Assembly Code: C1010110; Assembly Description: Partitions - Brick, Solid; Type Name: SW - 016 1586748
Type - Other - Category: Walls; Family Name: SW - 016 1586748
Type - Pset_ProductRequirements - Category: Walls
Type - Pset_QuantityTakeOff - Reference: SW - 016 1586748
Type - Pset_ReinforcementBarPitchOfWall - Reference: SW - 016 1586748
Type - Pset_WallCommon - IsExternal: no; Reference: SW - 016 1586748
Classification: C1010110 Partitions - Brick, Solid (Uniformat)
Constraints - Moves With Nearby Elements: no; Room Bounding: yes
Dimensions - Area: 0.125185 m2; Volume: 0.339253 m3
Other - Family: SW - 016 1586748: SW - 016 1586748; Family and Type: SW - 016 1586748: SW - 016 1586748; Type: SW - 016 1586748: SW - 016 1586748; Type Id: SW - 016 1586748: SW - 016 1586748
Phasing - Phase Created: New Construction
Pset_QuantityTakeOff - sets with these values: 2

# IfcWall: SW - 016, SW - 016 1594780:SW - 016 1594780:210643
In: -2. Story
Type - Material: Stucco - White Fine
Type - Identity Data - Assembly Code: C1010110; Assembly Description: Partitions - Brick, Solid; Type Name: SW - 016 1594780
Type - Other - Category: Walls; Family Name: SW - 016 1594780
Type - Pset_ProductRequirements - Category: Walls
Type - Pset_QuantityTakeOff - Reference: SW - 016 1594780
Type - Pset_ReinforcementBarPitchOfWall - Reference: SW - 016 1594780
Type - Pset_WallCommon - IsExternal: no; Reference: SW - 016 1594780
Classification: C1010110 Partitions - Brick, Solid (Uniformat)
Constraints - Moves With Nearby Elements: no; Room Bounding: yes
Dimensions - Area: 0.125185 m2; Volume: 0.339253 m3
Other - Family: SW - 016 1594780: SW - 016 1594780; Family and Type: SW - 016 1594780: SW - 016 1594780; Type: SW - 016 1594780: SW - 016 1594780; Type Id: SW - 016 1594780: SW - 016 1594780
Phasing - Phase Created: New Construction
Pset_QuantityTakeOff - sets with these values: 2
